VERSION 5.8 ;
BUSBITCHARS "[]" ;
DIVIDERCHAR "/" ;
UNITS
    DATABASE MICRONS 1000 ;
END UNITS

VIA ino_decode_queue_via1_2_1000_440_1_2_410_410
  VIARULE via1Array ;
  CUTSIZE 0.19 0.19 ;
  LAYERS Metal1 Via1 Metal2 ;
  CUTSPACING 0.22 0.22 ;
  ENCLOSURE 0.05 0.125 0.005 0.05 ;
  ROWCOL 1 2 ;
END ino_decode_queue_via1_2_1000_440_1_2_410_410

VIA ino_decode_queue_via2_3_1000_440_1_2_410_410
  VIARULE via2Array ;
  CUTSIZE 0.19 0.19 ;
  LAYERS Metal2 Via2 Metal3 ;
  CUTSPACING 0.22 0.22 ;
  ENCLOSURE 0.005 0.05 0.05 0.005 ;
  ROWCOL 1 2 ;
END ino_decode_queue_via2_3_1000_440_1_2_410_410

VIA ino_decode_queue_via3_4_1000_440_1_2_410_410
  VIARULE via3Array ;
  CUTSIZE 0.19 0.19 ;
  LAYERS Metal3 Via3 Metal4 ;
  CUTSPACING 0.22 0.22 ;
  ENCLOSURE 0.05 0.005 0.2 0.05 ;
  ROWCOL 1 2 ;
END ino_decode_queue_via3_4_1000_440_1_2_410_410

VIA ino_decode_queue_via4_5_1000_2000_1_1_840_840
  VIARULE viaTop1Array ;
  CUTSIZE 0.42 0.42 ;
  LAYERS Metal4 TopVia1 TopMetal1 ;
  CUTSPACING 0.42 0.42 ;
  ENCLOSURE 0.29 0.1 0.42 0.79 ;
END ino_decode_queue_via4_5_1000_2000_1_1_840_840

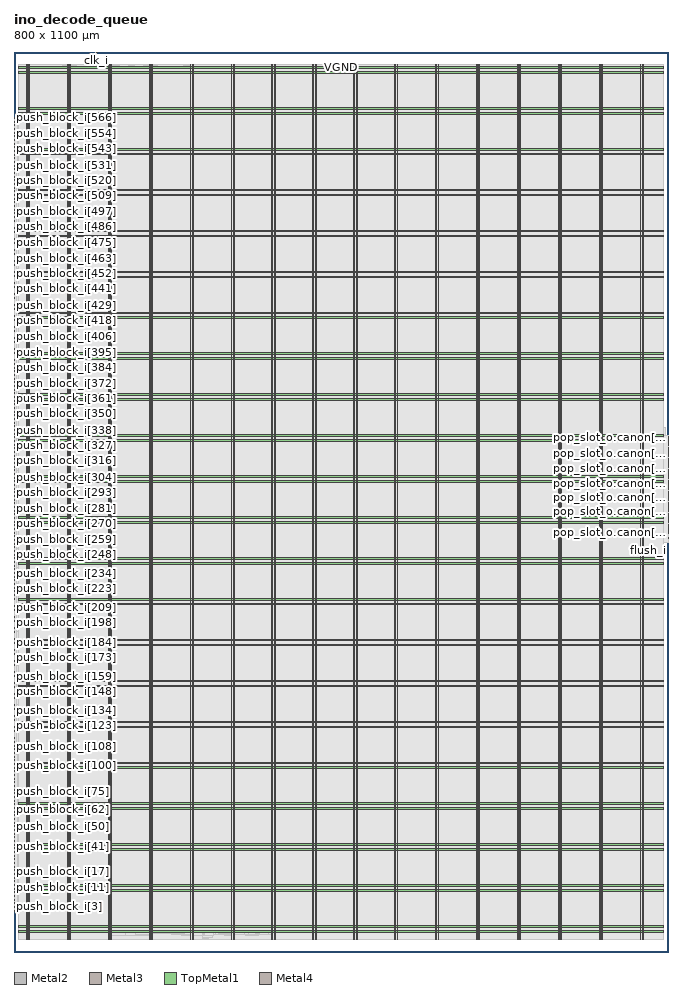
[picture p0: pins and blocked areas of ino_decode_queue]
MACRO ino_decode_queue
  FOREIGN ino_decode_queue 0 0 ;
  CLASS BLOCK ;
  SIZE 800 BY 1100 ;
  PIN clk_i
    DIRECTION INPUT ;
    USE SIGNAL ;
    PORT
      LAYER Metal2 ;
        RECT  101.08 1099.6 101.48 1100 ;
    END
  END clk_i
  PIN flush_i
    DIRECTION INPUT ;
    USE SIGNAL ;
    PORT
      LAYER Metal3 ;
        RECT  799.6 500.02 800 500.42 ;
    END
  END flush_i
  PIN pop_slot_o.canon[0]
    DIRECTION OUTPUT ;
    USE SIGNAL ;
    PORT
      LAYER Metal3 ;
        RECT  799.6 512.62 800 513.02 ;
    END
  END pop_slot_o.canon[0]
  PIN pop_slot_o.canon[10]
    DIRECTION OUTPUT ;
    USE SIGNAL ;
    PORT
      LAYER Metal3 ;
        RECT  799.6 537.82 800 538.22 ;
    END
  END pop_slot_o.canon[10]
  PIN pop_slot_o.canon[11]
    DIRECTION OUTPUT ;
    USE SIGNAL ;
    PORT
      LAYER Metal3 ;
        RECT  799.6 540.34 800 540.74 ;
    END
  END pop_slot_o.canon[11]
  PIN pop_slot_o.canon[12]
    DIRECTION OUTPUT ;
    USE SIGNAL ;
    PORT
      LAYER Metal3 ;
        RECT  799.6 542.86 800 543.26 ;
    END
  END pop_slot_o.canon[12]
  PIN pop_slot_o.canon[13]
    DIRECTION OUTPUT ;
    USE SIGNAL ;
    PORT
      LAYER Metal3 ;
        RECT  799.6 545.38 800 545.78 ;
    END
  END pop_slot_o.canon[13]
  PIN pop_slot_o.canon[14]
    DIRECTION OUTPUT ;
    USE SIGNAL ;
    PORT
      LAYER Metal3 ;
        RECT  799.6 547.9 800 548.3 ;
    END
  END pop_slot_o.canon[14]
  PIN pop_slot_o.canon[15]
    DIRECTION OUTPUT ;
    USE SIGNAL ;
    PORT
      LAYER Metal3 ;
        RECT  799.6 550.42 800 550.82 ;
    END
  END pop_slot_o.canon[15]
  PIN pop_slot_o.canon[16]
    DIRECTION OUTPUT ;
    USE SIGNAL ;
    PORT
      LAYER Metal3 ;
        RECT  799.6 552.94 800 553.34 ;
    END
  END pop_slot_o.canon[16]
  PIN pop_slot_o.canon[17]
    DIRECTION OUTPUT ;
    USE SIGNAL ;
    PORT
      LAYER Metal3 ;
        RECT  799.6 555.46 800 555.86 ;
    END
  END pop_slot_o.canon[17]
  PIN pop_slot_o.canon[18]
    DIRECTION OUTPUT ;
    USE SIGNAL ;
    PORT
      LAYER Metal3 ;
        RECT  799.6 557.98 800 558.38 ;
    END
  END pop_slot_o.canon[18]
  PIN pop_slot_o.canon[19]
    DIRECTION OUTPUT ;
    USE SIGNAL ;
    PORT
      LAYER Metal3 ;
        RECT  799.6 560.5 800 560.9 ;
    END
  END pop_slot_o.canon[19]
  PIN pop_slot_o.canon[1]
    DIRECTION OUTPUT ;
    USE SIGNAL ;
    PORT
      LAYER Metal3 ;
        RECT  799.6 515.14 800 515.54 ;
    END
  END pop_slot_o.canon[1]
  PIN pop_slot_o.canon[20]
    DIRECTION OUTPUT ;
    USE SIGNAL ;
    PORT
      LAYER Metal3 ;
        RECT  799.6 563.02 800 563.42 ;
    END
  END pop_slot_o.canon[20]
  PIN pop_slot_o.canon[21]
    DIRECTION OUTPUT ;
    USE SIGNAL ;
    PORT
      LAYER Metal3 ;
        RECT  799.6 565.54 800 565.94 ;
    END
  END pop_slot_o.canon[21]
  PIN pop_slot_o.canon[22]
    DIRECTION OUTPUT ;
    USE SIGNAL ;
    PORT
      LAYER Metal3 ;
        RECT  799.6 568.06 800 568.46 ;
    END
  END pop_slot_o.canon[22]
  PIN pop_slot_o.canon[23]
    DIRECTION OUTPUT ;
    USE SIGNAL ;
    PORT
      LAYER Metal3 ;
        RECT  799.6 570.58 800 570.98 ;
    END
  END pop_slot_o.canon[23]
  PIN pop_slot_o.canon[24]
    DIRECTION OUTPUT ;
    USE SIGNAL ;
    PORT
      LAYER Metal3 ;
        RECT  799.6 573.1 800 573.5 ;
    END
  END pop_slot_o.canon[24]
  PIN pop_slot_o.canon[25]
    DIRECTION OUTPUT ;
    USE SIGNAL ;
    PORT
      LAYER Metal3 ;
        RECT  799.6 575.62 800 576.02 ;
    END
  END pop_slot_o.canon[25]
  PIN pop_slot_o.canon[26]
    DIRECTION OUTPUT ;
    USE SIGNAL ;
    PORT
      LAYER Metal3 ;
        RECT  799.6 578.14 800 578.54 ;
    END
  END pop_slot_o.canon[26]
  PIN pop_slot_o.canon[27]
    DIRECTION OUTPUT ;
    USE SIGNAL ;
    PORT
      LAYER Metal3 ;
        RECT  799.6 580.66 800 581.06 ;
    END
  END pop_slot_o.canon[27]
  PIN pop_slot_o.canon[28]
    DIRECTION OUTPUT ;
    USE SIGNAL ;
    PORT
      LAYER Metal3 ;
        RECT  799.6 583.18 800 583.58 ;
    END
  END pop_slot_o.canon[28]
  PIN pop_slot_o.canon[29]
    DIRECTION OUTPUT ;
    USE SIGNAL ;
    PORT
      LAYER Metal3 ;
        RECT  799.6 585.7 800 586.1 ;
    END
  END pop_slot_o.canon[29]
  PIN pop_slot_o.canon[2]
    DIRECTION OUTPUT ;
    USE SIGNAL ;
    PORT
      LAYER Metal3 ;
        RECT  799.6 517.66 800 518.06 ;
    END
  END pop_slot_o.canon[2]
  PIN pop_slot_o.canon[30]
    DIRECTION OUTPUT ;
    USE SIGNAL ;
    PORT
      LAYER Metal3 ;
        RECT  799.6 588.22 800 588.62 ;
    END
  END pop_slot_o.canon[30]
  PIN pop_slot_o.canon[31]
    DIRECTION OUTPUT ;
    USE SIGNAL ;
    PORT
      LAYER Metal3 ;
        RECT  799.6 590.74 800 591.14 ;
    END
  END pop_slot_o.canon[31]
  PIN pop_slot_o.canon[32]
    DIRECTION OUTPUT ;
    USE SIGNAL ;
    PORT
      LAYER Metal3 ;
        RECT  799.6 593.26 800 593.66 ;
    END
  END pop_slot_o.canon[32]
  PIN pop_slot_o.canon[33]
    DIRECTION OUTPUT ;
    USE SIGNAL ;
    PORT
      LAYER Metal3 ;
        RECT  799.6 594.94 800 595.34 ;
    END
  END pop_slot_o.canon[33]
  PIN pop_slot_o.canon[34]
    DIRECTION OUTPUT ;
    USE SIGNAL ;
    PORT
      LAYER Metal3 ;
        RECT  799.6 596.62 800 597.02 ;
    END
  END pop_slot_o.canon[34]
  PIN pop_slot_o.canon[35]
    DIRECTION OUTPUT ;
    USE SIGNAL ;
    PORT
      LAYER Metal3 ;
        RECT  799.6 598.3 800 598.7 ;
    END
  END pop_slot_o.canon[35]
  PIN pop_slot_o.canon[36]
    DIRECTION OUTPUT ;
    USE SIGNAL ;
    PORT
      LAYER Metal3 ;
        RECT  799.6 599.98 800 600.38 ;
    END
  END pop_slot_o.canon[36]
  PIN pop_slot_o.canon[37]
    DIRECTION OUTPUT ;
    USE SIGNAL ;
    PORT
      LAYER Metal3 ;
        RECT  799.6 601.66 800 602.06 ;
    END
  END pop_slot_o.canon[37]
  PIN pop_slot_o.canon[38]
    DIRECTION OUTPUT ;
    USE SIGNAL ;
    PORT
      LAYER Metal3 ;
        RECT  799.6 603.34 800 603.74 ;
    END
  END pop_slot_o.canon[38]
  PIN pop_slot_o.canon[39]
    DIRECTION OUTPUT ;
    USE SIGNAL ;
    PORT
      LAYER Metal3 ;
        RECT  799.6 605.02 800 605.42 ;
    END
  END pop_slot_o.canon[39]
  PIN pop_slot_o.canon[3]
    DIRECTION OUTPUT ;
    USE SIGNAL ;
    PORT
      LAYER Metal3 ;
        RECT  799.6 520.18 800 520.58 ;
    END
  END pop_slot_o.canon[3]
  PIN pop_slot_o.canon[40]
    DIRECTION OUTPUT ;
    USE SIGNAL ;
    PORT
      LAYER Metal3 ;
        RECT  799.6 606.7 800 607.1 ;
    END
  END pop_slot_o.canon[40]
  PIN pop_slot_o.canon[41]
    DIRECTION OUTPUT ;
    USE SIGNAL ;
    PORT
      LAYER Metal3 ;
        RECT  799.6 608.38 800 608.78 ;
    END
  END pop_slot_o.canon[41]
  PIN pop_slot_o.canon[42]
    DIRECTION OUTPUT ;
    USE SIGNAL ;
    PORT
      LAYER Metal3 ;
        RECT  799.6 610.06 800 610.46 ;
    END
  END pop_slot_o.canon[42]
  PIN pop_slot_o.canon[43]
    DIRECTION OUTPUT ;
    USE SIGNAL ;
    PORT
      LAYER Metal3 ;
        RECT  799.6 611.74 800 612.14 ;
    END
  END pop_slot_o.canon[43]
  PIN pop_slot_o.canon[44]
    DIRECTION OUTPUT ;
    USE SIGNAL ;
    PORT
      LAYER Metal3 ;
        RECT  799.6 613.42 800 613.82 ;
    END
  END pop_slot_o.canon[44]
  PIN pop_slot_o.canon[45]
    DIRECTION OUTPUT ;
    USE SIGNAL ;
    PORT
      LAYER Metal3 ;
        RECT  799.6 615.1 800 615.5 ;
    END
  END pop_slot_o.canon[45]
  PIN pop_slot_o.canon[46]
    DIRECTION OUTPUT ;
    USE SIGNAL ;
    PORT
      LAYER Metal3 ;
        RECT  799.6 616.78 800 617.18 ;
    END
  END pop_slot_o.canon[46]
  PIN pop_slot_o.canon[47]
    DIRECTION OUTPUT ;
    USE SIGNAL ;
    PORT
      LAYER Metal3 ;
        RECT  799.6 618.46 800 618.86 ;
    END
  END pop_slot_o.canon[47]
  PIN pop_slot_o.canon[48]
    DIRECTION OUTPUT ;
    USE SIGNAL ;
    PORT
      LAYER Metal3 ;
        RECT  799.6 620.14 800 620.54 ;
    END
  END pop_slot_o.canon[48]
  PIN pop_slot_o.canon[49]
    DIRECTION OUTPUT ;
    USE SIGNAL ;
    PORT
      LAYER Metal3 ;
        RECT  799.6 621.82 800 622.22 ;
    END
  END pop_slot_o.canon[49]
  PIN pop_slot_o.canon[4]
    DIRECTION OUTPUT ;
    USE SIGNAL ;
    PORT
      LAYER Metal3 ;
        RECT  799.6 522.7 800 523.1 ;
    END
  END pop_slot_o.canon[4]
  PIN pop_slot_o.canon[50]
    DIRECTION OUTPUT ;
    USE SIGNAL ;
    PORT
      LAYER Metal3 ;
        RECT  799.6 623.5 800 623.9 ;
    END
  END pop_slot_o.canon[50]
  PIN pop_slot_o.canon[51]
    DIRECTION OUTPUT ;
    USE SIGNAL ;
    PORT
      LAYER Metal3 ;
        RECT  799.6 625.18 800 625.58 ;
    END
  END pop_slot_o.canon[51]
  PIN pop_slot_o.canon[52]
    DIRECTION OUTPUT ;
    USE SIGNAL ;
    PORT
      LAYER Metal3 ;
        RECT  799.6 626.86 800 627.26 ;
    END
  END pop_slot_o.canon[52]
  PIN pop_slot_o.canon[53]
    DIRECTION OUTPUT ;
    USE SIGNAL ;
    PORT
      LAYER Metal3 ;
        RECT  799.6 628.54 800 628.94 ;
    END
  END pop_slot_o.canon[53]
  PIN pop_slot_o.canon[54]
    DIRECTION OUTPUT ;
    USE SIGNAL ;
    PORT
      LAYER Metal3 ;
        RECT  799.6 630.22 800 630.62 ;
    END
  END pop_slot_o.canon[54]
  PIN pop_slot_o.canon[55]
    DIRECTION OUTPUT ;
    USE SIGNAL ;
    PORT
      LAYER Metal3 ;
        RECT  799.6 631.06 800 631.46 ;
    END
  END pop_slot_o.canon[55]
  PIN pop_slot_o.canon[5]
    DIRECTION OUTPUT ;
    USE SIGNAL ;
    PORT
      LAYER Metal3 ;
        RECT  799.6 525.22 800 525.62 ;
    END
  END pop_slot_o.canon[5]
  PIN pop_slot_o.canon[6]
    DIRECTION OUTPUT ;
    USE SIGNAL ;
    PORT
      LAYER Metal3 ;
        RECT  799.6 527.74 800 528.14 ;
    END
  END pop_slot_o.canon[6]
  PIN pop_slot_o.canon[7]
    DIRECTION OUTPUT ;
    USE SIGNAL ;
    PORT
      LAYER Metal3 ;
        RECT  799.6 530.26 800 530.66 ;
    END
  END pop_slot_o.canon[7]
  PIN pop_slot_o.canon[8]
    DIRECTION OUTPUT ;
    USE SIGNAL ;
    PORT
      LAYER Metal3 ;
        RECT  799.6 532.78 800 533.18 ;
    END
  END pop_slot_o.canon[8]
  PIN pop_slot_o.canon[9]
    DIRECTION OUTPUT ;
    USE SIGNAL ;
    PORT
      LAYER Metal3 ;
        RECT  799.6 535.3 800 535.7 ;
    END
  END pop_slot_o.canon[9]
  PIN pop_slot_o.pc[0]
    DIRECTION OUTPUT ;
    USE SIGNAL ;
    PORT
      LAYER Metal3 ;
        RECT  799.6 513.46 800 513.86 ;
    END
  END pop_slot_o.pc[0]
  PIN pop_slot_o.pc[10]
    DIRECTION OUTPUT ;
    USE SIGNAL ;
    PORT
      LAYER Metal3 ;
        RECT  799.6 538.66 800 539.06 ;
    END
  END pop_slot_o.pc[10]
  PIN pop_slot_o.pc[11]
    DIRECTION OUTPUT ;
    USE SIGNAL ;
    PORT
      LAYER Metal3 ;
        RECT  799.6 541.18 800 541.58 ;
    END
  END pop_slot_o.pc[11]
  PIN pop_slot_o.pc[12]
    DIRECTION OUTPUT ;
    USE SIGNAL ;
    PORT
      LAYER Metal3 ;
        RECT  799.6 543.7 800 544.1 ;
    END
  END pop_slot_o.pc[12]
  PIN pop_slot_o.pc[13]
    DIRECTION OUTPUT ;
    USE SIGNAL ;
    PORT
      LAYER Metal3 ;
        RECT  799.6 546.22 800 546.62 ;
    END
  END pop_slot_o.pc[13]
  PIN pop_slot_o.pc[14]
    DIRECTION OUTPUT ;
    USE SIGNAL ;
    PORT
      LAYER Metal3 ;
        RECT  799.6 548.74 800 549.14 ;
    END
  END pop_slot_o.pc[14]
  PIN pop_slot_o.pc[15]
    DIRECTION OUTPUT ;
    USE SIGNAL ;
    PORT
      LAYER Metal3 ;
        RECT  799.6 551.26 800 551.66 ;
    END
  END pop_slot_o.pc[15]
  PIN pop_slot_o.pc[16]
    DIRECTION OUTPUT ;
    USE SIGNAL ;
    PORT
      LAYER Metal3 ;
        RECT  799.6 553.78 800 554.18 ;
    END
  END pop_slot_o.pc[16]
  PIN pop_slot_o.pc[17]
    DIRECTION OUTPUT ;
    USE SIGNAL ;
    PORT
      LAYER Metal3 ;
        RECT  799.6 556.3 800 556.7 ;
    END
  END pop_slot_o.pc[17]
  PIN pop_slot_o.pc[18]
    DIRECTION OUTPUT ;
    USE SIGNAL ;
    PORT
      LAYER Metal3 ;
        RECT  799.6 558.82 800 559.22 ;
    END
  END pop_slot_o.pc[18]
  PIN pop_slot_o.pc[19]
    DIRECTION OUTPUT ;
    USE SIGNAL ;
    PORT
      LAYER Metal3 ;
        RECT  799.6 561.34 800 561.74 ;
    END
  END pop_slot_o.pc[19]
  PIN pop_slot_o.pc[1]
    DIRECTION OUTPUT ;
    USE SIGNAL ;
    PORT
      LAYER Metal3 ;
        RECT  799.6 515.98 800 516.38 ;
    END
  END pop_slot_o.pc[1]
  PIN pop_slot_o.pc[20]
    DIRECTION OUTPUT ;
    USE SIGNAL ;
    PORT
      LAYER Metal3 ;
        RECT  799.6 563.86 800 564.26 ;
    END
  END pop_slot_o.pc[20]
  PIN pop_slot_o.pc[21]
    DIRECTION OUTPUT ;
    USE SIGNAL ;
    PORT
      LAYER Metal3 ;
        RECT  799.6 566.38 800 566.78 ;
    END
  END pop_slot_o.pc[21]
  PIN pop_slot_o.pc[22]
    DIRECTION OUTPUT ;
    USE SIGNAL ;
    PORT
      LAYER Metal3 ;
        RECT  799.6 568.9 800 569.3 ;
    END
  END pop_slot_o.pc[22]
  PIN pop_slot_o.pc[23]
    DIRECTION OUTPUT ;
    USE SIGNAL ;
    PORT
      LAYER Metal3 ;
        RECT  799.6 571.42 800 571.82 ;
    END
  END pop_slot_o.pc[23]
  PIN pop_slot_o.pc[24]
    DIRECTION OUTPUT ;
    USE SIGNAL ;
    PORT
      LAYER Metal3 ;
        RECT  799.6 573.94 800 574.34 ;
    END
  END pop_slot_o.pc[24]
  PIN pop_slot_o.pc[25]
    DIRECTION OUTPUT ;
    USE SIGNAL ;
    PORT
      LAYER Metal3 ;
        RECT  799.6 576.46 800 576.86 ;
    END
  END pop_slot_o.pc[25]
  PIN pop_slot_o.pc[26]
    DIRECTION OUTPUT ;
    USE SIGNAL ;
    PORT
      LAYER Metal3 ;
        RECT  799.6 578.98 800 579.38 ;
    END
  END pop_slot_o.pc[26]
  PIN pop_slot_o.pc[27]
    DIRECTION OUTPUT ;
    USE SIGNAL ;
    PORT
      LAYER Metal3 ;
        RECT  799.6 581.5 800 581.9 ;
    END
  END pop_slot_o.pc[27]
  PIN pop_slot_o.pc[28]
    DIRECTION OUTPUT ;
    USE SIGNAL ;
    PORT
      LAYER Metal3 ;
        RECT  799.6 584.02 800 584.42 ;
    END
  END pop_slot_o.pc[28]
  PIN pop_slot_o.pc[29]
    DIRECTION OUTPUT ;
    USE SIGNAL ;
    PORT
      LAYER Metal3 ;
        RECT  799.6 586.54 800 586.94 ;
    END
  END pop_slot_o.pc[29]
  PIN pop_slot_o.pc[2]
    DIRECTION OUTPUT ;
    USE SIGNAL ;
    PORT
      LAYER Metal3 ;
        RECT  799.6 518.5 800 518.9 ;
    END
  END pop_slot_o.pc[2]
  PIN pop_slot_o.pc[30]
    DIRECTION OUTPUT ;
    USE SIGNAL ;
    PORT
      LAYER Metal3 ;
        RECT  799.6 589.06 800 589.46 ;
    END
  END pop_slot_o.pc[30]
  PIN pop_slot_o.pc[31]
    DIRECTION OUTPUT ;
    USE SIGNAL ;
    PORT
      LAYER Metal3 ;
        RECT  799.6 591.58 800 591.98 ;
    END
  END pop_slot_o.pc[31]
  PIN pop_slot_o.pc[3]
    DIRECTION OUTPUT ;
    USE SIGNAL ;
    PORT
      LAYER Metal3 ;
        RECT  799.6 521.02 800 521.42 ;
    END
  END pop_slot_o.pc[3]
  PIN pop_slot_o.pc[4]
    DIRECTION OUTPUT ;
    USE SIGNAL ;
    PORT
      LAYER Metal3 ;
        RECT  799.6 523.54 800 523.94 ;
    END
  END pop_slot_o.pc[4]
  PIN pop_slot_o.pc[5]
    DIRECTION OUTPUT ;
    USE SIGNAL ;
    PORT
      LAYER Metal3 ;
        RECT  799.6 526.06 800 526.46 ;
    END
  END pop_slot_o.pc[5]
  PIN pop_slot_o.pc[6]
    DIRECTION OUTPUT ;
    USE SIGNAL ;
    PORT
      LAYER Metal3 ;
        RECT  799.6 528.58 800 528.98 ;
    END
  END pop_slot_o.pc[6]
  PIN pop_slot_o.pc[7]
    DIRECTION OUTPUT ;
    USE SIGNAL ;
    PORT
      LAYER Metal3 ;
        RECT  799.6 531.1 800 531.5 ;
    END
  END pop_slot_o.pc[7]
  PIN pop_slot_o.pc[8]
    DIRECTION OUTPUT ;
    USE SIGNAL ;
    PORT
      LAYER Metal3 ;
        RECT  799.6 533.62 800 534.02 ;
    END
  END pop_slot_o.pc[8]
  PIN pop_slot_o.pc[9]
    DIRECTION OUTPUT ;
    USE SIGNAL ;
    PORT
      LAYER Metal3 ;
        RECT  799.6 536.14 800 536.54 ;
    END
  END pop_slot_o.pc[9]
  PIN pop_slot_o.pred[0]
    DIRECTION OUTPUT ;
    USE SIGNAL ;
    PORT
      LAYER Metal3 ;
        RECT  799.6 514.3 800 514.7 ;
    END
  END pop_slot_o.pred[0]
  PIN pop_slot_o.pred[10]
    DIRECTION OUTPUT ;
    USE SIGNAL ;
    PORT
      LAYER Metal3 ;
        RECT  799.6 539.5 800 539.9 ;
    END
  END pop_slot_o.pred[10]
  PIN pop_slot_o.pred[11]
    DIRECTION OUTPUT ;
    USE SIGNAL ;
    PORT
      LAYER Metal3 ;
        RECT  799.6 542.02 800 542.42 ;
    END
  END pop_slot_o.pred[11]
  PIN pop_slot_o.pred[12]
    DIRECTION OUTPUT ;
    USE SIGNAL ;
    PORT
      LAYER Metal3 ;
        RECT  799.6 544.54 800 544.94 ;
    END
  END pop_slot_o.pred[12]
  PIN pop_slot_o.pred[13]
    DIRECTION OUTPUT ;
    USE SIGNAL ;
    PORT
      LAYER Metal3 ;
        RECT  799.6 547.06 800 547.46 ;
    END
  END pop_slot_o.pred[13]
  PIN pop_slot_o.pred[14]
    DIRECTION OUTPUT ;
    USE SIGNAL ;
    PORT
      LAYER Metal3 ;
        RECT  799.6 549.58 800 549.98 ;
    END
  END pop_slot_o.pred[14]
  PIN pop_slot_o.pred[15]
    DIRECTION OUTPUT ;
    USE SIGNAL ;
    PORT
      LAYER Metal3 ;
        RECT  799.6 552.1 800 552.5 ;
    END
  END pop_slot_o.pred[15]
  PIN pop_slot_o.pred[16]
    DIRECTION OUTPUT ;
    USE SIGNAL ;
    PORT
      LAYER Metal3 ;
        RECT  799.6 554.62 800 555.02 ;
    END
  END pop_slot_o.pred[16]
  PIN pop_slot_o.pred[17]
    DIRECTION OUTPUT ;
    USE SIGNAL ;
    PORT
      LAYER Metal3 ;
        RECT  799.6 557.14 800 557.54 ;
    END
  END pop_slot_o.pred[17]
  PIN pop_slot_o.pred[18]
    DIRECTION OUTPUT ;
    USE SIGNAL ;
    PORT
      LAYER Metal3 ;
        RECT  799.6 559.66 800 560.06 ;
    END
  END pop_slot_o.pred[18]
  PIN pop_slot_o.pred[19]
    DIRECTION OUTPUT ;
    USE SIGNAL ;
    PORT
      LAYER Metal3 ;
        RECT  799.6 562.18 800 562.58 ;
    END
  END pop_slot_o.pred[19]
  PIN pop_slot_o.pred[1]
    DIRECTION OUTPUT ;
    USE SIGNAL ;
    PORT
      LAYER Metal3 ;
        RECT  799.6 516.82 800 517.22 ;
    END
  END pop_slot_o.pred[1]
  PIN pop_slot_o.pred[20]
    DIRECTION OUTPUT ;
    USE SIGNAL ;
    PORT
      LAYER Metal3 ;
        RECT  799.6 564.7 800 565.1 ;
    END
  END pop_slot_o.pred[20]
  PIN pop_slot_o.pred[21]
    DIRECTION OUTPUT ;
    USE SIGNAL ;
    PORT
      LAYER Metal3 ;
        RECT  799.6 567.22 800 567.62 ;
    END
  END pop_slot_o.pred[21]
  PIN pop_slot_o.pred[22]
    DIRECTION OUTPUT ;
    USE SIGNAL ;
    PORT
      LAYER Metal3 ;
        RECT  799.6 569.74 800 570.14 ;
    END
  END pop_slot_o.pred[22]
  PIN pop_slot_o.pred[23]
    DIRECTION OUTPUT ;
    USE SIGNAL ;
    PORT
      LAYER Metal3 ;
        RECT  799.6 572.26 800 572.66 ;
    END
  END pop_slot_o.pred[23]
  PIN pop_slot_o.pred[24]
    DIRECTION OUTPUT ;
    USE SIGNAL ;
    PORT
      LAYER Metal3 ;
        RECT  799.6 574.78 800 575.18 ;
    END
  END pop_slot_o.pred[24]
  PIN pop_slot_o.pred[25]
    DIRECTION OUTPUT ;
    USE SIGNAL ;
    PORT
      LAYER Metal3 ;
        RECT  799.6 577.3 800 577.7 ;
    END
  END pop_slot_o.pred[25]
  PIN pop_slot_o.pred[26]
    DIRECTION OUTPUT ;
    USE SIGNAL ;
    PORT
      LAYER Metal3 ;
        RECT  799.6 579.82 800 580.22 ;
    END
  END pop_slot_o.pred[26]
  PIN pop_slot_o.pred[27]
    DIRECTION OUTPUT ;
    USE SIGNAL ;
    PORT
      LAYER Metal3 ;
        RECT  799.6 582.34 800 582.74 ;
    END
  END pop_slot_o.pred[27]
  PIN pop_slot_o.pred[28]
    DIRECTION OUTPUT ;
    USE SIGNAL ;
    PORT
      LAYER Metal3 ;
        RECT  799.6 584.86 800 585.26 ;
    END
  END pop_slot_o.pred[28]
  PIN pop_slot_o.pred[29]
    DIRECTION OUTPUT ;
    USE SIGNAL ;
    PORT
      LAYER Metal3 ;
        RECT  799.6 587.38 800 587.78 ;
    END
  END pop_slot_o.pred[29]
  PIN pop_slot_o.pred[2]
    DIRECTION OUTPUT ;
    USE SIGNAL ;
    PORT
      LAYER Metal3 ;
        RECT  799.6 519.34 800 519.74 ;
    END
  END pop_slot_o.pred[2]
  PIN pop_slot_o.pred[30]
    DIRECTION OUTPUT ;
    USE SIGNAL ;
    PORT
      LAYER Metal3 ;
        RECT  799.6 589.9 800 590.3 ;
    END
  END pop_slot_o.pred[30]
  PIN pop_slot_o.pred[31]
    DIRECTION OUTPUT ;
    USE SIGNAL ;
    PORT
      LAYER Metal3 ;
        RECT  799.6 592.42 800 592.82 ;
    END
  END pop_slot_o.pred[31]
  PIN pop_slot_o.pred[32]
    DIRECTION OUTPUT ;
    USE SIGNAL ;
    PORT
      LAYER Metal3 ;
        RECT  799.6 594.1 800 594.5 ;
    END
  END pop_slot_o.pred[32]
  PIN pop_slot_o.pred[33]
    DIRECTION OUTPUT ;
    USE SIGNAL ;
    PORT
      LAYER Metal3 ;
        RECT  799.6 595.78 800 596.18 ;
    END
  END pop_slot_o.pred[33]
  PIN pop_slot_o.pred[34]
    DIRECTION OUTPUT ;
    USE SIGNAL ;
    PORT
      LAYER Metal3 ;
        RECT  799.6 597.46 800 597.86 ;
    END
  END pop_slot_o.pred[34]
  PIN pop_slot_o.pred[35]
    DIRECTION OUTPUT ;
    USE SIGNAL ;
    PORT
      LAYER Metal3 ;
        RECT  799.6 599.14 800 599.54 ;
    END
  END pop_slot_o.pred[35]
  PIN pop_slot_o.pred[36]
    DIRECTION OUTPUT ;
    USE SIGNAL ;
    PORT
      LAYER Metal3 ;
        RECT  799.6 600.82 800 601.22 ;
    END
  END pop_slot_o.pred[36]
  PIN pop_slot_o.pred[37]
    DIRECTION OUTPUT ;
    USE SIGNAL ;
    PORT
      LAYER Metal3 ;
        RECT  799.6 602.5 800 602.9 ;
    END
  END pop_slot_o.pred[37]
  PIN pop_slot_o.pred[38]
    DIRECTION OUTPUT ;
    USE SIGNAL ;
    PORT
      LAYER Metal3 ;
        RECT  799.6 604.18 800 604.58 ;
    END
  END pop_slot_o.pred[38]
  PIN pop_slot_o.pred[39]
    DIRECTION OUTPUT ;
    USE SIGNAL ;
    PORT
      LAYER Metal3 ;
        RECT  799.6 605.86 800 606.26 ;
    END
  END pop_slot_o.pred[39]
  PIN pop_slot_o.pred[3]
    DIRECTION OUTPUT ;
    USE SIGNAL ;
    PORT
      LAYER Metal3 ;
        RECT  799.6 521.86 800 522.26 ;
    END
  END pop_slot_o.pred[3]
  PIN pop_slot_o.pred[40]
    DIRECTION OUTPUT ;
    USE SIGNAL ;
    PORT
      LAYER Metal3 ;
        RECT  799.6 607.54 800 607.94 ;
    END
  END pop_slot_o.pred[40]
  PIN pop_slot_o.pred[41]
    DIRECTION OUTPUT ;
    USE SIGNAL ;
    PORT
      LAYER Metal3 ;
        RECT  799.6 609.22 800 609.62 ;
    END
  END pop_slot_o.pred[41]
  PIN pop_slot_o.pred[42]
    DIRECTION OUTPUT ;
    USE SIGNAL ;
    PORT
      LAYER Metal3 ;
        RECT  799.6 610.9 800 611.3 ;
    END
  END pop_slot_o.pred[42]
  PIN pop_slot_o.pred[43]
    DIRECTION OUTPUT ;
    USE SIGNAL ;
    PORT
      LAYER Metal3 ;
        RECT  799.6 612.58 800 612.98 ;
    END
  END pop_slot_o.pred[43]
  PIN pop_slot_o.pred[44]
    DIRECTION OUTPUT ;
    USE SIGNAL ;
    PORT
      LAYER Metal3 ;
        RECT  799.6 614.26 800 614.66 ;
    END
  END pop_slot_o.pred[44]
  PIN pop_slot_o.pred[45]
    DIRECTION OUTPUT ;
    USE SIGNAL ;
    PORT
      LAYER Metal3 ;
        RECT  799.6 615.94 800 616.34 ;
    END
  END pop_slot_o.pred[45]
  PIN pop_slot_o.pred[46]
    DIRECTION OUTPUT ;
    USE SIGNAL ;
    PORT
      LAYER Metal3 ;
        RECT  799.6 617.62 800 618.02 ;
    END
  END pop_slot_o.pred[46]
  PIN pop_slot_o.pred[47]
    DIRECTION OUTPUT ;
    USE SIGNAL ;
    PORT
      LAYER Metal3 ;
        RECT  799.6 619.3 800 619.7 ;
    END
  END pop_slot_o.pred[47]
  PIN pop_slot_o.pred[48]
    DIRECTION OUTPUT ;
    USE SIGNAL ;
    PORT
      LAYER Metal3 ;
        RECT  799.6 620.98 800 621.38 ;
    END
  END pop_slot_o.pred[48]
  PIN pop_slot_o.pred[49]
    DIRECTION OUTPUT ;
    USE SIGNAL ;
    PORT
      LAYER Metal3 ;
        RECT  799.6 622.66 800 623.06 ;
    END
  END pop_slot_o.pred[49]
  PIN pop_slot_o.pred[4]
    DIRECTION OUTPUT ;
    USE SIGNAL ;
    PORT
      LAYER Metal3 ;
        RECT  799.6 524.38 800 524.78 ;
    END
  END pop_slot_o.pred[4]
  PIN pop_slot_o.pred[50]
    DIRECTION OUTPUT ;
    USE SIGNAL ;
    PORT
      LAYER Metal3 ;
        RECT  799.6 624.34 800 624.74 ;
    END
  END pop_slot_o.pred[50]
  PIN pop_slot_o.pred[51]
    DIRECTION OUTPUT ;
    USE SIGNAL ;
    PORT
      LAYER Metal3 ;
        RECT  799.6 626.02 800 626.42 ;
    END
  END pop_slot_o.pred[51]
  PIN pop_slot_o.pred[52]
    DIRECTION OUTPUT ;
    USE SIGNAL ;
    PORT
      LAYER Metal3 ;
        RECT  799.6 627.7 800 628.1 ;
    END
  END pop_slot_o.pred[52]
  PIN pop_slot_o.pred[53]
    DIRECTION OUTPUT ;
    USE SIGNAL ;
    PORT
      LAYER Metal3 ;
        RECT  799.6 629.38 800 629.78 ;
    END
  END pop_slot_o.pred[53]
  PIN pop_slot_o.pred[5]
    DIRECTION OUTPUT ;
    USE SIGNAL ;
    PORT
      LAYER Metal3 ;
        RECT  799.6 526.9 800 527.3 ;
    END
  END pop_slot_o.pred[5]
  PIN pop_slot_o.pred[6]
    DIRECTION OUTPUT ;
    USE SIGNAL ;
    PORT
      LAYER Metal3 ;
        RECT  799.6 529.42 800 529.82 ;
    END
  END pop_slot_o.pred[6]
  PIN pop_slot_o.pred[7]
    DIRECTION OUTPUT ;
    USE SIGNAL ;
    PORT
      LAYER Metal3 ;
        RECT  799.6 531.94 800 532.34 ;
    END
  END pop_slot_o.pred[7]
  PIN pop_slot_o.pred[8]
    DIRECTION OUTPUT ;
    USE SIGNAL ;
    PORT
      LAYER Metal3 ;
        RECT  799.6 534.46 800 534.86 ;
    END
  END pop_slot_o.pred[8]
  PIN pop_slot_o.pred[9]
    DIRECTION OUTPUT ;
    USE SIGNAL ;
    PORT
      LAYER Metal3 ;
        RECT  799.6 536.98 800 537.38 ;
    END
  END pop_slot_o.pred[9]
  PIN pop_slot_o.valid
    DIRECTION OUTPUT ;
    USE SIGNAL ;
    PORT
      LAYER Metal3 ;
        RECT  799.6 511.78 800 512.18 ;
    END
  END pop_slot_o.valid
  PIN pop_take_i
    DIRECTION INPUT ;
    USE SIGNAL ;
    PORT
      LAYER Metal3 ;
        RECT  799.6 505.9 800 506.3 ;
    END
  END pop_take_i
  PIN push_block_i[0]
    DIRECTION INPUT ;
    USE SIGNAL ;
    PORT
      LAYER Metal3 ;
        RECT  0 59.86 0.4 60.26 ;
    END
  END push_block_i[0]
  PIN push_block_i[100]
    DIRECTION INPUT ;
    USE SIGNAL ;
    PORT
      LAYER Metal3 ;
        RECT  0 227.86 0.4 228.26 ;
    END
  END push_block_i[100]
  PIN push_block_i[101]
    DIRECTION INPUT ;
    USE SIGNAL ;
    PORT
      LAYER Metal3 ;
        RECT  0 229.54 0.4 229.94 ;
    END
  END push_block_i[101]
  PIN push_block_i[102]
    DIRECTION INPUT ;
    USE SIGNAL ;
    PORT
      LAYER Metal3 ;
        RECT  0 231.22 0.4 231.62 ;
    END
  END push_block_i[102]
  PIN push_block_i[103]
    DIRECTION INPUT ;
    USE SIGNAL ;
    PORT
      LAYER Metal3 ;
        RECT  0 232.9 0.4 233.3 ;
    END
  END push_block_i[103]
  PIN push_block_i[104]
    DIRECTION INPUT ;
    USE SIGNAL ;
    PORT
      LAYER Metal3 ;
        RECT  0 234.58 0.4 234.98 ;
    END
  END push_block_i[104]
  PIN push_block_i[105]
    DIRECTION INPUT ;
    USE SIGNAL ;
    PORT
      LAYER Metal3 ;
        RECT  0 236.26 0.4 236.66 ;
    END
  END push_block_i[105]
  PIN push_block_i[106]
    DIRECTION INPUT ;
    USE SIGNAL ;
    PORT
      LAYER Metal3 ;
        RECT  0 237.94 0.4 238.34 ;
    END
  END push_block_i[106]
  PIN push_block_i[107]
    DIRECTION INPUT ;
    USE SIGNAL ;
    PORT
      LAYER Metal3 ;
        RECT  0 239.62 0.4 240.02 ;
    END
  END push_block_i[107]
  PIN push_block_i[108]
    DIRECTION INPUT ;
    USE SIGNAL ;
    PORT
      LAYER Metal3 ;
        RECT  0 241.3 0.4 241.7 ;
    END
  END push_block_i[108]
  PIN push_block_i[109]
    DIRECTION INPUT ;
    USE SIGNAL ;
    PORT
      LAYER Metal3 ;
        RECT  0 242.98 0.4 243.38 ;
    END
  END push_block_i[109]
  PIN push_block_i[10]
    DIRECTION INPUT ;
    USE SIGNAL ;
    PORT
      LAYER Metal3 ;
        RECT  0 76.66 0.4 77.06 ;
    END
  END push_block_i[10]
  PIN push_block_i[110]
    DIRECTION INPUT ;
    USE SIGNAL ;
    PORT
      LAYER Metal3 ;
        RECT  0 244.66 0.4 245.06 ;
    END
  END push_block_i[110]
  PIN push_block_i[111]
    DIRECTION INPUT ;
    USE SIGNAL ;
    PORT
      LAYER Metal3 ;
        RECT  0 246.34 0.4 246.74 ;
    END
  END push_block_i[111]
  PIN push_block_i[112]
    DIRECTION INPUT ;
    USE SIGNAL ;
    PORT
      LAYER Metal3 ;
        RECT  0 248.02 0.4 248.42 ;
    END
  END push_block_i[112]
  PIN push_block_i[113]
    DIRECTION INPUT ;
    USE SIGNAL ;
    PORT
      LAYER Metal3 ;
        RECT  0 249.7 0.4 250.1 ;
    END
  END push_block_i[113]
  PIN push_block_i[114]
    DIRECTION INPUT ;
    USE SIGNAL ;
    PORT
      LAYER Metal3 ;
        RECT  0 251.38 0.4 251.78 ;
    END
  END push_block_i[114]
  PIN push_block_i[115]
    DIRECTION INPUT ;
    USE SIGNAL ;
    PORT
      LAYER Metal3 ;
        RECT  0 253.06 0.4 253.46 ;
    END
  END push_block_i[115]
  PIN push_block_i[116]
    DIRECTION INPUT ;
    USE SIGNAL ;
    PORT
      LAYER Metal3 ;
        RECT  0 254.74 0.4 255.14 ;
    END
  END push_block_i[116]
  PIN push_block_i[117]
    DIRECTION INPUT ;
    USE SIGNAL ;
    PORT
      LAYER Metal3 ;
        RECT  0 256.42 0.4 256.82 ;
    END
  END push_block_i[117]
  PIN push_block_i[118]
    DIRECTION INPUT ;
    USE SIGNAL ;
    PORT
      LAYER Metal3 ;
        RECT  0 258.1 0.4 258.5 ;
    END
  END push_block_i[118]
  PIN push_block_i[119]
    DIRECTION INPUT ;
    USE SIGNAL ;
    PORT
      LAYER Metal3 ;
        RECT  0 259.78 0.4 260.18 ;
    END
  END push_block_i[119]
  PIN push_block_i[11]
    DIRECTION INPUT ;
    USE SIGNAL ;
    PORT
      LAYER Metal3 ;
        RECT  0 78.34 0.4 78.74 ;
    END
  END push_block_i[11]
  PIN push_block_i[120]
    DIRECTION INPUT ;
    USE SIGNAL ;
    PORT
      LAYER Metal3 ;
        RECT  0 261.46 0.4 261.86 ;
    END
  END push_block_i[120]
  PIN push_block_i[121]
    DIRECTION INPUT ;
    USE SIGNAL ;
    PORT
      LAYER Metal3 ;
        RECT  0 263.14 0.4 263.54 ;
    END
  END push_block_i[121]
  PIN push_block_i[122]
    DIRECTION INPUT ;
    USE SIGNAL ;
    PORT
      LAYER Metal3 ;
        RECT  0 264.82 0.4 265.22 ;
    END
  END push_block_i[122]
  PIN push_block_i[123]
    DIRECTION INPUT ;
    USE SIGNAL ;
    PORT
      LAYER Metal3 ;
        RECT  0 266.5 0.4 266.9 ;
    END
  END push_block_i[123]
  PIN push_block_i[124]
    DIRECTION INPUT ;
    USE SIGNAL ;
    PORT
      LAYER Metal3 ;
        RECT  0 268.18 0.4 268.58 ;
    END
  END push_block_i[124]
  PIN push_block_i[125]
    DIRECTION INPUT ;
    USE SIGNAL ;
    PORT
      LAYER Metal3 ;
        RECT  0 269.86 0.4 270.26 ;
    END
  END push_block_i[125]
  PIN push_block_i[126]
    DIRECTION INPUT ;
    USE SIGNAL ;
    PORT
      LAYER Metal3 ;
        RECT  0 271.54 0.4 271.94 ;
    END
  END push_block_i[126]
  PIN push_block_i[127]
    DIRECTION INPUT ;
    USE SIGNAL ;
    PORT
      LAYER Metal3 ;
        RECT  0 273.22 0.4 273.62 ;
    END
  END push_block_i[127]
  PIN push_block_i[128]
    DIRECTION INPUT ;
    USE SIGNAL ;
    PORT
      LAYER Metal3 ;
        RECT  0 274.9 0.4 275.3 ;
    END
  END push_block_i[128]
  PIN push_block_i[129]
    DIRECTION INPUT ;
    USE SIGNAL ;
    PORT
      LAYER Metal3 ;
        RECT  0 276.58 0.4 276.98 ;
    END
  END push_block_i[129]
  PIN push_block_i[12]
    DIRECTION INPUT ;
    USE SIGNAL ;
    PORT
      LAYER Metal3 ;
        RECT  0 80.02 0.4 80.42 ;
    END
  END push_block_i[12]
  PIN push_block_i[130]
    DIRECTION INPUT ;
    USE SIGNAL ;
    PORT
      LAYER Metal3 ;
        RECT  0 278.26 0.4 278.66 ;
    END
  END push_block_i[130]
  PIN push_block_i[131]
    DIRECTION INPUT ;
    USE SIGNAL ;
    PORT
      LAYER Metal3 ;
        RECT  0 279.94 0.4 280.34 ;
    END
  END push_block_i[131]
  PIN push_block_i[132]
    DIRECTION INPUT ;
    USE SIGNAL ;
    PORT
      LAYER Metal3 ;
        RECT  0 281.62 0.4 282.02 ;
    END
  END push_block_i[132]
  PIN push_block_i[133]
    DIRECTION INPUT ;
    USE SIGNAL ;
    PORT
      LAYER Metal3 ;
        RECT  0 283.3 0.4 283.7 ;
    END
  END push_block_i[133]
  PIN push_block_i[134]
    DIRECTION INPUT ;
    USE SIGNAL ;
    PORT
      LAYER Metal3 ;
        RECT  0 284.98 0.4 285.38 ;
    END
  END push_block_i[134]
  PIN push_block_i[135]
    DIRECTION INPUT ;
    USE SIGNAL ;
    PORT
      LAYER Metal3 ;
        RECT  0 286.66 0.4 287.06 ;
    END
  END push_block_i[135]
  PIN push_block_i[136]
    DIRECTION INPUT ;
    USE SIGNAL ;
    PORT
      LAYER Metal3 ;
        RECT  0 288.34 0.4 288.74 ;
    END
  END push_block_i[136]
  PIN push_block_i[137]
    DIRECTION INPUT ;
    USE SIGNAL ;
    PORT
      LAYER Metal3 ;
        RECT  0 290.02 0.4 290.42 ;
    END
  END push_block_i[137]
  PIN push_block_i[138]
    DIRECTION INPUT ;
    USE SIGNAL ;
    PORT
      LAYER Metal3 ;
        RECT  0 291.7 0.4 292.1 ;
    END
  END push_block_i[138]
  PIN push_block_i[139]
    DIRECTION INPUT ;
    USE SIGNAL ;
    PORT
      LAYER Metal3 ;
        RECT  0 293.38 0.4 293.78 ;
    END
  END push_block_i[139]
  PIN push_block_i[13]
    DIRECTION INPUT ;
    USE SIGNAL ;
    PORT
      LAYER Metal3 ;
        RECT  0 81.7 0.4 82.1 ;
    END
  END push_block_i[13]
  PIN push_block_i[140]
    DIRECTION INPUT ;
    USE SIGNAL ;
    PORT
      LAYER Metal3 ;
        RECT  0 295.06 0.4 295.46 ;
    END
  END push_block_i[140]
  PIN push_block_i[141]
    DIRECTION INPUT ;
    USE SIGNAL ;
    PORT
      LAYER Metal3 ;
        RECT  0 296.74 0.4 297.14 ;
    END
  END push_block_i[141]
  PIN push_block_i[142]
    DIRECTION INPUT ;
    USE SIGNAL ;
    PORT
      LAYER Metal3 ;
        RECT  0 298.42 0.4 298.82 ;
    END
  END push_block_i[142]
  PIN push_block_i[143]
    DIRECTION INPUT ;
    USE SIGNAL ;
    PORT
      LAYER Metal3 ;
        RECT  0 300.1 0.4 300.5 ;
    END
  END push_block_i[143]
  PIN push_block_i[144]
    DIRECTION INPUT ;
    USE SIGNAL ;
    PORT
      LAYER Metal3 ;
        RECT  0 301.78 0.4 302.18 ;
    END
  END push_block_i[144]
  PIN push_block_i[145]
    DIRECTION INPUT ;
    USE SIGNAL ;
    PORT
      LAYER Metal3 ;
        RECT  0 303.46 0.4 303.86 ;
    END
  END push_block_i[145]
  PIN push_block_i[146]
    DIRECTION INPUT ;
    USE SIGNAL ;
    PORT
      LAYER Metal3 ;
        RECT  0 305.14 0.4 305.54 ;
    END
  END push_block_i[146]
  PIN push_block_i[147]
    DIRECTION INPUT ;
    USE SIGNAL ;
    PORT
      LAYER Metal3 ;
        RECT  0 306.82 0.4 307.22 ;
    END
  END push_block_i[147]
  PIN push_block_i[148]
    DIRECTION INPUT ;
    USE SIGNAL ;
    PORT
      LAYER Metal3 ;
        RECT  0 308.5 0.4 308.9 ;
    END
  END push_block_i[148]
  PIN push_block_i[149]
    DIRECTION INPUT ;
    USE SIGNAL ;
    PORT
      LAYER Metal3 ;
        RECT  0 310.18 0.4 310.58 ;
    END
  END push_block_i[149]
  PIN push_block_i[14]
    DIRECTION INPUT ;
    USE SIGNAL ;
    PORT
      LAYER Metal3 ;
        RECT  0 83.38 0.4 83.78 ;
    END
  END push_block_i[14]
  PIN push_block_i[150]
    DIRECTION INPUT ;
    USE SIGNAL ;
    PORT
      LAYER Metal3 ;
        RECT  0 311.86 0.4 312.26 ;
    END
  END push_block_i[150]
  PIN push_block_i[151]
    DIRECTION INPUT ;
    USE SIGNAL ;
    PORT
      LAYER Metal3 ;
        RECT  0 313.54 0.4 313.94 ;
    END
  END push_block_i[151]
  PIN push_block_i[152]
    DIRECTION INPUT ;
    USE SIGNAL ;
    PORT
      LAYER Metal3 ;
        RECT  0 315.22 0.4 315.62 ;
    END
  END push_block_i[152]
  PIN push_block_i[153]
    DIRECTION INPUT ;
    USE SIGNAL ;
    PORT
      LAYER Metal3 ;
        RECT  0 316.9 0.4 317.3 ;
    END
  END push_block_i[153]
  PIN push_block_i[154]
    DIRECTION INPUT ;
    USE SIGNAL ;
    PORT
      LAYER Metal3 ;
        RECT  0 318.58 0.4 318.98 ;
    END
  END push_block_i[154]
  PIN push_block_i[155]
    DIRECTION INPUT ;
    USE SIGNAL ;
    PORT
      LAYER Metal3 ;
        RECT  0 320.26 0.4 320.66 ;
    END
  END push_block_i[155]
  PIN push_block_i[156]
    DIRECTION INPUT ;
    USE SIGNAL ;
    PORT
      LAYER Metal3 ;
        RECT  0 321.94 0.4 322.34 ;
    END
  END push_block_i[156]
  PIN push_block_i[157]
    DIRECTION INPUT ;
    USE SIGNAL ;
    PORT
      LAYER Metal3 ;
        RECT  0 323.62 0.4 324.02 ;
    END
  END push_block_i[157]
  PIN push_block_i[158]
    DIRECTION INPUT ;
    USE SIGNAL ;
    PORT
      LAYER Metal3 ;
        RECT  0 325.3 0.4 325.7 ;
    END
  END push_block_i[158]
  PIN push_block_i[159]
    DIRECTION INPUT ;
    USE SIGNAL ;
    PORT
      LAYER Metal3 ;
        RECT  0 326.98 0.4 327.38 ;
    END
  END push_block_i[159]
  PIN push_block_i[15]
    DIRECTION INPUT ;
    USE SIGNAL ;
    PORT
      LAYER Metal3 ;
        RECT  0 85.06 0.4 85.46 ;
    END
  END push_block_i[15]
  PIN push_block_i[160]
    DIRECTION INPUT ;
    USE SIGNAL ;
    PORT
      LAYER Metal3 ;
        RECT  0 328.66 0.4 329.06 ;
    END
  END push_block_i[160]
  PIN push_block_i[161]
    DIRECTION INPUT ;
    USE SIGNAL ;
    PORT
      LAYER Metal3 ;
        RECT  0 330.34 0.4 330.74 ;
    END
  END push_block_i[161]
  PIN push_block_i[162]
    DIRECTION INPUT ;
    USE SIGNAL ;
    PORT
      LAYER Metal3 ;
        RECT  0 332.02 0.4 332.42 ;
    END
  END push_block_i[162]
  PIN push_block_i[163]
    DIRECTION INPUT ;
    USE SIGNAL ;
    PORT
      LAYER Metal3 ;
        RECT  0 333.7 0.4 334.1 ;
    END
  END push_block_i[163]
  PIN push_block_i[164]
    DIRECTION INPUT ;
    USE SIGNAL ;
    PORT
      LAYER Metal3 ;
        RECT  0 335.38 0.4 335.78 ;
    END
  END push_block_i[164]
  PIN push_block_i[165]
    DIRECTION INPUT ;
    USE SIGNAL ;
    PORT
      LAYER Metal3 ;
        RECT  0 337.06 0.4 337.46 ;
    END
  END push_block_i[165]
  PIN push_block_i[166]
    DIRECTION INPUT ;
    USE SIGNAL ;
    PORT
      LAYER Metal3 ;
        RECT  0 338.74 0.4 339.14 ;
    END
  END push_block_i[166]
  PIN push_block_i[167]
    DIRECTION INPUT ;
    USE SIGNAL ;
    PORT
      LAYER Metal3 ;
        RECT  0 340.42 0.4 340.82 ;
    END
  END push_block_i[167]
  PIN push_block_i[168]
    DIRECTION INPUT ;
    USE SIGNAL ;
    PORT
      LAYER Metal3 ;
        RECT  0 342.1 0.4 342.5 ;
    END
  END push_block_i[168]
  PIN push_block_i[169]
    DIRECTION INPUT ;
    USE SIGNAL ;
    PORT
      LAYER Metal3 ;
        RECT  0 343.78 0.4 344.18 ;
    END
  END push_block_i[169]
  PIN push_block_i[16]
    DIRECTION INPUT ;
    USE SIGNAL ;
    PORT
      LAYER Metal3 ;
        RECT  0 86.74 0.4 87.14 ;
    END
  END push_block_i[16]
  PIN push_block_i[170]
    DIRECTION INPUT ;
    USE SIGNAL ;
    PORT
      LAYER Metal3 ;
        RECT  0 345.46 0.4 345.86 ;
    END
  END push_block_i[170]
  PIN push_block_i[171]
    DIRECTION INPUT ;
    USE SIGNAL ;
    PORT
      LAYER Metal3 ;
        RECT  0 347.14 0.4 347.54 ;
    END
  END push_block_i[171]
  PIN push_block_i[172]
    DIRECTION INPUT ;
    USE SIGNAL ;
    PORT
      LAYER Metal3 ;
        RECT  0 348.82 0.4 349.22 ;
    END
  END push_block_i[172]
  PIN push_block_i[173]
    DIRECTION INPUT ;
    USE SIGNAL ;
    PORT
      LAYER Metal3 ;
        RECT  0 350.5 0.4 350.9 ;
    END
  END push_block_i[173]
  PIN push_block_i[174]
    DIRECTION INPUT ;
    USE SIGNAL ;
    PORT
      LAYER Metal3 ;
        RECT  0 352.18 0.4 352.58 ;
    END
  END push_block_i[174]
  PIN push_block_i[175]
    DIRECTION INPUT ;
    USE SIGNAL ;
    PORT
      LAYER Metal3 ;
        RECT  0 353.86 0.4 354.26 ;
    END
  END push_block_i[175]
  PIN push_block_i[176]
    DIRECTION INPUT ;
    USE SIGNAL ;
    PORT
      LAYER Metal3 ;
        RECT  0 355.54 0.4 355.94 ;
    END
  END push_block_i[176]
  PIN push_block_i[177]
    DIRECTION INPUT ;
    USE SIGNAL ;
    PORT
      LAYER Metal3 ;
        RECT  0 357.22 0.4 357.62 ;
    END
  END push_block_i[177]
  PIN push_block_i[178]
    DIRECTION INPUT ;
    USE SIGNAL ;
    PORT
      LAYER Metal3 ;
        RECT  0 358.9 0.4 359.3 ;
    END
  END push_block_i[178]
  PIN push_block_i[179]
    DIRECTION INPUT ;
    USE SIGNAL ;
    PORT
      LAYER Metal3 ;
        RECT  0 360.58 0.4 360.98 ;
    END
  END push_block_i[179]
  PIN push_block_i[17]
    DIRECTION INPUT ;
    USE SIGNAL ;
    PORT
      LAYER Metal3 ;
        RECT  0 88.42 0.4 88.82 ;
    END
  END push_block_i[17]
  PIN push_block_i[180]
    DIRECTION INPUT ;
    USE SIGNAL ;
    PORT
      LAYER Metal3 ;
        RECT  0 362.26 0.4 362.66 ;
    END
  END push_block_i[180]
  PIN push_block_i[181]
    DIRECTION INPUT ;
    USE SIGNAL ;
    PORT
      LAYER Metal3 ;
        RECT  0 363.94 0.4 364.34 ;
    END
  END push_block_i[181]
  PIN push_block_i[182]
    DIRECTION INPUT ;
    USE SIGNAL ;
    PORT
      LAYER Metal3 ;
        RECT  0 365.62 0.4 366.02 ;
    END
  END push_block_i[182]
  PIN push_block_i[183]
    DIRECTION INPUT ;
    USE SIGNAL ;
    PORT
      LAYER Metal3 ;
        RECT  0 367.3 0.4 367.7 ;
    END
  END push_block_i[183]
  PIN push_block_i[184]
    DIRECTION INPUT ;
    USE SIGNAL ;
    PORT
      LAYER Metal3 ;
        RECT  0 368.98 0.4 369.38 ;
    END
  END push_block_i[184]
  PIN push_block_i[185]
    DIRECTION INPUT ;
    USE SIGNAL ;
    PORT
      LAYER Metal3 ;
        RECT  0 370.66 0.4 371.06 ;
    END
  END push_block_i[185]
  PIN push_block_i[186]
    DIRECTION INPUT ;
    USE SIGNAL ;
    PORT
      LAYER Metal3 ;
        RECT  0 372.34 0.4 372.74 ;
    END
  END push_block_i[186]
  PIN push_block_i[187]
    DIRECTION INPUT ;
    USE SIGNAL ;
    PORT
      LAYER Metal3 ;
        RECT  0 374.02 0.4 374.42 ;
    END
  END push_block_i[187]
  PIN push_block_i[188]
    DIRECTION INPUT ;
    USE SIGNAL ;
    PORT
      LAYER Metal3 ;
        RECT  0 375.7 0.4 376.1 ;
    END
  END push_block_i[188]
  PIN push_block_i[189]
    DIRECTION INPUT ;
    USE SIGNAL ;
    PORT
      LAYER Metal3 ;
        RECT  0 377.38 0.4 377.78 ;
    END
  END push_block_i[189]
  PIN push_block_i[18]
    DIRECTION INPUT ;
    USE SIGNAL ;
    PORT
      LAYER Metal3 ;
        RECT  0 90.1 0.4 90.5 ;
    END
  END push_block_i[18]
  PIN push_block_i[190]
    DIRECTION INPUT ;
    USE SIGNAL ;
    PORT
      LAYER Metal3 ;
        RECT  0 379.06 0.4 379.46 ;
    END
  END push_block_i[190]
  PIN push_block_i[191]
    DIRECTION INPUT ;
    USE SIGNAL ;
    PORT
      LAYER Metal3 ;
        RECT  0 380.74 0.4 381.14 ;
    END
  END push_block_i[191]
  PIN push_block_i[192]
    DIRECTION INPUT ;
    USE SIGNAL ;
    PORT
      LAYER Metal3 ;
        RECT  0 382.42 0.4 382.82 ;
    END
  END push_block_i[192]
  PIN push_block_i[193]
    DIRECTION INPUT ;
    USE SIGNAL ;
    PORT
      LAYER Metal3 ;
        RECT  0 384.1 0.4 384.5 ;
    END
  END push_block_i[193]
  PIN push_block_i[194]
    DIRECTION INPUT ;
    USE SIGNAL ;
    PORT
      LAYER Metal3 ;
        RECT  0 385.78 0.4 386.18 ;
    END
  END push_block_i[194]
  PIN push_block_i[195]
    DIRECTION INPUT ;
    USE SIGNAL ;
    PORT
      LAYER Metal3 ;
        RECT  0 387.46 0.4 387.86 ;
    END
  END push_block_i[195]
  PIN push_block_i[196]
    DIRECTION INPUT ;
    USE SIGNAL ;
    PORT
      LAYER Metal3 ;
        RECT  0 389.14 0.4 389.54 ;
    END
  END push_block_i[196]
  PIN push_block_i[197]
    DIRECTION INPUT ;
    USE SIGNAL ;
    PORT
      LAYER Metal3 ;
        RECT  0 390.82 0.4 391.22 ;
    END
  END push_block_i[197]
  PIN push_block_i[198]
    DIRECTION INPUT ;
    USE SIGNAL ;
    PORT
      LAYER Metal3 ;
        RECT  0 392.5 0.4 392.9 ;
    END
  END push_block_i[198]
  PIN push_block_i[199]
    DIRECTION INPUT ;
    USE SIGNAL ;
    PORT
      LAYER Metal3 ;
        RECT  0 394.18 0.4 394.58 ;
    END
  END push_block_i[199]
  PIN push_block_i[19]
    DIRECTION INPUT ;
    USE SIGNAL ;
    PORT
      LAYER Metal3 ;
        RECT  0 91.78 0.4 92.18 ;
    END
  END push_block_i[19]
  PIN push_block_i[1]
    DIRECTION INPUT ;
    USE SIGNAL ;
    PORT
      LAYER Metal3 ;
        RECT  0 61.54 0.4 61.94 ;
    END
  END push_block_i[1]
  PIN push_block_i[200]
    DIRECTION INPUT ;
    USE SIGNAL ;
    PORT
      LAYER Metal3 ;
        RECT  0 395.86 0.4 396.26 ;
    END
  END push_block_i[200]
  PIN push_block_i[201]
    DIRECTION INPUT ;
    USE SIGNAL ;
    PORT
      LAYER Metal3 ;
        RECT  0 397.54 0.4 397.94 ;
    END
  END push_block_i[201]
  PIN push_block_i[202]
    DIRECTION INPUT ;
    USE SIGNAL ;
    PORT
      LAYER Metal3 ;
        RECT  0 399.22 0.4 399.62 ;
    END
  END push_block_i[202]
  PIN push_block_i[203]
    DIRECTION INPUT ;
    USE SIGNAL ;
    PORT
      LAYER Metal3 ;
        RECT  0 400.9 0.4 401.3 ;
    END
  END push_block_i[203]
  PIN push_block_i[204]
    DIRECTION INPUT ;
    USE SIGNAL ;
    PORT
      LAYER Metal3 ;
        RECT  0 402.58 0.4 402.98 ;
    END
  END push_block_i[204]
  PIN push_block_i[205]
    DIRECTION INPUT ;
    USE SIGNAL ;
    PORT
      LAYER Metal3 ;
        RECT  0 404.26 0.4 404.66 ;
    END
  END push_block_i[205]
  PIN push_block_i[206]
    DIRECTION INPUT ;
    USE SIGNAL ;
    PORT
      LAYER Metal3 ;
        RECT  0 405.94 0.4 406.34 ;
    END
  END push_block_i[206]
  PIN push_block_i[207]
    DIRECTION INPUT ;
    USE SIGNAL ;
    PORT
      LAYER Metal3 ;
        RECT  0 407.62 0.4 408.02 ;
    END
  END push_block_i[207]
  PIN push_block_i[208]
    DIRECTION INPUT ;
    USE SIGNAL ;
    PORT
      LAYER Metal3 ;
        RECT  0 409.3 0.4 409.7 ;
    END
  END push_block_i[208]
  PIN push_block_i[209]
    DIRECTION INPUT ;
    USE SIGNAL ;
    PORT
      LAYER Metal3 ;
        RECT  0 410.98 0.4 411.38 ;
    END
  END push_block_i[209]
  PIN push_block_i[20]
    DIRECTION INPUT ;
    USE SIGNAL ;
    PORT
      LAYER Metal3 ;
        RECT  0 93.46 0.4 93.86 ;
    END
  END push_block_i[20]
  PIN push_block_i[210]
    DIRECTION INPUT ;
    USE SIGNAL ;
    PORT
      LAYER Metal3 ;
        RECT  0 412.66 0.4 413.06 ;
    END
  END push_block_i[210]
  PIN push_block_i[211]
    DIRECTION INPUT ;
    USE SIGNAL ;
    PORT
      LAYER Metal3 ;
        RECT  0 414.34 0.4 414.74 ;
    END
  END push_block_i[211]
  PIN push_block_i[212]
    DIRECTION INPUT ;
    USE SIGNAL ;
    PORT
      LAYER Metal3 ;
        RECT  0 416.02 0.4 416.42 ;
    END
  END push_block_i[212]
  PIN push_block_i[213]
    DIRECTION INPUT ;
    USE SIGNAL ;
    PORT
      LAYER Metal3 ;
        RECT  0 417.7 0.4 418.1 ;
    END
  END push_block_i[213]
  PIN push_block_i[214]
    DIRECTION INPUT ;
    USE SIGNAL ;
    PORT
      LAYER Metal3 ;
        RECT  0 419.38 0.4 419.78 ;
    END
  END push_block_i[214]
  PIN push_block_i[215]
    DIRECTION INPUT ;
    USE SIGNAL ;
    PORT
      LAYER Metal3 ;
        RECT  0 421.06 0.4 421.46 ;
    END
  END push_block_i[215]
  PIN push_block_i[216]
    DIRECTION INPUT ;
    USE SIGNAL ;
    PORT
      LAYER Metal3 ;
        RECT  0 422.74 0.4 423.14 ;
    END
  END push_block_i[216]
  PIN push_block_i[217]
    DIRECTION INPUT ;
    USE SIGNAL ;
    PORT
      LAYER Metal3 ;
        RECT  0 424.42 0.4 424.82 ;
    END
  END push_block_i[217]
  PIN push_block_i[218]
    DIRECTION INPUT ;
    USE SIGNAL ;
    PORT
      LAYER Metal3 ;
        RECT  0 426.1 0.4 426.5 ;
    END
  END push_block_i[218]
  PIN push_block_i[219]
    DIRECTION INPUT ;
    USE SIGNAL ;
    PORT
      LAYER Metal3 ;
        RECT  0 427.78 0.4 428.18 ;
    END
  END push_block_i[219]
  PIN push_block_i[21]
    DIRECTION INPUT ;
    USE SIGNAL ;
    PORT
      LAYER Metal3 ;
        RECT  0 95.14 0.4 95.54 ;
    END
  END push_block_i[21]
  PIN push_block_i[220]
    DIRECTION INPUT ;
    USE SIGNAL ;
    PORT
      LAYER Metal3 ;
        RECT  0 429.46 0.4 429.86 ;
    END
  END push_block_i[220]
  PIN push_block_i[221]
    DIRECTION INPUT ;
    USE SIGNAL ;
    PORT
      LAYER Metal3 ;
        RECT  0 431.14 0.4 431.54 ;
    END
  END push_block_i[221]
  PIN push_block_i[222]
    DIRECTION INPUT ;
    USE SIGNAL ;
    PORT
      LAYER Metal3 ;
        RECT  0 432.82 0.4 433.22 ;
    END
  END push_block_i[222]
  PIN push_block_i[223]
    DIRECTION INPUT ;
    USE SIGNAL ;
    PORT
      LAYER Metal3 ;
        RECT  0 434.5 0.4 434.9 ;
    END
  END push_block_i[223]
  PIN push_block_i[224]
    DIRECTION INPUT ;
    USE SIGNAL ;
    PORT
      LAYER Metal3 ;
        RECT  0 436.18 0.4 436.58 ;
    END
  END push_block_i[224]
  PIN push_block_i[225]
    DIRECTION INPUT ;
    USE SIGNAL ;
    PORT
      LAYER Metal3 ;
        RECT  0 437.86 0.4 438.26 ;
    END
  END push_block_i[225]
  PIN push_block_i[226]
    DIRECTION INPUT ;
    USE SIGNAL ;
    PORT
      LAYER Metal3 ;
        RECT  0 439.54 0.4 439.94 ;
    END
  END push_block_i[226]
  PIN push_block_i[227]
    DIRECTION INPUT ;
    USE SIGNAL ;
    PORT
      LAYER Metal3 ;
        RECT  0 441.22 0.4 441.62 ;
    END
  END push_block_i[227]
  PIN push_block_i[228]
    DIRECTION INPUT ;
    USE SIGNAL ;
    PORT
      LAYER Metal3 ;
        RECT  0 442.9 0.4 443.3 ;
    END
  END push_block_i[228]
  PIN push_block_i[229]
    DIRECTION INPUT ;
    USE SIGNAL ;
    PORT
      LAYER Metal3 ;
        RECT  0 444.58 0.4 444.98 ;
    END
  END push_block_i[229]
  PIN push_block_i[22]
    DIRECTION INPUT ;
    USE SIGNAL ;
    PORT
      LAYER Metal3 ;
        RECT  0 96.82 0.4 97.22 ;
    END
  END push_block_i[22]
  PIN push_block_i[230]
    DIRECTION INPUT ;
    USE SIGNAL ;
    PORT
      LAYER Metal3 ;
        RECT  0 446.26 0.4 446.66 ;
    END
  END push_block_i[230]
  PIN push_block_i[231]
    DIRECTION INPUT ;
    USE SIGNAL ;
    PORT
      LAYER Metal3 ;
        RECT  0 447.94 0.4 448.34 ;
    END
  END push_block_i[231]
  PIN push_block_i[232]
    DIRECTION INPUT ;
    USE SIGNAL ;
    PORT
      LAYER Metal3 ;
        RECT  0 449.62 0.4 450.02 ;
    END
  END push_block_i[232]
  PIN push_block_i[233]
    DIRECTION INPUT ;
    USE SIGNAL ;
    PORT
      LAYER Metal3 ;
        RECT  0 451.3 0.4 451.7 ;
    END
  END push_block_i[233]
  PIN push_block_i[234]
    DIRECTION INPUT ;
    USE SIGNAL ;
    PORT
      LAYER Metal3 ;
        RECT  0 452.98 0.4 453.38 ;
    END
  END push_block_i[234]
  PIN push_block_i[235]
    DIRECTION INPUT ;
    USE SIGNAL ;
    PORT
      LAYER Metal3 ;
        RECT  0 454.66 0.4 455.06 ;
    END
  END push_block_i[235]
  PIN push_block_i[236]
    DIRECTION INPUT ;
    USE SIGNAL ;
    PORT
      LAYER Metal3 ;
        RECT  0 456.34 0.4 456.74 ;
    END
  END push_block_i[236]
  PIN push_block_i[237]
    DIRECTION INPUT ;
    USE SIGNAL ;
    PORT
      LAYER Metal3 ;
        RECT  0 458.02 0.4 458.42 ;
    END
  END push_block_i[237]
  PIN push_block_i[238]
    DIRECTION INPUT ;
    USE SIGNAL ;
    PORT
      LAYER Metal3 ;
        RECT  0 459.7 0.4 460.1 ;
    END
  END push_block_i[238]
  PIN push_block_i[239]
    DIRECTION INPUT ;
    USE SIGNAL ;
    PORT
      LAYER Metal3 ;
        RECT  0 461.38 0.4 461.78 ;
    END
  END push_block_i[239]
  PIN push_block_i[23]
    DIRECTION INPUT ;
    USE SIGNAL ;
    PORT
      LAYER Metal3 ;
        RECT  0 98.5 0.4 98.9 ;
    END
  END push_block_i[23]
  PIN push_block_i[240]
    DIRECTION INPUT ;
    USE SIGNAL ;
    PORT
      LAYER Metal3 ;
        RECT  0 463.06 0.4 463.46 ;
    END
  END push_block_i[240]
  PIN push_block_i[241]
    DIRECTION INPUT ;
    USE SIGNAL ;
    PORT
      LAYER Metal3 ;
        RECT  0 464.74 0.4 465.14 ;
    END
  END push_block_i[241]
  PIN push_block_i[242]
    DIRECTION INPUT ;
    USE SIGNAL ;
    PORT
      LAYER Metal3 ;
        RECT  0 466.42 0.4 466.82 ;
    END
  END push_block_i[242]
  PIN push_block_i[243]
    DIRECTION INPUT ;
    USE SIGNAL ;
    PORT
      LAYER Metal3 ;
        RECT  0 468.1 0.4 468.5 ;
    END
  END push_block_i[243]
  PIN push_block_i[244]
    DIRECTION INPUT ;
    USE SIGNAL ;
    PORT
      LAYER Metal3 ;
        RECT  0 469.78 0.4 470.18 ;
    END
  END push_block_i[244]
  PIN push_block_i[245]
    DIRECTION INPUT ;
    USE SIGNAL ;
    PORT
      LAYER Metal3 ;
        RECT  0 471.46 0.4 471.86 ;
    END
  END push_block_i[245]
  PIN push_block_i[246]
    DIRECTION INPUT ;
    USE SIGNAL ;
    PORT
      LAYER Metal3 ;
        RECT  0 473.14 0.4 473.54 ;
    END
  END push_block_i[246]
  PIN push_block_i[247]
    DIRECTION INPUT ;
    USE SIGNAL ;
    PORT
      LAYER Metal3 ;
        RECT  0 474.82 0.4 475.22 ;
    END
  END push_block_i[247]
  PIN push_block_i[248]
    DIRECTION INPUT ;
    USE SIGNAL ;
    PORT
      LAYER Metal3 ;
        RECT  0 476.5 0.4 476.9 ;
    END
  END push_block_i[248]
  PIN push_block_i[249]
    DIRECTION INPUT ;
    USE SIGNAL ;
    PORT
      LAYER Metal3 ;
        RECT  0 478.18 0.4 478.58 ;
    END
  END push_block_i[249]
  PIN push_block_i[24]
    DIRECTION INPUT ;
    USE SIGNAL ;
    PORT
      LAYER Metal3 ;
        RECT  0 100.18 0.4 100.58 ;
    END
  END push_block_i[24]
  PIN push_block_i[250]
    DIRECTION INPUT ;
    USE SIGNAL ;
    PORT
      LAYER Metal3 ;
        RECT  0 479.86 0.4 480.26 ;
    END
  END push_block_i[250]
  PIN push_block_i[251]
    DIRECTION INPUT ;
    USE SIGNAL ;
    PORT
      LAYER Metal3 ;
        RECT  0 481.54 0.4 481.94 ;
    END
  END push_block_i[251]
  PIN push_block_i[252]
    DIRECTION INPUT ;
    USE SIGNAL ;
    PORT
      LAYER Metal3 ;
        RECT  0 483.22 0.4 483.62 ;
    END
  END push_block_i[252]
  PIN push_block_i[253]
    DIRECTION INPUT ;
    USE SIGNAL ;
    PORT
      LAYER Metal3 ;
        RECT  0 484.9 0.4 485.3 ;
    END
  END push_block_i[253]
  PIN push_block_i[254]
    DIRECTION INPUT ;
    USE SIGNAL ;
    PORT
      LAYER Metal3 ;
        RECT  0 486.58 0.4 486.98 ;
    END
  END push_block_i[254]
  PIN push_block_i[255]
    DIRECTION INPUT ;
    USE SIGNAL ;
    PORT
      LAYER Metal3 ;
        RECT  0 488.26 0.4 488.66 ;
    END
  END push_block_i[255]
  PIN push_block_i[256]
    DIRECTION INPUT ;
    USE SIGNAL ;
    PORT
      LAYER Metal3 ;
        RECT  0 489.94 0.4 490.34 ;
    END
  END push_block_i[256]
  PIN push_block_i[257]
    DIRECTION INPUT ;
    USE SIGNAL ;
    PORT
      LAYER Metal3 ;
        RECT  0 491.62 0.4 492.02 ;
    END
  END push_block_i[257]
  PIN push_block_i[258]
    DIRECTION INPUT ;
    USE SIGNAL ;
    PORT
      LAYER Metal3 ;
        RECT  0 493.3 0.4 493.7 ;
    END
  END push_block_i[258]
  PIN push_block_i[259]
    DIRECTION INPUT ;
    USE SIGNAL ;
    PORT
      LAYER Metal3 ;
        RECT  0 494.98 0.4 495.38 ;
    END
  END push_block_i[259]
  PIN push_block_i[25]
    DIRECTION INPUT ;
    USE SIGNAL ;
    PORT
      LAYER Metal3 ;
        RECT  0 101.86 0.4 102.26 ;
    END
  END push_block_i[25]
  PIN push_block_i[260]
    DIRECTION INPUT ;
    USE SIGNAL ;
    PORT
      LAYER Metal3 ;
        RECT  0 496.66 0.4 497.06 ;
    END
  END push_block_i[260]
  PIN push_block_i[261]
    DIRECTION INPUT ;
    USE SIGNAL ;
    PORT
      LAYER Metal3 ;
        RECT  0 498.34 0.4 498.74 ;
    END
  END push_block_i[261]
  PIN push_block_i[262]
    DIRECTION INPUT ;
    USE SIGNAL ;
    PORT
      LAYER Metal3 ;
        RECT  0 500.02 0.4 500.42 ;
    END
  END push_block_i[262]
  PIN push_block_i[263]
    DIRECTION INPUT ;
    USE SIGNAL ;
    PORT
      LAYER Metal3 ;
        RECT  0 501.7 0.4 502.1 ;
    END
  END push_block_i[263]
  PIN push_block_i[264]
    DIRECTION INPUT ;
    USE SIGNAL ;
    PORT
      LAYER Metal3 ;
        RECT  0 503.38 0.4 503.78 ;
    END
  END push_block_i[264]
  PIN push_block_i[265]
    DIRECTION INPUT ;
    USE SIGNAL ;
    PORT
      LAYER Metal3 ;
        RECT  0 505.06 0.4 505.46 ;
    END
  END push_block_i[265]
  PIN push_block_i[266]
    DIRECTION INPUT ;
    USE SIGNAL ;
    PORT
      LAYER Metal3 ;
        RECT  0 506.74 0.4 507.14 ;
    END
  END push_block_i[266]
  PIN push_block_i[267]
    DIRECTION INPUT ;
    USE SIGNAL ;
    PORT
      LAYER Metal3 ;
        RECT  0 508.42 0.4 508.82 ;
    END
  END push_block_i[267]
  PIN push_block_i[268]
    DIRECTION INPUT ;
    USE SIGNAL ;
    PORT
      LAYER Metal3 ;
        RECT  0 510.1 0.4 510.5 ;
    END
  END push_block_i[268]
  PIN push_block_i[269]
    DIRECTION INPUT ;
    USE SIGNAL ;
    PORT
      LAYER Metal3 ;
        RECT  0 511.78 0.4 512.18 ;
    END
  END push_block_i[269]
  PIN push_block_i[26]
    DIRECTION INPUT ;
    USE SIGNAL ;
    PORT
      LAYER Metal3 ;
        RECT  0 103.54 0.4 103.94 ;
    END
  END push_block_i[26]
  PIN push_block_i[270]
    DIRECTION INPUT ;
    USE SIGNAL ;
    PORT
      LAYER Metal3 ;
        RECT  0 513.46 0.4 513.86 ;
    END
  END push_block_i[270]
  PIN push_block_i[271]
    DIRECTION INPUT ;
    USE SIGNAL ;
    PORT
      LAYER Metal3 ;
        RECT  0 515.14 0.4 515.54 ;
    END
  END push_block_i[271]
  PIN push_block_i[272]
    DIRECTION INPUT ;
    USE SIGNAL ;
    PORT
      LAYER Metal3 ;
        RECT  0 516.82 0.4 517.22 ;
    END
  END push_block_i[272]
  PIN push_block_i[273]
    DIRECTION INPUT ;
    USE SIGNAL ;
    PORT
      LAYER Metal3 ;
        RECT  0 518.5 0.4 518.9 ;
    END
  END push_block_i[273]
  PIN push_block_i[274]
    DIRECTION INPUT ;
    USE SIGNAL ;
    PORT
      LAYER Metal3 ;
        RECT  0 520.18 0.4 520.58 ;
    END
  END push_block_i[274]
  PIN push_block_i[275]
    DIRECTION INPUT ;
    USE SIGNAL ;
    PORT
      LAYER Metal3 ;
        RECT  0 521.86 0.4 522.26 ;
    END
  END push_block_i[275]
  PIN push_block_i[276]
    DIRECTION INPUT ;
    USE SIGNAL ;
    PORT
      LAYER Metal3 ;
        RECT  0 523.54 0.4 523.94 ;
    END
  END push_block_i[276]
  PIN push_block_i[277]
    DIRECTION INPUT ;
    USE SIGNAL ;
    PORT
      LAYER Metal3 ;
        RECT  0 525.22 0.4 525.62 ;
    END
  END push_block_i[277]
  PIN push_block_i[278]
    DIRECTION INPUT ;
    USE SIGNAL ;
    PORT
      LAYER Metal3 ;
        RECT  0 526.9 0.4 527.3 ;
    END
  END push_block_i[278]
  PIN push_block_i[279]
    DIRECTION INPUT ;
    USE SIGNAL ;
    PORT
      LAYER Metal3 ;
        RECT  0 528.58 0.4 528.98 ;
    END
  END push_block_i[279]
  PIN push_block_i[27]
    DIRECTION INPUT ;
    USE SIGNAL ;
    PORT
      LAYER Metal3 ;
        RECT  0 105.22 0.4 105.62 ;
    END
  END push_block_i[27]
  PIN push_block_i[280]
    DIRECTION INPUT ;
    USE SIGNAL ;
    PORT
      LAYER Metal3 ;
        RECT  0 530.26 0.4 530.66 ;
    END
  END push_block_i[280]
  PIN push_block_i[281]
    DIRECTION INPUT ;
    USE SIGNAL ;
    PORT
      LAYER Metal3 ;
        RECT  0 531.94 0.4 532.34 ;
    END
  END push_block_i[281]
  PIN push_block_i[282]
    DIRECTION INPUT ;
    USE SIGNAL ;
    PORT
      LAYER Metal3 ;
        RECT  0 533.62 0.4 534.02 ;
    END
  END push_block_i[282]
  PIN push_block_i[283]
    DIRECTION INPUT ;
    USE SIGNAL ;
    PORT
      LAYER Metal3 ;
        RECT  0 535.3 0.4 535.7 ;
    END
  END push_block_i[283]
  PIN push_block_i[284]
    DIRECTION INPUT ;
    USE SIGNAL ;
    PORT
      LAYER Metal3 ;
        RECT  0 536.98 0.4 537.38 ;
    END
  END push_block_i[284]
  PIN push_block_i[285]
    DIRECTION INPUT ;
    USE SIGNAL ;
    PORT
      LAYER Metal3 ;
        RECT  0 538.66 0.4 539.06 ;
    END
  END push_block_i[285]
  PIN push_block_i[286]
    DIRECTION INPUT ;
    USE SIGNAL ;
    PORT
      LAYER Metal3 ;
        RECT  0 540.34 0.4 540.74 ;
    END
  END push_block_i[286]
  PIN push_block_i[287]
    DIRECTION INPUT ;
    USE SIGNAL ;
    PORT
      LAYER Metal3 ;
        RECT  0 542.02 0.4 542.42 ;
    END
  END push_block_i[287]
  PIN push_block_i[288]
    DIRECTION INPUT ;
    USE SIGNAL ;
    PORT
      LAYER Metal3 ;
        RECT  0 543.7 0.4 544.1 ;
    END
  END push_block_i[288]
  PIN push_block_i[289]
    DIRECTION INPUT ;
    USE SIGNAL ;
    PORT
      LAYER Metal3 ;
        RECT  0 545.38 0.4 545.78 ;
    END
  END push_block_i[289]
  PIN push_block_i[28]
    DIRECTION INPUT ;
    USE SIGNAL ;
    PORT
      LAYER Metal3 ;
        RECT  0 106.9 0.4 107.3 ;
    END
  END push_block_i[28]
  PIN push_block_i[290]
    DIRECTION INPUT ;
    USE SIGNAL ;
    PORT
      LAYER Metal3 ;
        RECT  0 547.06 0.4 547.46 ;
    END
  END push_block_i[290]
  PIN push_block_i[291]
    DIRECTION INPUT ;
    USE SIGNAL ;
    PORT
      LAYER Metal3 ;
        RECT  0 548.74 0.4 549.14 ;
    END
  END push_block_i[291]
  PIN push_block_i[292]
    DIRECTION INPUT ;
    USE SIGNAL ;
    PORT
      LAYER Metal3 ;
        RECT  0 550.42 0.4 550.82 ;
    END
  END push_block_i[292]
  PIN push_block_i[293]
    DIRECTION INPUT ;
    USE SIGNAL ;
    PORT
      LAYER Metal3 ;
        RECT  0 552.1 0.4 552.5 ;
    END
  END push_block_i[293]
  PIN push_block_i[294]
    DIRECTION INPUT ;
    USE SIGNAL ;
    PORT
      LAYER Metal3 ;
        RECT  0 553.78 0.4 554.18 ;
    END
  END push_block_i[294]
  PIN push_block_i[295]
    DIRECTION INPUT ;
    USE SIGNAL ;
    PORT
      LAYER Metal3 ;
        RECT  0 555.46 0.4 555.86 ;
    END
  END push_block_i[295]
  PIN push_block_i[296]
    DIRECTION INPUT ;
    USE SIGNAL ;
    PORT
      LAYER Metal3 ;
        RECT  0 557.14 0.4 557.54 ;
    END
  END push_block_i[296]
  PIN push_block_i[297]
    DIRECTION INPUT ;
    USE SIGNAL ;
    PORT
      LAYER Metal3 ;
        RECT  0 558.82 0.4 559.22 ;
    END
  END push_block_i[297]
  PIN push_block_i[298]
    DIRECTION INPUT ;
    USE SIGNAL ;
    PORT
      LAYER Metal3 ;
        RECT  0 560.5 0.4 560.9 ;
    END
  END push_block_i[298]
  PIN push_block_i[299]
    DIRECTION INPUT ;
    USE SIGNAL ;
    PORT
      LAYER Metal3 ;
        RECT  0 562.18 0.4 562.58 ;
    END
  END push_block_i[299]
  PIN push_block_i[29]
    DIRECTION INPUT ;
    USE SIGNAL ;
    PORT
      LAYER Metal3 ;
        RECT  0 108.58 0.4 108.98 ;
    END
  END push_block_i[29]
  PIN push_block_i[2]
    DIRECTION INPUT ;
    USE SIGNAL ;
    PORT
      LAYER Metal3 ;
        RECT  0 63.22 0.4 63.62 ;
    END
  END push_block_i[2]
  PIN push_block_i[300]
    DIRECTION INPUT ;
    USE SIGNAL ;
    PORT
      LAYER Metal3 ;
        RECT  0 563.86 0.4 564.26 ;
    END
  END push_block_i[300]
  PIN push_block_i[301]
    DIRECTION INPUT ;
    USE SIGNAL ;
    PORT
      LAYER Metal3 ;
        RECT  0 565.54 0.4 565.94 ;
    END
  END push_block_i[301]
  PIN push_block_i[302]
    DIRECTION INPUT ;
    USE SIGNAL ;
    PORT
      LAYER Metal3 ;
        RECT  0 567.22 0.4 567.62 ;
    END
  END push_block_i[302]
  PIN push_block_i[303]
    DIRECTION INPUT ;
    USE SIGNAL ;
    PORT
      LAYER Metal3 ;
        RECT  0 568.9 0.4 569.3 ;
    END
  END push_block_i[303]
  PIN push_block_i[304]
    DIRECTION INPUT ;
    USE SIGNAL ;
    PORT
      LAYER Metal3 ;
        RECT  0 570.58 0.4 570.98 ;
    END
  END push_block_i[304]
  PIN push_block_i[305]
    DIRECTION INPUT ;
    USE SIGNAL ;
    PORT
      LAYER Metal3 ;
        RECT  0 572.26 0.4 572.66 ;
    END
  END push_block_i[305]
  PIN push_block_i[306]
    DIRECTION INPUT ;
    USE SIGNAL ;
    PORT
      LAYER Metal3 ;
        RECT  0 573.94 0.4 574.34 ;
    END
  END push_block_i[306]
  PIN push_block_i[307]
    DIRECTION INPUT ;
    USE SIGNAL ;
    PORT
      LAYER Metal3 ;
        RECT  0 575.62 0.4 576.02 ;
    END
  END push_block_i[307]
  PIN push_block_i[308]
    DIRECTION INPUT ;
    USE SIGNAL ;
    PORT
      LAYER Metal3 ;
        RECT  0 577.3 0.4 577.7 ;
    END
  END push_block_i[308]
  PIN push_block_i[309]
    DIRECTION INPUT ;
    USE SIGNAL ;
    PORT
      LAYER Metal3 ;
        RECT  0 578.98 0.4 579.38 ;
    END
  END push_block_i[309]
  PIN push_block_i[30]
    DIRECTION INPUT ;
    USE SIGNAL ;
    PORT
      LAYER Metal3 ;
        RECT  0 110.26 0.4 110.66 ;
    END
  END push_block_i[30]
  PIN push_block_i[310]
    DIRECTION INPUT ;
    USE SIGNAL ;
    PORT
      LAYER Metal3 ;
        RECT  0 580.66 0.4 581.06 ;
    END
  END push_block_i[310]
  PIN push_block_i[311]
    DIRECTION INPUT ;
    USE SIGNAL ;
    PORT
      LAYER Metal3 ;
        RECT  0 582.34 0.4 582.74 ;
    END
  END push_block_i[311]
  PIN push_block_i[312]
    DIRECTION INPUT ;
    USE SIGNAL ;
    PORT
      LAYER Metal3 ;
        RECT  0 584.02 0.4 584.42 ;
    END
  END push_block_i[312]
  PIN push_block_i[313]
    DIRECTION INPUT ;
    USE SIGNAL ;
    PORT
      LAYER Metal3 ;
        RECT  0 585.7 0.4 586.1 ;
    END
  END push_block_i[313]
  PIN push_block_i[314]
    DIRECTION INPUT ;
    USE SIGNAL ;
    PORT
      LAYER Metal3 ;
        RECT  0 587.38 0.4 587.78 ;
    END
  END push_block_i[314]
  PIN push_block_i[315]
    DIRECTION INPUT ;
    USE SIGNAL ;
    PORT
      LAYER Metal3 ;
        RECT  0 589.06 0.4 589.46 ;
    END
  END push_block_i[315]
  PIN push_block_i[316]
    DIRECTION INPUT ;
    USE SIGNAL ;
    PORT
      LAYER Metal3 ;
        RECT  0 590.74 0.4 591.14 ;
    END
  END push_block_i[316]
  PIN push_block_i[317]
    DIRECTION INPUT ;
    USE SIGNAL ;
    PORT
      LAYER Metal3 ;
        RECT  0 592.42 0.4 592.82 ;
    END
  END push_block_i[317]
  PIN push_block_i[318]
    DIRECTION INPUT ;
    USE SIGNAL ;
    PORT
      LAYER Metal3 ;
        RECT  0 594.1 0.4 594.5 ;
    END
  END push_block_i[318]
  PIN push_block_i[319]
    DIRECTION INPUT ;
    USE SIGNAL ;
    PORT
      LAYER Metal3 ;
        RECT  0 595.78 0.4 596.18 ;
    END
  END push_block_i[319]
  PIN push_block_i[31]
    DIRECTION INPUT ;
    USE SIGNAL ;
    PORT
      LAYER Metal3 ;
        RECT  0 111.94 0.4 112.34 ;
    END
  END push_block_i[31]
  PIN push_block_i[320]
    DIRECTION INPUT ;
    USE SIGNAL ;
    PORT
      LAYER Metal3 ;
        RECT  0 597.46 0.4 597.86 ;
    END
  END push_block_i[320]
  PIN push_block_i[321]
    DIRECTION INPUT ;
    USE SIGNAL ;
    PORT
      LAYER Metal3 ;
        RECT  0 599.14 0.4 599.54 ;
    END
  END push_block_i[321]
  PIN push_block_i[322]
    DIRECTION INPUT ;
    USE SIGNAL ;
    PORT
      LAYER Metal3 ;
        RECT  0 600.82 0.4 601.22 ;
    END
  END push_block_i[322]
  PIN push_block_i[323]
    DIRECTION INPUT ;
    USE SIGNAL ;
    PORT
      LAYER Metal3 ;
        RECT  0 602.5 0.4 602.9 ;
    END
  END push_block_i[323]
  PIN push_block_i[324]
    DIRECTION INPUT ;
    USE SIGNAL ;
    PORT
      LAYER Metal3 ;
        RECT  0 604.18 0.4 604.58 ;
    END
  END push_block_i[324]
  PIN push_block_i[325]
    DIRECTION INPUT ;
    USE SIGNAL ;
    PORT
      LAYER Metal3 ;
        RECT  0 605.86 0.4 606.26 ;
    END
  END push_block_i[325]
  PIN push_block_i[326]
    DIRECTION INPUT ;
    USE SIGNAL ;
    PORT
      LAYER Metal3 ;
        RECT  0 607.54 0.4 607.94 ;
    END
  END push_block_i[326]
  PIN push_block_i[327]
    DIRECTION INPUT ;
    USE SIGNAL ;
    PORT
      LAYER Metal3 ;
        RECT  0 609.22 0.4 609.62 ;
    END
  END push_block_i[327]
  PIN push_block_i[328]
    DIRECTION INPUT ;
    USE SIGNAL ;
    PORT
      LAYER Metal3 ;
        RECT  0 610.9 0.4 611.3 ;
    END
  END push_block_i[328]
  PIN push_block_i[329]
    DIRECTION INPUT ;
    USE SIGNAL ;
    PORT
      LAYER Metal3 ;
        RECT  0 612.58 0.4 612.98 ;
    END
  END push_block_i[329]
  PIN push_block_i[32]
    DIRECTION INPUT ;
    USE SIGNAL ;
    PORT
      LAYER Metal3 ;
        RECT  0 113.62 0.4 114.02 ;
    END
  END push_block_i[32]
  PIN push_block_i[330]
    DIRECTION INPUT ;
    USE SIGNAL ;
    PORT
      LAYER Metal3 ;
        RECT  0 614.26 0.4 614.66 ;
    END
  END push_block_i[330]
  PIN push_block_i[331]
    DIRECTION INPUT ;
    USE SIGNAL ;
    PORT
      LAYER Metal3 ;
        RECT  0 615.94 0.4 616.34 ;
    END
  END push_block_i[331]
  PIN push_block_i[332]
    DIRECTION INPUT ;
    USE SIGNAL ;
    PORT
      LAYER Metal3 ;
        RECT  0 617.62 0.4 618.02 ;
    END
  END push_block_i[332]
  PIN push_block_i[333]
    DIRECTION INPUT ;
    USE SIGNAL ;
    PORT
      LAYER Metal3 ;
        RECT  0 619.3 0.4 619.7 ;
    END
  END push_block_i[333]
  PIN push_block_i[334]
    DIRECTION INPUT ;
    USE SIGNAL ;
    PORT
      LAYER Metal3 ;
        RECT  0 620.98 0.4 621.38 ;
    END
  END push_block_i[334]
  PIN push_block_i[335]
    DIRECTION INPUT ;
    USE SIGNAL ;
    PORT
      LAYER Metal3 ;
        RECT  0 622.66 0.4 623.06 ;
    END
  END push_block_i[335]
  PIN push_block_i[336]
    DIRECTION INPUT ;
    USE SIGNAL ;
    PORT
      LAYER Metal3 ;
        RECT  0 624.34 0.4 624.74 ;
    END
  END push_block_i[336]
  PIN push_block_i[337]
    DIRECTION INPUT ;
    USE SIGNAL ;
    PORT
      LAYER Metal3 ;
        RECT  0 626.02 0.4 626.42 ;
    END
  END push_block_i[337]
  PIN push_block_i[338]
    DIRECTION INPUT ;
    USE SIGNAL ;
    PORT
      LAYER Metal3 ;
        RECT  0 627.7 0.4 628.1 ;
    END
  END push_block_i[338]
  PIN push_block_i[339]
    DIRECTION INPUT ;
    USE SIGNAL ;
    PORT
      LAYER Metal3 ;
        RECT  0 629.38 0.4 629.78 ;
    END
  END push_block_i[339]
  PIN push_block_i[33]
    DIRECTION INPUT ;
    USE SIGNAL ;
    PORT
      LAYER Metal3 ;
        RECT  0 115.3 0.4 115.7 ;
    END
  END push_block_i[33]
  PIN push_block_i[340]
    DIRECTION INPUT ;
    USE SIGNAL ;
    PORT
      LAYER Metal3 ;
        RECT  0 631.06 0.4 631.46 ;
    END
  END push_block_i[340]
  PIN push_block_i[341]
    DIRECTION INPUT ;
    USE SIGNAL ;
    PORT
      LAYER Metal3 ;
        RECT  0 632.74 0.4 633.14 ;
    END
  END push_block_i[341]
  PIN push_block_i[342]
    DIRECTION INPUT ;
    USE SIGNAL ;
    PORT
      LAYER Metal3 ;
        RECT  0 634.42 0.4 634.82 ;
    END
  END push_block_i[342]
  PIN push_block_i[343]
    DIRECTION INPUT ;
    USE SIGNAL ;
    PORT
      LAYER Metal3 ;
        RECT  0 636.1 0.4 636.5 ;
    END
  END push_block_i[343]
  PIN push_block_i[344]
    DIRECTION INPUT ;
    USE SIGNAL ;
    PORT
      LAYER Metal3 ;
        RECT  0 637.78 0.4 638.18 ;
    END
  END push_block_i[344]
  PIN push_block_i[345]
    DIRECTION INPUT ;
    USE SIGNAL ;
    PORT
      LAYER Metal3 ;
        RECT  0 639.46 0.4 639.86 ;
    END
  END push_block_i[345]
  PIN push_block_i[346]
    DIRECTION INPUT ;
    USE SIGNAL ;
    PORT
      LAYER Metal3 ;
        RECT  0 641.14 0.4 641.54 ;
    END
  END push_block_i[346]
  PIN push_block_i[347]
    DIRECTION INPUT ;
    USE SIGNAL ;
    PORT
      LAYER Metal3 ;
        RECT  0 642.82 0.4 643.22 ;
    END
  END push_block_i[347]
  PIN push_block_i[348]
    DIRECTION INPUT ;
    USE SIGNAL ;
    PORT
      LAYER Metal3 ;
        RECT  0 644.5 0.4 644.9 ;
    END
  END push_block_i[348]
  PIN push_block_i[349]
    DIRECTION INPUT ;
    USE SIGNAL ;
    PORT
      LAYER Metal3 ;
        RECT  0 646.18 0.4 646.58 ;
    END
  END push_block_i[349]
  PIN push_block_i[34]
    DIRECTION INPUT ;
    USE SIGNAL ;
    PORT
      LAYER Metal3 ;
        RECT  0 116.98 0.4 117.38 ;
    END
  END push_block_i[34]
  PIN push_block_i[350]
    DIRECTION INPUT ;
    USE SIGNAL ;
    PORT
      LAYER Metal3 ;
        RECT  0 647.86 0.4 648.26 ;
    END
  END push_block_i[350]
  PIN push_block_i[351]
    DIRECTION INPUT ;
    USE SIGNAL ;
    PORT
      LAYER Metal3 ;
        RECT  0 649.54 0.4 649.94 ;
    END
  END push_block_i[351]
  PIN push_block_i[352]
    DIRECTION INPUT ;
    USE SIGNAL ;
    PORT
      LAYER Metal3 ;
        RECT  0 651.22 0.4 651.62 ;
    END
  END push_block_i[352]
  PIN push_block_i[353]
    DIRECTION INPUT ;
    USE SIGNAL ;
    PORT
      LAYER Metal3 ;
        RECT  0 652.9 0.4 653.3 ;
    END
  END push_block_i[353]
  PIN push_block_i[354]
    DIRECTION INPUT ;
    USE SIGNAL ;
    PORT
      LAYER Metal3 ;
        RECT  0 654.58 0.4 654.98 ;
    END
  END push_block_i[354]
  PIN push_block_i[355]
    DIRECTION INPUT ;
    USE SIGNAL ;
    PORT
      LAYER Metal3 ;
        RECT  0 656.26 0.4 656.66 ;
    END
  END push_block_i[355]
  PIN push_block_i[356]
    DIRECTION INPUT ;
    USE SIGNAL ;
    PORT
      LAYER Metal3 ;
        RECT  0 657.94 0.4 658.34 ;
    END
  END push_block_i[356]
  PIN push_block_i[357]
    DIRECTION INPUT ;
    USE SIGNAL ;
    PORT
      LAYER Metal3 ;
        RECT  0 659.62 0.4 660.02 ;
    END
  END push_block_i[357]
  PIN push_block_i[358]
    DIRECTION INPUT ;
    USE SIGNAL ;
    PORT
      LAYER Metal3 ;
        RECT  0 661.3 0.4 661.7 ;
    END
  END push_block_i[358]
  PIN push_block_i[359]
    DIRECTION INPUT ;
    USE SIGNAL ;
    PORT
      LAYER Metal3 ;
        RECT  0 662.98 0.4 663.38 ;
    END
  END push_block_i[359]
  PIN push_block_i[35]
    DIRECTION INPUT ;
    USE SIGNAL ;
    PORT
      LAYER Metal3 ;
        RECT  0 118.66 0.4 119.06 ;
    END
  END push_block_i[35]
  PIN push_block_i[360]
    DIRECTION INPUT ;
    USE SIGNAL ;
    PORT
      LAYER Metal3 ;
        RECT  0 664.66 0.4 665.06 ;
    END
  END push_block_i[360]
  PIN push_block_i[361]
    DIRECTION INPUT ;
    USE SIGNAL ;
    PORT
      LAYER Metal3 ;
        RECT  0 666.34 0.4 666.74 ;
    END
  END push_block_i[361]
  PIN push_block_i[362]
    DIRECTION INPUT ;
    USE SIGNAL ;
    PORT
      LAYER Metal3 ;
        RECT  0 668.02 0.4 668.42 ;
    END
  END push_block_i[362]
  PIN push_block_i[363]
    DIRECTION INPUT ;
    USE SIGNAL ;
    PORT
      LAYER Metal3 ;
        RECT  0 669.7 0.4 670.1 ;
    END
  END push_block_i[363]
  PIN push_block_i[364]
    DIRECTION INPUT ;
    USE SIGNAL ;
    PORT
      LAYER Metal3 ;
        RECT  0 671.38 0.4 671.78 ;
    END
  END push_block_i[364]
  PIN push_block_i[365]
    DIRECTION INPUT ;
    USE SIGNAL ;
    PORT
      LAYER Metal3 ;
        RECT  0 673.06 0.4 673.46 ;
    END
  END push_block_i[365]
  PIN push_block_i[366]
    DIRECTION INPUT ;
    USE SIGNAL ;
    PORT
      LAYER Metal3 ;
        RECT  0 674.74 0.4 675.14 ;
    END
  END push_block_i[366]
  PIN push_block_i[367]
    DIRECTION INPUT ;
    USE SIGNAL ;
    PORT
      LAYER Metal3 ;
        RECT  0 676.42 0.4 676.82 ;
    END
  END push_block_i[367]
  PIN push_block_i[368]
    DIRECTION INPUT ;
    USE SIGNAL ;
    PORT
      LAYER Metal3 ;
        RECT  0 678.1 0.4 678.5 ;
    END
  END push_block_i[368]
  PIN push_block_i[369]
    DIRECTION INPUT ;
    USE SIGNAL ;
    PORT
      LAYER Metal3 ;
        RECT  0 679.78 0.4 680.18 ;
    END
  END push_block_i[369]
  PIN push_block_i[36]
    DIRECTION INPUT ;
    USE SIGNAL ;
    PORT
      LAYER Metal3 ;
        RECT  0 120.34 0.4 120.74 ;
    END
  END push_block_i[36]
  PIN push_block_i[370]
    DIRECTION INPUT ;
    USE SIGNAL ;
    PORT
      LAYER Metal3 ;
        RECT  0 681.46 0.4 681.86 ;
    END
  END push_block_i[370]
  PIN push_block_i[371]
    DIRECTION INPUT ;
    USE SIGNAL ;
    PORT
      LAYER Metal3 ;
        RECT  0 683.14 0.4 683.54 ;
    END
  END push_block_i[371]
  PIN push_block_i[372]
    DIRECTION INPUT ;
    USE SIGNAL ;
    PORT
      LAYER Metal3 ;
        RECT  0 684.82 0.4 685.22 ;
    END
  END push_block_i[372]
  PIN push_block_i[373]
    DIRECTION INPUT ;
    USE SIGNAL ;
    PORT
      LAYER Metal3 ;
        RECT  0 686.5 0.4 686.9 ;
    END
  END push_block_i[373]
  PIN push_block_i[374]
    DIRECTION INPUT ;
    USE SIGNAL ;
    PORT
      LAYER Metal3 ;
        RECT  0 688.18 0.4 688.58 ;
    END
  END push_block_i[374]
  PIN push_block_i[375]
    DIRECTION INPUT ;
    USE SIGNAL ;
    PORT
      LAYER Metal3 ;
        RECT  0 689.86 0.4 690.26 ;
    END
  END push_block_i[375]
  PIN push_block_i[376]
    DIRECTION INPUT ;
    USE SIGNAL ;
    PORT
      LAYER Metal3 ;
        RECT  0 691.54 0.4 691.94 ;
    END
  END push_block_i[376]
  PIN push_block_i[377]
    DIRECTION INPUT ;
    USE SIGNAL ;
    PORT
      LAYER Metal3 ;
        RECT  0 693.22 0.4 693.62 ;
    END
  END push_block_i[377]
  PIN push_block_i[378]
    DIRECTION INPUT ;
    USE SIGNAL ;
    PORT
      LAYER Metal3 ;
        RECT  0 694.9 0.4 695.3 ;
    END
  END push_block_i[378]
  PIN push_block_i[379]
    DIRECTION INPUT ;
    USE SIGNAL ;
    PORT
      LAYER Metal3 ;
        RECT  0 696.58 0.4 696.98 ;
    END
  END push_block_i[379]
  PIN push_block_i[37]
    DIRECTION INPUT ;
    USE SIGNAL ;
    PORT
      LAYER Metal3 ;
        RECT  0 122.02 0.4 122.42 ;
    END
  END push_block_i[37]
  PIN push_block_i[380]
    DIRECTION INPUT ;
    USE SIGNAL ;
    PORT
      LAYER Metal3 ;
        RECT  0 698.26 0.4 698.66 ;
    END
  END push_block_i[380]
  PIN push_block_i[381]
    DIRECTION INPUT ;
    USE SIGNAL ;
    PORT
      LAYER Metal3 ;
        RECT  0 699.94 0.4 700.34 ;
    END
  END push_block_i[381]
  PIN push_block_i[382]
    DIRECTION INPUT ;
    USE SIGNAL ;
    PORT
      LAYER Metal3 ;
        RECT  0 701.62 0.4 702.02 ;
    END
  END push_block_i[382]
  PIN push_block_i[383]
    DIRECTION INPUT ;
    USE SIGNAL ;
    PORT
      LAYER Metal3 ;
        RECT  0 703.3 0.4 703.7 ;
    END
  END push_block_i[383]
  PIN push_block_i[384]
    DIRECTION INPUT ;
    USE SIGNAL ;
    PORT
      LAYER Metal3 ;
        RECT  0 704.98 0.4 705.38 ;
    END
  END push_block_i[384]
  PIN push_block_i[385]
    DIRECTION INPUT ;
    USE SIGNAL ;
    PORT
      LAYER Metal3 ;
        RECT  0 706.66 0.4 707.06 ;
    END
  END push_block_i[385]
  PIN push_block_i[386]
    DIRECTION INPUT ;
    USE SIGNAL ;
    PORT
      LAYER Metal3 ;
        RECT  0 708.34 0.4 708.74 ;
    END
  END push_block_i[386]
  PIN push_block_i[387]
    DIRECTION INPUT ;
    USE SIGNAL ;
    PORT
      LAYER Metal3 ;
        RECT  0 710.02 0.4 710.42 ;
    END
  END push_block_i[387]
  PIN push_block_i[388]
    DIRECTION INPUT ;
    USE SIGNAL ;
    PORT
      LAYER Metal3 ;
        RECT  0 711.7 0.4 712.1 ;
    END
  END push_block_i[388]
  PIN push_block_i[389]
    DIRECTION INPUT ;
    USE SIGNAL ;
    PORT
      LAYER Metal3 ;
        RECT  0 713.38 0.4 713.78 ;
    END
  END push_block_i[389]
  PIN push_block_i[38]
    DIRECTION INPUT ;
    USE SIGNAL ;
    PORT
      LAYER Metal3 ;
        RECT  0 123.7 0.4 124.1 ;
    END
  END push_block_i[38]
  PIN push_block_i[390]
    DIRECTION INPUT ;
    USE SIGNAL ;
    PORT
      LAYER Metal3 ;
        RECT  0 715.06 0.4 715.46 ;
    END
  END push_block_i[390]
  PIN push_block_i[391]
    DIRECTION INPUT ;
    USE SIGNAL ;
    PORT
      LAYER Metal3 ;
        RECT  0 716.74 0.4 717.14 ;
    END
  END push_block_i[391]
  PIN push_block_i[392]
    DIRECTION INPUT ;
    USE SIGNAL ;
    PORT
      LAYER Metal3 ;
        RECT  0 718.42 0.4 718.82 ;
    END
  END push_block_i[392]
  PIN push_block_i[393]
    DIRECTION INPUT ;
    USE SIGNAL ;
    PORT
      LAYER Metal3 ;
        RECT  0 720.1 0.4 720.5 ;
    END
  END push_block_i[393]
  PIN push_block_i[394]
    DIRECTION INPUT ;
    USE SIGNAL ;
    PORT
      LAYER Metal3 ;
        RECT  0 721.78 0.4 722.18 ;
    END
  END push_block_i[394]
  PIN push_block_i[395]
    DIRECTION INPUT ;
    USE SIGNAL ;
    PORT
      LAYER Metal3 ;
        RECT  0 723.46 0.4 723.86 ;
    END
  END push_block_i[395]
  PIN push_block_i[396]
    DIRECTION INPUT ;
    USE SIGNAL ;
    PORT
      LAYER Metal3 ;
        RECT  0 725.14 0.4 725.54 ;
    END
  END push_block_i[396]
  PIN push_block_i[397]
    DIRECTION INPUT ;
    USE SIGNAL ;
    PORT
      LAYER Metal3 ;
        RECT  0 726.82 0.4 727.22 ;
    END
  END push_block_i[397]
  PIN push_block_i[398]
    DIRECTION INPUT ;
    USE SIGNAL ;
    PORT
      LAYER Metal3 ;
        RECT  0 728.5 0.4 728.9 ;
    END
  END push_block_i[398]
  PIN push_block_i[399]
    DIRECTION INPUT ;
    USE SIGNAL ;
    PORT
      LAYER Metal3 ;
        RECT  0 730.18 0.4 730.58 ;
    END
  END push_block_i[399]
  PIN push_block_i[39]
    DIRECTION INPUT ;
    USE SIGNAL ;
    PORT
      LAYER Metal3 ;
        RECT  0 125.38 0.4 125.78 ;
    END
  END push_block_i[39]
  PIN push_block_i[3]
    DIRECTION INPUT ;
    USE SIGNAL ;
    PORT
      LAYER Metal3 ;
        RECT  0 64.9 0.4 65.3 ;
    END
  END push_block_i[3]
  PIN push_block_i[400]
    DIRECTION INPUT ;
    USE SIGNAL ;
    PORT
      LAYER Metal3 ;
        RECT  0 731.86 0.4 732.26 ;
    END
  END push_block_i[400]
  PIN push_block_i[401]
    DIRECTION INPUT ;
    USE SIGNAL ;
    PORT
      LAYER Metal3 ;
        RECT  0 733.54 0.4 733.94 ;
    END
  END push_block_i[401]
  PIN push_block_i[402]
    DIRECTION INPUT ;
    USE SIGNAL ;
    PORT
      LAYER Metal3 ;
        RECT  0 735.22 0.4 735.62 ;
    END
  END push_block_i[402]
  PIN push_block_i[403]
    DIRECTION INPUT ;
    USE SIGNAL ;
    PORT
      LAYER Metal3 ;
        RECT  0 736.9 0.4 737.3 ;
    END
  END push_block_i[403]
  PIN push_block_i[404]
    DIRECTION INPUT ;
    USE SIGNAL ;
    PORT
      LAYER Metal3 ;
        RECT  0 738.58 0.4 738.98 ;
    END
  END push_block_i[404]
  PIN push_block_i[405]
    DIRECTION INPUT ;
    USE SIGNAL ;
    PORT
      LAYER Metal3 ;
        RECT  0 740.26 0.4 740.66 ;
    END
  END push_block_i[405]
  PIN push_block_i[406]
    DIRECTION INPUT ;
    USE SIGNAL ;
    PORT
      LAYER Metal3 ;
        RECT  0 741.94 0.4 742.34 ;
    END
  END push_block_i[406]
  PIN push_block_i[407]
    DIRECTION INPUT ;
    USE SIGNAL ;
    PORT
      LAYER Metal3 ;
        RECT  0 743.62 0.4 744.02 ;
    END
  END push_block_i[407]
  PIN push_block_i[408]
    DIRECTION INPUT ;
    USE SIGNAL ;
    PORT
      LAYER Metal3 ;
        RECT  0 745.3 0.4 745.7 ;
    END
  END push_block_i[408]
  PIN push_block_i[409]
    DIRECTION INPUT ;
    USE SIGNAL ;
    PORT
      LAYER Metal3 ;
        RECT  0 746.98 0.4 747.38 ;
    END
  END push_block_i[409]
  PIN push_block_i[40]
    DIRECTION INPUT ;
    USE SIGNAL ;
    PORT
      LAYER Metal3 ;
        RECT  0 127.06 0.4 127.46 ;
    END
  END push_block_i[40]
  PIN push_block_i[410]
    DIRECTION INPUT ;
    USE SIGNAL ;
    PORT
      LAYER Metal3 ;
        RECT  0 748.66 0.4 749.06 ;
    END
  END push_block_i[410]
  PIN push_block_i[411]
    DIRECTION INPUT ;
    USE SIGNAL ;
    PORT
      LAYER Metal3 ;
        RECT  0 750.34 0.4 750.74 ;
    END
  END push_block_i[411]
  PIN push_block_i[412]
    DIRECTION INPUT ;
    USE SIGNAL ;
    PORT
      LAYER Metal3 ;
        RECT  0 752.02 0.4 752.42 ;
    END
  END push_block_i[412]
  PIN push_block_i[413]
    DIRECTION INPUT ;
    USE SIGNAL ;
    PORT
      LAYER Metal3 ;
        RECT  0 753.7 0.4 754.1 ;
    END
  END push_block_i[413]
  PIN push_block_i[414]
    DIRECTION INPUT ;
    USE SIGNAL ;
    PORT
      LAYER Metal3 ;
        RECT  0 755.38 0.4 755.78 ;
    END
  END push_block_i[414]
  PIN push_block_i[415]
    DIRECTION INPUT ;
    USE SIGNAL ;
    PORT
      LAYER Metal3 ;
        RECT  0 757.06 0.4 757.46 ;
    END
  END push_block_i[415]
  PIN push_block_i[416]
    DIRECTION INPUT ;
    USE SIGNAL ;
    PORT
      LAYER Metal3 ;
        RECT  0 758.74 0.4 759.14 ;
    END
  END push_block_i[416]
  PIN push_block_i[417]
    DIRECTION INPUT ;
    USE SIGNAL ;
    PORT
      LAYER Metal3 ;
        RECT  0 760.42 0.4 760.82 ;
    END
  END push_block_i[417]
  PIN push_block_i[418]
    DIRECTION INPUT ;
    USE SIGNAL ;
    PORT
      LAYER Metal3 ;
        RECT  0 762.1 0.4 762.5 ;
    END
  END push_block_i[418]
  PIN push_block_i[419]
    DIRECTION INPUT ;
    USE SIGNAL ;
    PORT
      LAYER Metal3 ;
        RECT  0 763.78 0.4 764.18 ;
    END
  END push_block_i[419]
  PIN push_block_i[41]
    DIRECTION INPUT ;
    USE SIGNAL ;
    PORT
      LAYER Metal3 ;
        RECT  0 128.74 0.4 129.14 ;
    END
  END push_block_i[41]
  PIN push_block_i[420]
    DIRECTION INPUT ;
    USE SIGNAL ;
    PORT
      LAYER Metal3 ;
        RECT  0 765.46 0.4 765.86 ;
    END
  END push_block_i[420]
  PIN push_block_i[421]
    DIRECTION INPUT ;
    USE SIGNAL ;
    PORT
      LAYER Metal3 ;
        RECT  0 767.14 0.4 767.54 ;
    END
  END push_block_i[421]
  PIN push_block_i[422]
    DIRECTION INPUT ;
    USE SIGNAL ;
    PORT
      LAYER Metal3 ;
        RECT  0 768.82 0.4 769.22 ;
    END
  END push_block_i[422]
  PIN push_block_i[423]
    DIRECTION INPUT ;
    USE SIGNAL ;
    PORT
      LAYER Metal3 ;
        RECT  0 770.5 0.4 770.9 ;
    END
  END push_block_i[423]
  PIN push_block_i[424]
    DIRECTION INPUT ;
    USE SIGNAL ;
    PORT
      LAYER Metal3 ;
        RECT  0 772.18 0.4 772.58 ;
    END
  END push_block_i[424]
  PIN push_block_i[425]
    DIRECTION INPUT ;
    USE SIGNAL ;
    PORT
      LAYER Metal3 ;
        RECT  0 773.86 0.4 774.26 ;
    END
  END push_block_i[425]
  PIN push_block_i[426]
    DIRECTION INPUT ;
    USE SIGNAL ;
    PORT
      LAYER Metal3 ;
        RECT  0 775.54 0.4 775.94 ;
    END
  END push_block_i[426]
  PIN push_block_i[427]
    DIRECTION INPUT ;
    USE SIGNAL ;
    PORT
      LAYER Metal3 ;
        RECT  0 777.22 0.4 777.62 ;
    END
  END push_block_i[427]
  PIN push_block_i[428]
    DIRECTION INPUT ;
    USE SIGNAL ;
    PORT
      LAYER Metal3 ;
        RECT  0 778.9 0.4 779.3 ;
    END
  END push_block_i[428]
  PIN push_block_i[429]
    DIRECTION INPUT ;
    USE SIGNAL ;
    PORT
      LAYER Metal3 ;
        RECT  0 780.58 0.4 780.98 ;
    END
  END push_block_i[429]
  PIN push_block_i[42]
    DIRECTION INPUT ;
    USE SIGNAL ;
    PORT
      LAYER Metal3 ;
        RECT  0 130.42 0.4 130.82 ;
    END
  END push_block_i[42]
  PIN push_block_i[430]
    DIRECTION INPUT ;
    USE SIGNAL ;
    PORT
      LAYER Metal3 ;
        RECT  0 782.26 0.4 782.66 ;
    END
  END push_block_i[430]
  PIN push_block_i[431]
    DIRECTION INPUT ;
    USE SIGNAL ;
    PORT
      LAYER Metal3 ;
        RECT  0 783.94 0.4 784.34 ;
    END
  END push_block_i[431]
  PIN push_block_i[432]
    DIRECTION INPUT ;
    USE SIGNAL ;
    PORT
      LAYER Metal3 ;
        RECT  0 785.62 0.4 786.02 ;
    END
  END push_block_i[432]
  PIN push_block_i[433]
    DIRECTION INPUT ;
    USE SIGNAL ;
    PORT
      LAYER Metal3 ;
        RECT  0 787.3 0.4 787.7 ;
    END
  END push_block_i[433]
  PIN push_block_i[434]
    DIRECTION INPUT ;
    USE SIGNAL ;
    PORT
      LAYER Metal3 ;
        RECT  0 788.98 0.4 789.38 ;
    END
  END push_block_i[434]
  PIN push_block_i[435]
    DIRECTION INPUT ;
    USE SIGNAL ;
    PORT
      LAYER Metal3 ;
        RECT  0 790.66 0.4 791.06 ;
    END
  END push_block_i[435]
  PIN push_block_i[436]
    DIRECTION INPUT ;
    USE SIGNAL ;
    PORT
      LAYER Metal3 ;
        RECT  0 792.34 0.4 792.74 ;
    END
  END push_block_i[436]
  PIN push_block_i[437]
    DIRECTION INPUT ;
    USE SIGNAL ;
    PORT
      LAYER Metal3 ;
        RECT  0 794.02 0.4 794.42 ;
    END
  END push_block_i[437]
  PIN push_block_i[438]
    DIRECTION INPUT ;
    USE SIGNAL ;
    PORT
      LAYER Metal3 ;
        RECT  0 795.7 0.4 796.1 ;
    END
  END push_block_i[438]
  PIN push_block_i[439]
    DIRECTION INPUT ;
    USE SIGNAL ;
    PORT
      LAYER Metal3 ;
        RECT  0 797.38 0.4 797.78 ;
    END
  END push_block_i[439]
  PIN push_block_i[43]
    DIRECTION INPUT ;
    USE SIGNAL ;
    PORT
      LAYER Metal3 ;
        RECT  0 132.1 0.4 132.5 ;
    END
  END push_block_i[43]
  PIN push_block_i[440]
    DIRECTION INPUT ;
    USE SIGNAL ;
    PORT
      LAYER Metal3 ;
        RECT  0 799.06 0.4 799.46 ;
    END
  END push_block_i[440]
  PIN push_block_i[441]
    DIRECTION INPUT ;
    USE SIGNAL ;
    PORT
      LAYER Metal3 ;
        RECT  0 800.74 0.4 801.14 ;
    END
  END push_block_i[441]
  PIN push_block_i[442]
    DIRECTION INPUT ;
    USE SIGNAL ;
    PORT
      LAYER Metal3 ;
        RECT  0 802.42 0.4 802.82 ;
    END
  END push_block_i[442]
  PIN push_block_i[443]
    DIRECTION INPUT ;
    USE SIGNAL ;
    PORT
      LAYER Metal3 ;
        RECT  0 804.1 0.4 804.5 ;
    END
  END push_block_i[443]
  PIN push_block_i[444]
    DIRECTION INPUT ;
    USE SIGNAL ;
    PORT
      LAYER Metal3 ;
        RECT  0 805.78 0.4 806.18 ;
    END
  END push_block_i[444]
  PIN push_block_i[445]
    DIRECTION INPUT ;
    USE SIGNAL ;
    PORT
      LAYER Metal3 ;
        RECT  0 807.46 0.4 807.86 ;
    END
  END push_block_i[445]
  PIN push_block_i[446]
    DIRECTION INPUT ;
    USE SIGNAL ;
    PORT
      LAYER Metal3 ;
        RECT  0 809.14 0.4 809.54 ;
    END
  END push_block_i[446]
  PIN push_block_i[447]
    DIRECTION INPUT ;
    USE SIGNAL ;
    PORT
      LAYER Metal3 ;
        RECT  0 810.82 0.4 811.22 ;
    END
  END push_block_i[447]
  PIN push_block_i[448]
    DIRECTION INPUT ;
    USE SIGNAL ;
    PORT
      LAYER Metal3 ;
        RECT  0 812.5 0.4 812.9 ;
    END
  END push_block_i[448]
  PIN push_block_i[449]
    DIRECTION INPUT ;
    USE SIGNAL ;
    PORT
      LAYER Metal3 ;
        RECT  0 814.18 0.4 814.58 ;
    END
  END push_block_i[449]
  PIN push_block_i[44]
    DIRECTION INPUT ;
    USE SIGNAL ;
    PORT
      LAYER Metal3 ;
        RECT  0 133.78 0.4 134.18 ;
    END
  END push_block_i[44]
  PIN push_block_i[450]
    DIRECTION INPUT ;
    USE SIGNAL ;
    PORT
      LAYER Metal3 ;
        RECT  0 815.86 0.4 816.26 ;
    END
  END push_block_i[450]
  PIN push_block_i[451]
    DIRECTION INPUT ;
    USE SIGNAL ;
    PORT
      LAYER Metal3 ;
        RECT  0 817.54 0.4 817.94 ;
    END
  END push_block_i[451]
  PIN push_block_i[452]
    DIRECTION INPUT ;
    USE SIGNAL ;
    PORT
      LAYER Metal3 ;
        RECT  0 819.22 0.4 819.62 ;
    END
  END push_block_i[452]
  PIN push_block_i[453]
    DIRECTION INPUT ;
    USE SIGNAL ;
    PORT
      LAYER Metal3 ;
        RECT  0 820.9 0.4 821.3 ;
    END
  END push_block_i[453]
  PIN push_block_i[454]
    DIRECTION INPUT ;
    USE SIGNAL ;
    PORT
      LAYER Metal3 ;
        RECT  0 822.58 0.4 822.98 ;
    END
  END push_block_i[454]
  PIN push_block_i[455]
    DIRECTION INPUT ;
    USE SIGNAL ;
    PORT
      LAYER Metal3 ;
        RECT  0 824.26 0.4 824.66 ;
    END
  END push_block_i[455]
  PIN push_block_i[456]
    DIRECTION INPUT ;
    USE SIGNAL ;
    PORT
      LAYER Metal3 ;
        RECT  0 825.94 0.4 826.34 ;
    END
  END push_block_i[456]
  PIN push_block_i[457]
    DIRECTION INPUT ;
    USE SIGNAL ;
    PORT
      LAYER Metal3 ;
        RECT  0 827.62 0.4 828.02 ;
    END
  END push_block_i[457]
  PIN push_block_i[458]
    DIRECTION INPUT ;
    USE SIGNAL ;
    PORT
      LAYER Metal3 ;
        RECT  0 829.3 0.4 829.7 ;
    END
  END push_block_i[458]
  PIN push_block_i[459]
    DIRECTION INPUT ;
    USE SIGNAL ;
    PORT
      LAYER Metal3 ;
        RECT  0 830.98 0.4 831.38 ;
    END
  END push_block_i[459]
  PIN push_block_i[45]
    DIRECTION INPUT ;
    USE SIGNAL ;
    PORT
      LAYER Metal3 ;
        RECT  0 135.46 0.4 135.86 ;
    END
  END push_block_i[45]
  PIN push_block_i[460]
    DIRECTION INPUT ;
    USE SIGNAL ;
    PORT
      LAYER Metal3 ;
        RECT  0 832.66 0.4 833.06 ;
    END
  END push_block_i[460]
  PIN push_block_i[461]
    DIRECTION INPUT ;
    USE SIGNAL ;
    PORT
      LAYER Metal3 ;
        RECT  0 834.34 0.4 834.74 ;
    END
  END push_block_i[461]
  PIN push_block_i[462]
    DIRECTION INPUT ;
    USE SIGNAL ;
    PORT
      LAYER Metal3 ;
        RECT  0 836.02 0.4 836.42 ;
    END
  END push_block_i[462]
  PIN push_block_i[463]
    DIRECTION INPUT ;
    USE SIGNAL ;
    PORT
      LAYER Metal3 ;
        RECT  0 837.7 0.4 838.1 ;
    END
  END push_block_i[463]
  PIN push_block_i[464]
    DIRECTION INPUT ;
    USE SIGNAL ;
    PORT
      LAYER Metal3 ;
        RECT  0 839.38 0.4 839.78 ;
    END
  END push_block_i[464]
  PIN push_block_i[465]
    DIRECTION INPUT ;
    USE SIGNAL ;
    PORT
      LAYER Metal3 ;
        RECT  0 841.06 0.4 841.46 ;
    END
  END push_block_i[465]
  PIN push_block_i[466]
    DIRECTION INPUT ;
    USE SIGNAL ;
    PORT
      LAYER Metal3 ;
        RECT  0 842.74 0.4 843.14 ;
    END
  END push_block_i[466]
  PIN push_block_i[467]
    DIRECTION INPUT ;
    USE SIGNAL ;
    PORT
      LAYER Metal3 ;
        RECT  0 844.42 0.4 844.82 ;
    END
  END push_block_i[467]
  PIN push_block_i[468]
    DIRECTION INPUT ;
    USE SIGNAL ;
    PORT
      LAYER Metal3 ;
        RECT  0 846.1 0.4 846.5 ;
    END
  END push_block_i[468]
  PIN push_block_i[469]
    DIRECTION INPUT ;
    USE SIGNAL ;
    PORT
      LAYER Metal3 ;
        RECT  0 847.78 0.4 848.18 ;
    END
  END push_block_i[469]
  PIN push_block_i[46]
    DIRECTION INPUT ;
    USE SIGNAL ;
    PORT
      LAYER Metal3 ;
        RECT  0 137.14 0.4 137.54 ;
    END
  END push_block_i[46]
  PIN push_block_i[470]
    DIRECTION INPUT ;
    USE SIGNAL ;
    PORT
      LAYER Metal3 ;
        RECT  0 849.46 0.4 849.86 ;
    END
  END push_block_i[470]
  PIN push_block_i[471]
    DIRECTION INPUT ;
    USE SIGNAL ;
    PORT
      LAYER Metal3 ;
        RECT  0 851.14 0.4 851.54 ;
    END
  END push_block_i[471]
  PIN push_block_i[472]
    DIRECTION INPUT ;
    USE SIGNAL ;
    PORT
      LAYER Metal3 ;
        RECT  0 852.82 0.4 853.22 ;
    END
  END push_block_i[472]
  PIN push_block_i[473]
    DIRECTION INPUT ;
    USE SIGNAL ;
    PORT
      LAYER Metal3 ;
        RECT  0 854.5 0.4 854.9 ;
    END
  END push_block_i[473]
  PIN push_block_i[474]
    DIRECTION INPUT ;
    USE SIGNAL ;
    PORT
      LAYER Metal3 ;
        RECT  0 856.18 0.4 856.58 ;
    END
  END push_block_i[474]
  PIN push_block_i[475]
    DIRECTION INPUT ;
    USE SIGNAL ;
    PORT
      LAYER Metal3 ;
        RECT  0 857.86 0.4 858.26 ;
    END
  END push_block_i[475]
  PIN push_block_i[476]
    DIRECTION INPUT ;
    USE SIGNAL ;
    PORT
      LAYER Metal3 ;
        RECT  0 859.54 0.4 859.94 ;
    END
  END push_block_i[476]
  PIN push_block_i[477]
    DIRECTION INPUT ;
    USE SIGNAL ;
    PORT
      LAYER Metal3 ;
        RECT  0 861.22 0.4 861.62 ;
    END
  END push_block_i[477]
  PIN push_block_i[478]
    DIRECTION INPUT ;
    USE SIGNAL ;
    PORT
      LAYER Metal3 ;
        RECT  0 862.9 0.4 863.3 ;
    END
  END push_block_i[478]
  PIN push_block_i[479]
    DIRECTION INPUT ;
    USE SIGNAL ;
    PORT
      LAYER Metal3 ;
        RECT  0 864.58 0.4 864.98 ;
    END
  END push_block_i[479]
  PIN push_block_i[47]
    DIRECTION INPUT ;
    USE SIGNAL ;
    PORT
      LAYER Metal3 ;
        RECT  0 138.82 0.4 139.22 ;
    END
  END push_block_i[47]
  PIN push_block_i[480]
    DIRECTION INPUT ;
    USE SIGNAL ;
    PORT
      LAYER Metal3 ;
        RECT  0 866.26 0.4 866.66 ;
    END
  END push_block_i[480]
  PIN push_block_i[481]
    DIRECTION INPUT ;
    USE SIGNAL ;
    PORT
      LAYER Metal3 ;
        RECT  0 867.94 0.4 868.34 ;
    END
  END push_block_i[481]
  PIN push_block_i[482]
    DIRECTION INPUT ;
    USE SIGNAL ;
    PORT
      LAYER Metal3 ;
        RECT  0 869.62 0.4 870.02 ;
    END
  END push_block_i[482]
  PIN push_block_i[483]
    DIRECTION INPUT ;
    USE SIGNAL ;
    PORT
      LAYER Metal3 ;
        RECT  0 871.3 0.4 871.7 ;
    END
  END push_block_i[483]
  PIN push_block_i[484]
    DIRECTION INPUT ;
    USE SIGNAL ;
    PORT
      LAYER Metal3 ;
        RECT  0 872.98 0.4 873.38 ;
    END
  END push_block_i[484]
  PIN push_block_i[485]
    DIRECTION INPUT ;
    USE SIGNAL ;
    PORT
      LAYER Metal3 ;
        RECT  0 874.66 0.4 875.06 ;
    END
  END push_block_i[485]
  PIN push_block_i[486]
    DIRECTION INPUT ;
    USE SIGNAL ;
    PORT
      LAYER Metal3 ;
        RECT  0 876.34 0.4 876.74 ;
    END
  END push_block_i[486]
  PIN push_block_i[487]
    DIRECTION INPUT ;
    USE SIGNAL ;
    PORT
      LAYER Metal3 ;
        RECT  0 878.02 0.4 878.42 ;
    END
  END push_block_i[487]
  PIN push_block_i[488]
    DIRECTION INPUT ;
    USE SIGNAL ;
    PORT
      LAYER Metal3 ;
        RECT  0 879.7 0.4 880.1 ;
    END
  END push_block_i[488]
  PIN push_block_i[489]
    DIRECTION INPUT ;
    USE SIGNAL ;
    PORT
      LAYER Metal3 ;
        RECT  0 881.38 0.4 881.78 ;
    END
  END push_block_i[489]
  PIN push_block_i[48]
    DIRECTION INPUT ;
    USE SIGNAL ;
    PORT
      LAYER Metal3 ;
        RECT  0 140.5 0.4 140.9 ;
    END
  END push_block_i[48]
  PIN push_block_i[490]
    DIRECTION INPUT ;
    USE SIGNAL ;
    PORT
      LAYER Metal3 ;
        RECT  0 883.06 0.4 883.46 ;
    END
  END push_block_i[490]
  PIN push_block_i[491]
    DIRECTION INPUT ;
    USE SIGNAL ;
    PORT
      LAYER Metal3 ;
        RECT  0 884.74 0.4 885.14 ;
    END
  END push_block_i[491]
  PIN push_block_i[492]
    DIRECTION INPUT ;
    USE SIGNAL ;
    PORT
      LAYER Metal3 ;
        RECT  0 886.42 0.4 886.82 ;
    END
  END push_block_i[492]
  PIN push_block_i[493]
    DIRECTION INPUT ;
    USE SIGNAL ;
    PORT
      LAYER Metal3 ;
        RECT  0 888.1 0.4 888.5 ;
    END
  END push_block_i[493]
  PIN push_block_i[494]
    DIRECTION INPUT ;
    USE SIGNAL ;
    PORT
      LAYER Metal3 ;
        RECT  0 889.78 0.4 890.18 ;
    END
  END push_block_i[494]
  PIN push_block_i[495]
    DIRECTION INPUT ;
    USE SIGNAL ;
    PORT
      LAYER Metal3 ;
        RECT  0 891.46 0.4 891.86 ;
    END
  END push_block_i[495]
  PIN push_block_i[496]
    DIRECTION INPUT ;
    USE SIGNAL ;
    PORT
      LAYER Metal3 ;
        RECT  0 893.14 0.4 893.54 ;
    END
  END push_block_i[496]
  PIN push_block_i[497]
    DIRECTION INPUT ;
    USE SIGNAL ;
    PORT
      LAYER Metal3 ;
        RECT  0 894.82 0.4 895.22 ;
    END
  END push_block_i[497]
  PIN push_block_i[498]
    DIRECTION INPUT ;
    USE SIGNAL ;
    PORT
      LAYER Metal3 ;
        RECT  0 896.5 0.4 896.9 ;
    END
  END push_block_i[498]
  PIN push_block_i[499]
    DIRECTION INPUT ;
    USE SIGNAL ;
    PORT
      LAYER Metal3 ;
        RECT  0 898.18 0.4 898.58 ;
    END
  END push_block_i[499]
  PIN push_block_i[49]
    DIRECTION INPUT ;
    USE SIGNAL ;
    PORT
      LAYER Metal3 ;
        RECT  0 142.18 0.4 142.58 ;
    END
  END push_block_i[49]
  PIN push_block_i[4]
    DIRECTION INPUT ;
    USE SIGNAL ;
    PORT
      LAYER Metal3 ;
        RECT  0 66.58 0.4 66.98 ;
    END
  END push_block_i[4]
  PIN push_block_i[500]
    DIRECTION INPUT ;
    USE SIGNAL ;
    PORT
      LAYER Metal3 ;
        RECT  0 899.86 0.4 900.26 ;
    END
  END push_block_i[500]
  PIN push_block_i[501]
    DIRECTION INPUT ;
    USE SIGNAL ;
    PORT
      LAYER Metal3 ;
        RECT  0 901.54 0.4 901.94 ;
    END
  END push_block_i[501]
  PIN push_block_i[502]
    DIRECTION INPUT ;
    USE SIGNAL ;
    PORT
      LAYER Metal3 ;
        RECT  0 903.22 0.4 903.62 ;
    END
  END push_block_i[502]
  PIN push_block_i[503]
    DIRECTION INPUT ;
    USE SIGNAL ;
    PORT
      LAYER Metal3 ;
        RECT  0 904.9 0.4 905.3 ;
    END
  END push_block_i[503]
  PIN push_block_i[504]
    DIRECTION INPUT ;
    USE SIGNAL ;
    PORT
      LAYER Metal3 ;
        RECT  0 906.58 0.4 906.98 ;
    END
  END push_block_i[504]
  PIN push_block_i[505]
    DIRECTION INPUT ;
    USE SIGNAL ;
    PORT
      LAYER Metal3 ;
        RECT  0 908.26 0.4 908.66 ;
    END
  END push_block_i[505]
  PIN push_block_i[506]
    DIRECTION INPUT ;
    USE SIGNAL ;
    PORT
      LAYER Metal3 ;
        RECT  0 909.94 0.4 910.34 ;
    END
  END push_block_i[506]
  PIN push_block_i[507]
    DIRECTION INPUT ;
    USE SIGNAL ;
    PORT
      LAYER Metal3 ;
        RECT  0 911.62 0.4 912.02 ;
    END
  END push_block_i[507]
  PIN push_block_i[508]
    DIRECTION INPUT ;
    USE SIGNAL ;
    PORT
      LAYER Metal3 ;
        RECT  0 913.3 0.4 913.7 ;
    END
  END push_block_i[508]
  PIN push_block_i[509]
    DIRECTION INPUT ;
    USE SIGNAL ;
    PORT
      LAYER Metal3 ;
        RECT  0 914.98 0.4 915.38 ;
    END
  END push_block_i[509]
  PIN push_block_i[50]
    DIRECTION INPUT ;
    USE SIGNAL ;
    PORT
      LAYER Metal3 ;
        RECT  0 143.86 0.4 144.26 ;
    END
  END push_block_i[50]
  PIN push_block_i[510]
    DIRECTION INPUT ;
    USE SIGNAL ;
    PORT
      LAYER Metal3 ;
        RECT  0 916.66 0.4 917.06 ;
    END
  END push_block_i[510]
  PIN push_block_i[511]
    DIRECTION INPUT ;
    USE SIGNAL ;
    PORT
      LAYER Metal3 ;
        RECT  0 918.34 0.4 918.74 ;
    END
  END push_block_i[511]
  PIN push_block_i[512]
    DIRECTION INPUT ;
    USE SIGNAL ;
    PORT
      LAYER Metal3 ;
        RECT  0 920.02 0.4 920.42 ;
    END
  END push_block_i[512]
  PIN push_block_i[513]
    DIRECTION INPUT ;
    USE SIGNAL ;
    PORT
      LAYER Metal3 ;
        RECT  0 921.7 0.4 922.1 ;
    END
  END push_block_i[513]
  PIN push_block_i[514]
    DIRECTION INPUT ;
    USE SIGNAL ;
    PORT
      LAYER Metal3 ;
        RECT  0 923.38 0.4 923.78 ;
    END
  END push_block_i[514]
  PIN push_block_i[515]
    DIRECTION INPUT ;
    USE SIGNAL ;
    PORT
      LAYER Metal3 ;
        RECT  0 925.06 0.4 925.46 ;
    END
  END push_block_i[515]
  PIN push_block_i[516]
    DIRECTION INPUT ;
    USE SIGNAL ;
    PORT
      LAYER Metal3 ;
        RECT  0 926.74 0.4 927.14 ;
    END
  END push_block_i[516]
  PIN push_block_i[517]
    DIRECTION INPUT ;
    USE SIGNAL ;
    PORT
      LAYER Metal3 ;
        RECT  0 928.42 0.4 928.82 ;
    END
  END push_block_i[517]
  PIN push_block_i[518]
    DIRECTION INPUT ;
    USE SIGNAL ;
    PORT
      LAYER Metal3 ;
        RECT  0 930.1 0.4 930.5 ;
    END
  END push_block_i[518]
  PIN push_block_i[519]
    DIRECTION INPUT ;
    USE SIGNAL ;
    PORT
      LAYER Metal3 ;
        RECT  0 931.78 0.4 932.18 ;
    END
  END push_block_i[519]
  PIN push_block_i[51]
    DIRECTION INPUT ;
    USE SIGNAL ;
    PORT
      LAYER Metal3 ;
        RECT  0 145.54 0.4 145.94 ;
    END
  END push_block_i[51]
  PIN push_block_i[520]
    DIRECTION INPUT ;
    USE SIGNAL ;
    PORT
      LAYER Metal3 ;
        RECT  0 933.46 0.4 933.86 ;
    END
  END push_block_i[520]
  PIN push_block_i[521]
    DIRECTION INPUT ;
    USE SIGNAL ;
    PORT
      LAYER Metal3 ;
        RECT  0 935.14 0.4 935.54 ;
    END
  END push_block_i[521]
  PIN push_block_i[522]
    DIRECTION INPUT ;
    USE SIGNAL ;
    PORT
      LAYER Metal3 ;
        RECT  0 936.82 0.4 937.22 ;
    END
  END push_block_i[522]
  PIN push_block_i[523]
    DIRECTION INPUT ;
    USE SIGNAL ;
    PORT
      LAYER Metal3 ;
        RECT  0 938.5 0.4 938.9 ;
    END
  END push_block_i[523]
  PIN push_block_i[524]
    DIRECTION INPUT ;
    USE SIGNAL ;
    PORT
      LAYER Metal3 ;
        RECT  0 940.18 0.4 940.58 ;
    END
  END push_block_i[524]
  PIN push_block_i[525]
    DIRECTION INPUT ;
    USE SIGNAL ;
    PORT
      LAYER Metal3 ;
        RECT  0 941.86 0.4 942.26 ;
    END
  END push_block_i[525]
  PIN push_block_i[526]
    DIRECTION INPUT ;
    USE SIGNAL ;
    PORT
      LAYER Metal3 ;
        RECT  0 943.54 0.4 943.94 ;
    END
  END push_block_i[526]
  PIN push_block_i[527]
    DIRECTION INPUT ;
    USE SIGNAL ;
    PORT
      LAYER Metal3 ;
        RECT  0 945.22 0.4 945.62 ;
    END
  END push_block_i[527]
  PIN push_block_i[528]
    DIRECTION INPUT ;
    USE SIGNAL ;
    PORT
      LAYER Metal3 ;
        RECT  0 946.9 0.4 947.3 ;
    END
  END push_block_i[528]
  PIN push_block_i[529]
    DIRECTION INPUT ;
    USE SIGNAL ;
    PORT
      LAYER Metal3 ;
        RECT  0 948.58 0.4 948.98 ;
    END
  END push_block_i[529]
  PIN push_block_i[52]
    DIRECTION INPUT ;
    USE SIGNAL ;
    PORT
      LAYER Metal3 ;
        RECT  0 147.22 0.4 147.62 ;
    END
  END push_block_i[52]
  PIN push_block_i[530]
    DIRECTION INPUT ;
    USE SIGNAL ;
    PORT
      LAYER Metal3 ;
        RECT  0 950.26 0.4 950.66 ;
    END
  END push_block_i[530]
  PIN push_block_i[531]
    DIRECTION INPUT ;
    USE SIGNAL ;
    PORT
      LAYER Metal3 ;
        RECT  0 951.94 0.4 952.34 ;
    END
  END push_block_i[531]
  PIN push_block_i[532]
    DIRECTION INPUT ;
    USE SIGNAL ;
    PORT
      LAYER Metal3 ;
        RECT  0 953.62 0.4 954.02 ;
    END
  END push_block_i[532]
  PIN push_block_i[533]
    DIRECTION INPUT ;
    USE SIGNAL ;
    PORT
      LAYER Metal3 ;
        RECT  0 955.3 0.4 955.7 ;
    END
  END push_block_i[533]
  PIN push_block_i[534]
    DIRECTION INPUT ;
    USE SIGNAL ;
    PORT
      LAYER Metal3 ;
        RECT  0 956.98 0.4 957.38 ;
    END
  END push_block_i[534]
  PIN push_block_i[535]
    DIRECTION INPUT ;
    USE SIGNAL ;
    PORT
      LAYER Metal3 ;
        RECT  0 958.66 0.4 959.06 ;
    END
  END push_block_i[535]
  PIN push_block_i[536]
    DIRECTION INPUT ;
    USE SIGNAL ;
    PORT
      LAYER Metal3 ;
        RECT  0 960.34 0.4 960.74 ;
    END
  END push_block_i[536]
  PIN push_block_i[537]
    DIRECTION INPUT ;
    USE SIGNAL ;
    PORT
      LAYER Metal3 ;
        RECT  0 962.02 0.4 962.42 ;
    END
  END push_block_i[537]
  PIN push_block_i[538]
    DIRECTION INPUT ;
    USE SIGNAL ;
    PORT
      LAYER Metal3 ;
        RECT  0 963.7 0.4 964.1 ;
    END
  END push_block_i[538]
  PIN push_block_i[539]
    DIRECTION INPUT ;
    USE SIGNAL ;
    PORT
      LAYER Metal3 ;
        RECT  0 965.38 0.4 965.78 ;
    END
  END push_block_i[539]
  PIN push_block_i[53]
    DIRECTION INPUT ;
    USE SIGNAL ;
    PORT
      LAYER Metal3 ;
        RECT  0 148.9 0.4 149.3 ;
    END
  END push_block_i[53]
  PIN push_block_i[540]
    DIRECTION INPUT ;
    USE SIGNAL ;
    PORT
      LAYER Metal3 ;
        RECT  0 967.06 0.4 967.46 ;
    END
  END push_block_i[540]
  PIN push_block_i[541]
    DIRECTION INPUT ;
    USE SIGNAL ;
    PORT
      LAYER Metal3 ;
        RECT  0 968.74 0.4 969.14 ;
    END
  END push_block_i[541]
  PIN push_block_i[542]
    DIRECTION INPUT ;
    USE SIGNAL ;
    PORT
      LAYER Metal3 ;
        RECT  0 970.42 0.4 970.82 ;
    END
  END push_block_i[542]
  PIN push_block_i[543]
    DIRECTION INPUT ;
    USE SIGNAL ;
    PORT
      LAYER Metal3 ;
        RECT  0 972.1 0.4 972.5 ;
    END
  END push_block_i[543]
  PIN push_block_i[544]
    DIRECTION INPUT ;
    USE SIGNAL ;
    PORT
      LAYER Metal3 ;
        RECT  0 973.78 0.4 974.18 ;
    END
  END push_block_i[544]
  PIN push_block_i[545]
    DIRECTION INPUT ;
    USE SIGNAL ;
    PORT
      LAYER Metal3 ;
        RECT  0 975.46 0.4 975.86 ;
    END
  END push_block_i[545]
  PIN push_block_i[546]
    DIRECTION INPUT ;
    USE SIGNAL ;
    PORT
      LAYER Metal3 ;
        RECT  0 977.14 0.4 977.54 ;
    END
  END push_block_i[546]
  PIN push_block_i[547]
    DIRECTION INPUT ;
    USE SIGNAL ;
    PORT
      LAYER Metal3 ;
        RECT  0 978.82 0.4 979.22 ;
    END
  END push_block_i[547]
  PIN push_block_i[548]
    DIRECTION INPUT ;
    USE SIGNAL ;
    PORT
      LAYER Metal3 ;
        RECT  0 980.5 0.4 980.9 ;
    END
  END push_block_i[548]
  PIN push_block_i[549]
    DIRECTION INPUT ;
    USE SIGNAL ;
    PORT
      LAYER Metal3 ;
        RECT  0 982.18 0.4 982.58 ;
    END
  END push_block_i[549]
  PIN push_block_i[54]
    DIRECTION INPUT ;
    USE SIGNAL ;
    PORT
      LAYER Metal3 ;
        RECT  0 150.58 0.4 150.98 ;
    END
  END push_block_i[54]
  PIN push_block_i[550]
    DIRECTION INPUT ;
    USE SIGNAL ;
    PORT
      LAYER Metal3 ;
        RECT  0 983.86 0.4 984.26 ;
    END
  END push_block_i[550]
  PIN push_block_i[551]
    DIRECTION INPUT ;
    USE SIGNAL ;
    PORT
      LAYER Metal3 ;
        RECT  0 985.54 0.4 985.94 ;
    END
  END push_block_i[551]
  PIN push_block_i[552]
    DIRECTION INPUT ;
    USE SIGNAL ;
    PORT
      LAYER Metal3 ;
        RECT  0 987.22 0.4 987.62 ;
    END
  END push_block_i[552]
  PIN push_block_i[553]
    DIRECTION INPUT ;
    USE SIGNAL ;
    PORT
      LAYER Metal3 ;
        RECT  0 988.9 0.4 989.3 ;
    END
  END push_block_i[553]
  PIN push_block_i[554]
    DIRECTION INPUT ;
    USE SIGNAL ;
    PORT
      LAYER Metal3 ;
        RECT  0 990.58 0.4 990.98 ;
    END
  END push_block_i[554]
  PIN push_block_i[555]
    DIRECTION INPUT ;
    USE SIGNAL ;
    PORT
      LAYER Metal3 ;
        RECT  0 992.26 0.4 992.66 ;
    END
  END push_block_i[555]
  PIN push_block_i[556]
    DIRECTION INPUT ;
    USE SIGNAL ;
    PORT
      LAYER Metal3 ;
        RECT  0 993.94 0.4 994.34 ;
    END
  END push_block_i[556]
  PIN push_block_i[557]
    DIRECTION INPUT ;
    USE SIGNAL ;
    PORT
      LAYER Metal3 ;
        RECT  0 995.62 0.4 996.02 ;
    END
  END push_block_i[557]
  PIN push_block_i[558]
    DIRECTION INPUT ;
    USE SIGNAL ;
    PORT
      LAYER Metal3 ;
        RECT  0 997.3 0.4 997.7 ;
    END
  END push_block_i[558]
  PIN push_block_i[559]
    DIRECTION INPUT ;
    USE SIGNAL ;
    PORT
      LAYER Metal3 ;
        RECT  0 998.98 0.4 999.38 ;
    END
  END push_block_i[559]
  PIN push_block_i[55]
    DIRECTION INPUT ;
    USE SIGNAL ;
    PORT
      LAYER Metal3 ;
        RECT  0 152.26 0.4 152.66 ;
    END
  END push_block_i[55]
  PIN push_block_i[560]
    DIRECTION INPUT ;
    USE SIGNAL ;
    PORT
      LAYER Metal3 ;
        RECT  0 1000.66 0.4 1001.06 ;
    END
  END push_block_i[560]
  PIN push_block_i[561]
    DIRECTION INPUT ;
    USE SIGNAL ;
    PORT
      LAYER Metal3 ;
        RECT  0 1002.34 0.4 1002.74 ;
    END
  END push_block_i[561]
  PIN push_block_i[562]
    DIRECTION INPUT ;
    USE SIGNAL ;
    PORT
      LAYER Metal3 ;
        RECT  0 1004.02 0.4 1004.42 ;
    END
  END push_block_i[562]
  PIN push_block_i[563]
    DIRECTION INPUT ;
    USE SIGNAL ;
    PORT
      LAYER Metal3 ;
        RECT  0 1005.7 0.4 1006.1 ;
    END
  END push_block_i[563]
  PIN push_block_i[564]
    DIRECTION INPUT ;
    USE SIGNAL ;
    PORT
      LAYER Metal3 ;
        RECT  0 1007.38 0.4 1007.78 ;
    END
  END push_block_i[564]
  PIN push_block_i[565]
    DIRECTION INPUT ;
    USE SIGNAL ;
    PORT
      LAYER Metal3 ;
        RECT  0 1009.06 0.4 1009.46 ;
    END
  END push_block_i[565]
  PIN push_block_i[566]
    DIRECTION INPUT ;
    USE SIGNAL ;
    PORT
      LAYER Metal3 ;
        RECT  0 1010.74 0.4 1011.14 ;
    END
  END push_block_i[566]
  PIN push_block_i[567]
    DIRECTION INPUT ;
    USE SIGNAL ;
    PORT
      LAYER Metal3 ;
        RECT  0 1012.42 0.4 1012.82 ;
    END
  END push_block_i[567]
  PIN push_block_i[568]
    DIRECTION INPUT ;
    USE SIGNAL ;
    PORT
      LAYER Metal3 ;
        RECT  0 1014.1 0.4 1014.5 ;
    END
  END push_block_i[568]
  PIN push_block_i[569]
    DIRECTION INPUT ;
    USE SIGNAL ;
    PORT
      LAYER Metal3 ;
        RECT  0 1015.78 0.4 1016.18 ;
    END
  END push_block_i[569]
  PIN push_block_i[56]
    DIRECTION INPUT ;
    USE SIGNAL ;
    PORT
      LAYER Metal3 ;
        RECT  0 153.94 0.4 154.34 ;
    END
  END push_block_i[56]
  PIN push_block_i[570]
    DIRECTION INPUT ;
    USE SIGNAL ;
    PORT
      LAYER Metal3 ;
        RECT  0 1017.46 0.4 1017.86 ;
    END
  END push_block_i[570]
  PIN push_block_i[571]
    DIRECTION INPUT ;
    USE SIGNAL ;
    PORT
      LAYER Metal3 ;
        RECT  0 1019.14 0.4 1019.54 ;
    END
  END push_block_i[571]
  PIN push_block_i[57]
    DIRECTION INPUT ;
    USE SIGNAL ;
    PORT
      LAYER Metal3 ;
        RECT  0 155.62 0.4 156.02 ;
    END
  END push_block_i[57]
  PIN push_block_i[58]
    DIRECTION INPUT ;
    USE SIGNAL ;
    PORT
      LAYER Metal3 ;
        RECT  0 157.3 0.4 157.7 ;
    END
  END push_block_i[58]
  PIN push_block_i[59]
    DIRECTION INPUT ;
    USE SIGNAL ;
    PORT
      LAYER Metal3 ;
        RECT  0 158.98 0.4 159.38 ;
    END
  END push_block_i[59]
  PIN push_block_i[5]
    DIRECTION INPUT ;
    USE SIGNAL ;
    PORT
      LAYER Metal3 ;
        RECT  0 68.26 0.4 68.66 ;
    END
  END push_block_i[5]
  PIN push_block_i[60]
    DIRECTION INPUT ;
    USE SIGNAL ;
    PORT
      LAYER Metal3 ;
        RECT  0 160.66 0.4 161.06 ;
    END
  END push_block_i[60]
  PIN push_block_i[61]
    DIRECTION INPUT ;
    USE SIGNAL ;
    PORT
      LAYER Metal3 ;
        RECT  0 162.34 0.4 162.74 ;
    END
  END push_block_i[61]
  PIN push_block_i[62]
    DIRECTION INPUT ;
    USE SIGNAL ;
    PORT
      LAYER Metal3 ;
        RECT  0 164.02 0.4 164.42 ;
    END
  END push_block_i[62]
  PIN push_block_i[63]
    DIRECTION INPUT ;
    USE SIGNAL ;
    PORT
      LAYER Metal3 ;
        RECT  0 165.7 0.4 166.1 ;
    END
  END push_block_i[63]
  PIN push_block_i[64]
    DIRECTION INPUT ;
    USE SIGNAL ;
    PORT
      LAYER Metal3 ;
        RECT  0 167.38 0.4 167.78 ;
    END
  END push_block_i[64]
  PIN push_block_i[65]
    DIRECTION INPUT ;
    USE SIGNAL ;
    PORT
      LAYER Metal3 ;
        RECT  0 169.06 0.4 169.46 ;
    END
  END push_block_i[65]
  PIN push_block_i[66]
    DIRECTION INPUT ;
    USE SIGNAL ;
    PORT
      LAYER Metal3 ;
        RECT  0 170.74 0.4 171.14 ;
    END
  END push_block_i[66]
  PIN push_block_i[67]
    DIRECTION INPUT ;
    USE SIGNAL ;
    PORT
      LAYER Metal3 ;
        RECT  0 172.42 0.4 172.82 ;
    END
  END push_block_i[67]
  PIN push_block_i[68]
    DIRECTION INPUT ;
    USE SIGNAL ;
    PORT
      LAYER Metal3 ;
        RECT  0 174.1 0.4 174.5 ;
    END
  END push_block_i[68]
  PIN push_block_i[69]
    DIRECTION INPUT ;
    USE SIGNAL ;
    PORT
      LAYER Metal3 ;
        RECT  0 175.78 0.4 176.18 ;
    END
  END push_block_i[69]
  PIN push_block_i[6]
    DIRECTION INPUT ;
    USE SIGNAL ;
    PORT
      LAYER Metal3 ;
        RECT  0 69.94 0.4 70.34 ;
    END
  END push_block_i[6]
  PIN push_block_i[70]
    DIRECTION INPUT ;
    USE SIGNAL ;
    PORT
      LAYER Metal3 ;
        RECT  0 177.46 0.4 177.86 ;
    END
  END push_block_i[70]
  PIN push_block_i[71]
    DIRECTION INPUT ;
    USE SIGNAL ;
    PORT
      LAYER Metal3 ;
        RECT  0 179.14 0.4 179.54 ;
    END
  END push_block_i[71]
  PIN push_block_i[72]
    DIRECTION INPUT ;
    USE SIGNAL ;
    PORT
      LAYER Metal3 ;
        RECT  0 180.82 0.4 181.22 ;
    END
  END push_block_i[72]
  PIN push_block_i[73]
    DIRECTION INPUT ;
    USE SIGNAL ;
    PORT
      LAYER Metal3 ;
        RECT  0 182.5 0.4 182.9 ;
    END
  END push_block_i[73]
  PIN push_block_i[74]
    DIRECTION INPUT ;
    USE SIGNAL ;
    PORT
      LAYER Metal3 ;
        RECT  0 184.18 0.4 184.58 ;
    END
  END push_block_i[74]
  PIN push_block_i[75]
    DIRECTION INPUT ;
    USE SIGNAL ;
    PORT
      LAYER Metal3 ;
        RECT  0 185.86 0.4 186.26 ;
    END
  END push_block_i[75]
  PIN push_block_i[76]
    DIRECTION INPUT ;
    USE SIGNAL ;
    PORT
      LAYER Metal3 ;
        RECT  0 187.54 0.4 187.94 ;
    END
  END push_block_i[76]
  PIN push_block_i[77]
    DIRECTION INPUT ;
    USE SIGNAL ;
    PORT
      LAYER Metal3 ;
        RECT  0 189.22 0.4 189.62 ;
    END
  END push_block_i[77]
  PIN push_block_i[78]
    DIRECTION INPUT ;
    USE SIGNAL ;
    PORT
      LAYER Metal3 ;
        RECT  0 190.9 0.4 191.3 ;
    END
  END push_block_i[78]
  PIN push_block_i[79]
    DIRECTION INPUT ;
    USE SIGNAL ;
    PORT
      LAYER Metal3 ;
        RECT  0 192.58 0.4 192.98 ;
    END
  END push_block_i[79]
  PIN push_block_i[7]
    DIRECTION INPUT ;
    USE SIGNAL ;
    PORT
      LAYER Metal3 ;
        RECT  0 71.62 0.4 72.02 ;
    END
  END push_block_i[7]
  PIN push_block_i[80]
    DIRECTION INPUT ;
    USE SIGNAL ;
    PORT
      LAYER Metal3 ;
        RECT  0 194.26 0.4 194.66 ;
    END
  END push_block_i[80]
  PIN push_block_i[81]
    DIRECTION INPUT ;
    USE SIGNAL ;
    PORT
      LAYER Metal3 ;
        RECT  0 195.94 0.4 196.34 ;
    END
  END push_block_i[81]
  PIN push_block_i[82]
    DIRECTION INPUT ;
    USE SIGNAL ;
    PORT
      LAYER Metal3 ;
        RECT  0 197.62 0.4 198.02 ;
    END
  END push_block_i[82]
  PIN push_block_i[83]
    DIRECTION INPUT ;
    USE SIGNAL ;
    PORT
      LAYER Metal3 ;
        RECT  0 199.3 0.4 199.7 ;
    END
  END push_block_i[83]
  PIN push_block_i[84]
    DIRECTION INPUT ;
    USE SIGNAL ;
    PORT
      LAYER Metal3 ;
        RECT  0 200.98 0.4 201.38 ;
    END
  END push_block_i[84]
  PIN push_block_i[85]
    DIRECTION INPUT ;
    USE SIGNAL ;
    PORT
      LAYER Metal3 ;
        RECT  0 202.66 0.4 203.06 ;
    END
  END push_block_i[85]
  PIN push_block_i[86]
    DIRECTION INPUT ;
    USE SIGNAL ;
    PORT
      LAYER Metal3 ;
        RECT  0 204.34 0.4 204.74 ;
    END
  END push_block_i[86]
  PIN push_block_i[87]
    DIRECTION INPUT ;
    USE SIGNAL ;
    PORT
      LAYER Metal3 ;
        RECT  0 206.02 0.4 206.42 ;
    END
  END push_block_i[87]
  PIN push_block_i[88]
    DIRECTION INPUT ;
    USE SIGNAL ;
    PORT
      LAYER Metal3 ;
        RECT  0 207.7 0.4 208.1 ;
    END
  END push_block_i[88]
  PIN push_block_i[89]
    DIRECTION INPUT ;
    USE SIGNAL ;
    PORT
      LAYER Metal3 ;
        RECT  0 209.38 0.4 209.78 ;
    END
  END push_block_i[89]
  PIN push_block_i[8]
    DIRECTION INPUT ;
    USE SIGNAL ;
    PORT
      LAYER Metal3 ;
        RECT  0 73.3 0.4 73.7 ;
    END
  END push_block_i[8]
  PIN push_block_i[90]
    DIRECTION INPUT ;
    USE SIGNAL ;
    PORT
      LAYER Metal3 ;
        RECT  0 211.06 0.4 211.46 ;
    END
  END push_block_i[90]
  PIN push_block_i[91]
    DIRECTION INPUT ;
    USE SIGNAL ;
    PORT
      LAYER Metal3 ;
        RECT  0 212.74 0.4 213.14 ;
    END
  END push_block_i[91]
  PIN push_block_i[92]
    DIRECTION INPUT ;
    USE SIGNAL ;
    PORT
      LAYER Metal3 ;
        RECT  0 214.42 0.4 214.82 ;
    END
  END push_block_i[92]
  PIN push_block_i[93]
    DIRECTION INPUT ;
    USE SIGNAL ;
    PORT
      LAYER Metal3 ;
        RECT  0 216.1 0.4 216.5 ;
    END
  END push_block_i[93]
  PIN push_block_i[94]
    DIRECTION INPUT ;
    USE SIGNAL ;
    PORT
      LAYER Metal3 ;
        RECT  0 217.78 0.4 218.18 ;
    END
  END push_block_i[94]
  PIN push_block_i[95]
    DIRECTION INPUT ;
    USE SIGNAL ;
    PORT
      LAYER Metal3 ;
        RECT  0 219.46 0.4 219.86 ;
    END
  END push_block_i[95]
  PIN push_block_i[96]
    DIRECTION INPUT ;
    USE SIGNAL ;
    PORT
      LAYER Metal3 ;
        RECT  0 221.14 0.4 221.54 ;
    END
  END push_block_i[96]
  PIN push_block_i[97]
    DIRECTION INPUT ;
    USE SIGNAL ;
    PORT
      LAYER Metal3 ;
        RECT  0 222.82 0.4 223.22 ;
    END
  END push_block_i[97]
  PIN push_block_i[98]
    DIRECTION INPUT ;
    USE SIGNAL ;
    PORT
      LAYER Metal3 ;
        RECT  0 224.5 0.4 224.9 ;
    END
  END push_block_i[98]
  PIN push_block_i[99]
    DIRECTION INPUT ;
    USE SIGNAL ;
    PORT
      LAYER Metal3 ;
        RECT  0 226.18 0.4 226.58 ;
    END
  END push_block_i[99]
  PIN push_block_i[9]
    DIRECTION INPUT ;
    USE SIGNAL ;
    PORT
      LAYER Metal3 ;
        RECT  0 74.98 0.4 75.38 ;
    END
  END push_block_i[9]
  PIN push_count_i[0]
    DIRECTION INPUT ;
    USE SIGNAL ;
    PORT
      LAYER Metal3 ;
        RECT  0 53.14 0.4 53.54 ;
    END
  END push_count_i[0]
  PIN push_count_i[1]
    DIRECTION INPUT ;
    USE SIGNAL ;
    PORT
      LAYER Metal3 ;
        RECT  0 54.82 0.4 55.22 ;
    END
  END push_count_i[1]
  PIN push_count_i[2]
    DIRECTION INPUT ;
    USE SIGNAL ;
    PORT
      LAYER Metal3 ;
        RECT  0 56.5 0.4 56.9 ;
    END
  END push_count_i[2]
  PIN push_count_i[3]
    DIRECTION INPUT ;
    USE SIGNAL ;
    PORT
      LAYER Metal3 ;
        RECT  0 58.18 0.4 58.58 ;
    END
  END push_count_i[3]
  PIN push_ready_o
    DIRECTION OUTPUT ;
    USE SIGNAL ;
    PORT
      LAYER Metal3 ;
        RECT  0 49.78 0.4 50.18 ;
    END
  END push_ready_o
  PIN push_valid_i
    DIRECTION INPUT ;
    USE SIGNAL ;
    PORT
      LAYER Metal3 ;
        RECT  0 51.46 0.4 51.86 ;
    END
  END push_valid_i
  PIN reset_i
    DIRECTION INPUT ;
    USE SIGNAL ;
    PORT
      LAYER Metal2 ;
        RECT  99.16 1099.6 99.56 1100 ;
    END
  END reset_i
  PIN VPWR
    DIRECTION INOUT ;
    USE POWER ;
    PORT
      LAYER TopMetal1 ;
        RECT  5.76 1074.12 793.92 1076.12 ;
        RECT  5.76 1024.12 793.92 1026.12 ;
        RECT  5.76 974.12 793.92 976.12 ;
        RECT  5.76 924.12 793.92 926.12 ;
        RECT  5.76 874.12 793.92 876.12 ;
        RECT  5.76 824.12 793.92 826.12 ;
        RECT  5.76 774.12 793.92 776.12 ;
        RECT  5.76 724.12 793.92 726.12 ;
        RECT  5.76 674.12 793.92 676.12 ;
        RECT  5.76 624.12 793.92 626.12 ;
        RECT  5.76 574.12 793.92 576.12 ;
        RECT  5.76 524.12 793.92 526.12 ;
        RECT  5.76 474.12 793.92 476.12 ;
        RECT  5.76 424.12 793.92 426.12 ;
        RECT  5.76 374.12 793.92 376.12 ;
        RECT  5.76 324.12 793.92 326.12 ;
        RECT  5.76 274.12 793.92 276.12 ;
        RECT  5.76 224.12 793.92 226.12 ;
        RECT  5.76 174.12 793.92 176.12 ;
        RECT  5.76 124.12 793.92 126.12 ;
        RECT  5.76 74.12 793.92 76.12 ;
        RECT  5.76 24.12 793.92 26.12 ;
      LAYER Metal4 ;
        RECT  765.26 14.9 766.26 1085.08 ;
        RECT  715.26 14.9 716.26 1085.08 ;
        RECT  665.26 14.9 666.26 1085.08 ;
        RECT  615.26 14.9 616.26 1085.08 ;
        RECT  565.26 14.9 566.26 1085.08 ;
        RECT  515.26 14.9 516.26 1085.08 ;
        RECT  465.26 14.9 466.26 1085.08 ;
        RECT  415.26 14.9 416.26 1085.08 ;
        RECT  365.26 14.9 366.26 1085.08 ;
        RECT  315.26 14.9 316.26 1085.08 ;
        RECT  265.26 14.9 266.26 1085.08 ;
        RECT  215.26 14.9 216.26 1085.08 ;
        RECT  165.26 14.9 166.26 1085.08 ;
        RECT  115.26 14.9 116.26 1085.08 ;
        RECT  65.26 14.9 66.26 1085.08 ;
        RECT  15.26 14.9 16.26 1085.08 ;
    END
  END VPWR
  PIN VGND
    DIRECTION INOUT ;
    USE GROUND ;
    PORT
      LAYER TopMetal1 ;
        RECT  5.76 1080.12 793.92 1082.12 ;
        RECT  5.76 1030.12 793.92 1032.12 ;
        RECT  5.76 980.12 793.92 982.12 ;
        RECT  5.76 930.12 793.92 932.12 ;
        RECT  5.76 880.12 793.92 882.12 ;
        RECT  5.76 830.12 793.92 832.12 ;
        RECT  5.76 780.12 793.92 782.12 ;
        RECT  5.76 730.12 793.92 732.12 ;
        RECT  5.76 680.12 793.92 682.12 ;
        RECT  5.76 630.12 793.92 632.12 ;
        RECT  5.76 580.12 793.92 582.12 ;
        RECT  5.76 530.12 793.92 532.12 ;
        RECT  5.76 480.12 793.92 482.12 ;
        RECT  5.76 430.12 793.92 432.12 ;
        RECT  5.76 380.12 793.92 382.12 ;
        RECT  5.76 330.12 793.92 332.12 ;
        RECT  5.76 280.12 793.92 282.12 ;
        RECT  5.76 230.12 793.92 232.12 ;
        RECT  5.76 180.12 793.92 182.12 ;
        RECT  5.76 130.12 793.92 132.12 ;
        RECT  5.76 80.12 793.92 82.12 ;
        RECT  5.76 30.12 793.92 32.12 ;
      LAYER Metal4 ;
        RECT  768.26 14.9 769.26 1085.08 ;
        RECT  718.26 14.9 719.26 1085.08 ;
        RECT  668.26 14.9 669.26 1085.08 ;
        RECT  618.26 14.9 619.26 1085.08 ;
        RECT  568.26 14.9 569.26 1085.08 ;
        RECT  518.26 14.9 519.26 1085.08 ;
        RECT  468.26 14.9 469.26 1085.08 ;
        RECT  418.26 14.9 419.26 1085.08 ;
        RECT  368.26 14.9 369.26 1085.08 ;
        RECT  318.26 14.9 319.26 1085.08 ;
        RECT  268.26 14.9 269.26 1085.08 ;
        RECT  218.26 14.9 219.26 1085.08 ;
        RECT  168.26 14.9 169.26 1085.08 ;
        RECT  118.26 14.9 119.26 1085.08 ;
        RECT  68.26 14.9 69.26 1085.08 ;
        RECT  18.26 14.9 19.26 1085.08 ;
    END
  END VGND
  OBS
    LAYER Metal1 ;
     RECT  5.76 14.9 793.92 1085.08 ;
    LAYER Metal2 ;
     RECT  230.3 16.7 237.22 17.96 ;
     RECT  18.455 14.975 19.065 18.755 ;
     RECT  68.455 14.975 69.065 18.755 ;
     RECT  118.455 14.975 119.065 18.755 ;
     RECT  168.455 14.975 169.065 18.755 ;
     RECT  218.455 14.975 219.065 18.755 ;
     RECT  268.455 14.975 269.065 18.755 ;
     RECT  318.455 14.975 319.065 18.755 ;
     RECT  368.455 14.975 369.065 18.755 ;
     RECT  418.455 14.975 419.065 18.755 ;
     RECT  468.455 14.975 469.065 18.755 ;
     RECT  518.455 14.975 519.065 18.755 ;
     RECT  568.455 14.975 569.065 18.755 ;
     RECT  618.455 14.975 619.065 18.755 ;
     RECT  668.455 14.975 669.065 18.755 ;
     RECT  718.455 14.975 719.065 18.755 ;
     RECT  768.455 14.975 769.065 18.755 ;
     RECT  215.455 18.755 219.065 20.01 ;
     RECT  230.3 17.96 242.98 20.01 ;
     RECT  115.455 18.755 119.065 20.06 ;
     RECT  138.14 20.06 149.38 20.43 ;
     RECT  165.455 18.755 169.065 20.43 ;
     RECT  215.455 20.01 243.94 20.43 ;
     RECT  291.74 20.06 292.9 20.43 ;
     RECT  208.7 20.43 243.94 20.48 ;
     RECT  265.455 18.755 269.065 20.48 ;
     RECT  115.455 20.06 126.82 20.9 ;
     RECT  138.14 20.43 169.065 20.9 ;
     RECT  204.38 20.48 243.94 20.9 ;
     RECT  256.7 20.48 269.065 20.9 ;
     RECT  283.1 20.43 298.66 20.9 ;
     RECT  194.3 20.9 269.065 21.27 ;
     RECT  278.78 20.9 302.98 21.27 ;
     RECT  194.3 21.27 302.98 21.32 ;
     RECT  192.38 21.32 304.9 21.74 ;
     RECT  315.455 18.755 319.065 21.74 ;
     RECT  115.455 20.9 169.065 23 ;
     RECT  192.38 21.74 319.065 23.79 ;
     RECT  115.455 23 173.38 23.84 ;
     RECT  189.98 23.79 319.065 23.84 ;
     RECT  114.62 23.84 173.38 24.26 ;
     RECT  189.5 23.84 319.065 24.26 ;
     RECT  114.14 24.26 173.38 25.52 ;
     RECT  114.14 25.52 174.34 25.94 ;
     RECT  114.14 25.94 176.26 28.46 ;
     RECT  187.58 24.26 319.065 28.46 ;
     RECT  15.455 18.755 19.065 36.02 ;
     RECT  114.14 28.46 319.065 36.02 ;
     RECT  111.74 36.02 319.065 38.91 ;
     RECT  111.26 38.91 319.065 39.38 ;
     RECT  110.3 39.38 319.065 40.17 ;
     RECT  110.3 40.17 324.1 43.58 ;
     RECT  105.5 43.58 324.1 46.47 ;
     RECT  103.58 46.47 324.1 46.94 ;
     RECT  10.94 36.02 19.065 49.41 ;
     RECT  103.1 46.94 324.1 49.83 ;
     RECT  85.34 38.96 85.54 50.3 ;
     RECT  99.26 49.83 324.1 51.085 ;
     RECT  97.82 51.085 324.1 51.14 ;
     RECT  84.86 50.3 85.54 51.56 ;
     RECT  96.38 51.14 324.1 51.56 ;
     RECT  65.455 18.755 69.065 51.98 ;
     RECT  84.86 51.56 324.1 51.98 ;
     RECT  65.455 51.98 325.06 54.5 ;
     RECT  65.455 54.5 327.94 55.76 ;
     RECT  65.455 55.76 330.82 59.54 ;
     RECT  43.1 55.76 43.3 61.84 ;
     RECT  53.18 40.64 53.38 65.42 ;
     RECT  6.14 49.41 19.065 67.52 ;
     RECT  65.455 59.54 333.7 69.62 ;
     RECT  65.455 69.62 337.54 70.88 ;
     RECT  53.18 65.42 53.86 74.66 ;
     RECT  65.455 70.88 342.34 74.66 ;
     RECT  39.74 62.06 39.94 76.34 ;
     RECT  39.74 76.34 40.42 78.02 ;
     RECT  53.18 74.66 343.3 78.22 ;
     RECT  53.18 78.22 338.02 80.12 ;
     RECT  6.14 67.52 26.98 82.22 ;
     RECT  5.66 82.22 26.98 86 ;
     RECT  52.7 80.12 338.02 88.05 ;
     RECT  52.7 88.05 341.86 88.94 ;
     RECT  39.74 78.02 41.38 89.78 ;
     RECT  52.7 88.94 342.82 89.78 ;
     RECT  39.74 89.78 342.82 91.66 ;
     RECT  5.66 86 27.94 92.72 ;
     RECT  39.74 91.66 340.9 103.64 ;
     RECT  39.74 103.64 344.74 106.78 ;
     RECT  39.74 106.78 341.86 111.2 ;
     RECT  5.18 92.72 27.94 112.46 ;
     RECT  39.26 111.2 341.86 119.55 ;
     RECT  39.26 119.55 347.62 122.49 ;
     RECT  39.26 122.49 349.06 123.06 ;
     RECT  3.26 112.46 27.94 127.58 ;
     RECT  1.34 127.58 27.94 131.36 ;
     RECT  1.34 131.36 28.42 133.04 ;
     RECT  39.26 123.06 342.82 133.04 ;
     RECT  1.34 133.04 342.82 133.83 ;
     RECT  1.34 133.83 347.62 134.3 ;
     RECT  1.34 134.3 351.46 134.5 ;
     RECT  39.26 134.5 351.46 135.14 ;
     RECT  39.26 135.14 353.38 137.61 ;
     RECT  365.455 18.755 369.065 137.61 ;
     RECT  39.26 137.61 369.065 138.18 ;
     RECT  39.26 138.18 347.62 141.22 ;
     RECT  1.34 134.5 29.38 145.22 ;
     RECT  39.26 141.22 344.26 145.22 ;
     RECT  1.34 145.22 344.26 151.52 ;
     RECT  359.42 138.18 369.065 152.31 ;
     RECT  1.34 151.52 347.14 152.78 ;
     RECT  357.02 152.31 369.065 152.78 ;
     RECT  1.34 152.78 369.065 179.24 ;
     RECT  1.34 179.24 374.98 186.75 ;
     RECT  1.34 186.75 379.78 195.62 ;
     RECT  1.34 195.62 381.22 216.2 ;
     RECT  1.34 216.2 385.06 217.46 ;
     RECT  1.34 217.46 391.78 222.92 ;
     RECT  1.34 222.92 395.62 225.86 ;
     RECT  1.34 225.86 397.54 235.89 ;
     RECT  1.34 235.89 401.38 236.46 ;
     RECT  1.34 236.46 392.26 248.54 ;
     RECT  1.34 248.54 393.22 251.43 ;
     RECT  1.34 251.43 398.5 252 ;
     RECT  415.455 18.755 419.065 255.68 ;
     RECT  1.34 252 392.74 261.98 ;
     RECT  1.34 261.98 393.7 262.82 ;
     RECT  1.34 262.82 403.3 264.28 ;
     RECT  2.3 264.28 403.3 265.54 ;
     RECT  2.3 265.54 397.54 276.63 ;
     RECT  2.3 276.63 399.46 281.25 ;
     RECT  2.3 281.25 405.22 281.82 ;
     RECT  715.455 18.755 719.065 286.34 ;
     RECT  2.3 281.82 398.98 292.17 ;
     RECT  415.455 255.68 426.82 292.17 ;
     RECT  465.455 18.755 469.065 299.78 ;
     RECT  2.3 292.17 426.82 300.82 ;
     RECT  449.66 263.24 449.86 303.14 ;
     RECT  2.3 300.82 419.065 307.86 ;
     RECT  465.455 299.78 478.66 315.27 ;
     RECT  492.38 314.48 492.58 315.27 ;
     RECT  465.455 315.27 492.58 315.84 ;
     RECT  492.38 315.84 492.58 315.94 ;
     RECT  2.3 307.86 402.82 319.1 ;
     RECT  415.455 307.86 419.065 319.1 ;
     RECT  648.38 322.83 648.58 323.3 ;
     RECT  648.38 323.3 649.54 323.4 ;
     RECT  429.02 301.04 429.22 323.72 ;
     RECT  465.455 315.84 478.66 327.5 ;
     RECT  492.86 317.84 493.06 327.5 ;
     RECT  442.46 303.14 449.86 327.92 ;
     RECT  465.455 327.5 493.06 327.92 ;
     RECT  515.455 18.755 519.065 329.6 ;
     RECT  528.86 255.26 529.06 329.6 ;
     RECT  701.66 319.52 701.86 329.6 ;
     RECT  429.02 323.72 432.1 331.06 ;
     RECT  515.455 329.6 529.06 331.06 ;
     RECT  649.34 323.4 649.54 333.38 ;
     RECT  665.455 18.755 669.065 333.38 ;
     RECT  515.455 331.06 519.065 333.75 ;
     RECT  513.98 333.75 519.065 334.32 ;
     RECT  2.3 319.1 419.065 334.64 ;
     RECT  429.02 331.06 429.7 334.64 ;
     RECT  737.66 254.84 737.86 335.06 ;
     RECT  752.06 314.48 752.26 335.06 ;
     RECT  565.455 18.755 569.065 337.16 ;
     RECT  528.86 331.06 529.06 345.51 ;
     RECT  528.86 345.51 533.38 346.18 ;
     RECT  545.18 341.78 545.38 346.82 ;
     RECT  2.3 334.64 429.7 348.5 ;
     RECT  442.46 327.92 493.06 348.5 ;
     RECT  535.58 346.82 545.38 356.06 ;
     RECT  557.66 337.16 569.065 356.06 ;
     RECT  2.3 348.5 493.06 356.26 ;
     RECT  515.455 334.32 519.065 363.62 ;
     RECT  507.74 363.62 519.065 364.88 ;
     RECT  535.58 356.06 569.065 364.88 ;
     RECT  715.455 286.34 723.46 371.18 ;
     RECT  737.66 335.06 752.26 371.18 ;
     RECT  2.3 356.26 485.86 372.22 ;
     RECT  507.74 364.88 569.065 376.42 ;
     RECT  649.34 333.38 669.065 380.42 ;
     RECT  680.06 344.72 680.26 380.42 ;
     RECT  715.455 371.18 752.26 383.78 ;
     RECT  765.455 18.755 769.065 383.78 ;
     RECT  649.34 380.42 680.26 385.88 ;
     RECT  694.94 329.6 701.86 385.88 ;
     RECT  535.58 376.42 569.065 388.7 ;
     RECT  636.86 374.96 637.06 388.82 ;
     RECT  534.62 388.7 569.065 388.9 ;
     RECT  456.86 372.22 485.86 391.54 ;
     RECT  507.74 376.42 519.065 392.38 ;
     RECT  715.455 383.78 769.065 399.32 ;
     RECT  780.86 391.76 781.06 399.32 ;
     RECT  715.455 399.32 781.06 403.1 ;
     RECT  498.62 399.74 503.14 403.52 ;
     RECT  465.455 391.54 485.86 407.3 ;
     RECT  649.34 385.88 701.86 408.98 ;
     RECT  715.455 403.1 782.5 408.98 ;
     RECT  649.34 408.98 782.5 414.02 ;
     RECT  792.38 313.22 792.58 414.02 ;
     RECT  2.3 372.22 442.66 415.06 ;
     RECT  2.3 415.06 429.7 432.08 ;
     RECT  442.46 415.06 442.66 432.08 ;
     RECT  2.3 432.08 442.66 440.48 ;
     RECT  0.38 440.48 442.66 441.52 ;
     RECT  457.34 407.3 485.86 445.52 ;
     RECT  2.3 441.52 442.66 462.52 ;
     RECT  3.26 462.52 442.66 462.94 ;
     RECT  498.62 403.52 505.54 470.5 ;
     RECT  456.86 445.52 485.86 479.32 ;
     RECT  593.18 484.95 593.38 485.52 ;
     RECT  505.34 470.5 505.54 486.04 ;
     RECT  3.26 462.94 429.7 490.46 ;
     RECT  442.46 462.94 442.66 493.18 ;
     RECT  630.14 388.82 637.06 493.18 ;
     RECT  649.34 414.02 792.58 498.02 ;
     RECT  2.3 490.46 429.7 499.28 ;
     RECT  649.34 498.02 793.54 500.32 ;
     RECT  658.94 500.32 793.54 500.96 ;
     RECT  456.86 479.32 469.065 504.1 ;
     RECT  583.1 492.98 583.3 504.27 ;
     RECT  1.82 499.28 429.7 504.32 ;
     RECT  583.1 504.27 584.26 504.84 ;
     RECT  583.1 504.84 583.3 504.94 ;
     RECT  534.62 388.9 534.82 507.46 ;
     RECT  457.34 504.1 469.065 512.3 ;
     RECT  485.66 479.32 485.86 512.3 ;
     RECT  658.94 500.96 794.02 512.5 ;
     RECT  658.94 512.5 680.74 512.92 ;
     RECT  680.06 512.92 680.74 513.34 ;
     RECT  694.94 512.5 794.02 514.6 ;
     RECT  545.18 388.9 569.065 515.86 ;
     RECT  546.14 515.86 569.065 516.7 ;
     RECT  1.82 504.32 435.46 519.86 ;
     RECT  1.82 519.86 442.66 520.06 ;
     RECT  595.58 486.68 595.78 526.58 ;
     RECT  630.14 493.18 630.34 527.42 ;
     RECT  694.94 514.6 793.54 528.26 ;
     RECT  515.455 392.38 519.065 530.78 ;
     RECT  457.34 512.3 485.86 530.98 ;
     RECT  550.46 516.7 569.065 530.98 ;
     RECT  1.82 520.06 423.46 531.57 ;
     RECT  435.26 520.06 442.66 531.57 ;
     RECT  680.54 513.34 680.74 532.04 ;
     RECT  694.94 528.26 794.02 532.04 ;
     RECT  1.82 531.57 442.66 533.82 ;
     RECT  515.455 530.78 525.7 534.76 ;
     RECT  595.58 526.58 601.06 537.08 ;
     RECT  615.455 18.755 619.065 537.08 ;
     RECT  515.455 534.76 524.74 538.44 ;
     RECT  515.455 538.44 519.94 538.54 ;
     RECT  489.5 540.72 489.7 540.86 ;
     RECT  489.5 540.86 490.18 541.06 ;
     RECT  658.94 512.92 669.7 541.7 ;
     RECT  651.26 541.7 669.7 542.12 ;
     RECT  680.54 532.04 794.02 542.12 ;
     RECT  489.98 541.06 490.18 542.32 ;
     RECT  457.34 530.98 478.66 542.74 ;
     RECT  1.82 533.82 423.46 545.43 ;
     RECT  435.26 533.82 442.66 545.43 ;
     RECT  629.66 527.42 630.34 546.52 ;
     RECT  465.455 542.74 478.66 552.2 ;
     RECT  651.26 542.12 794.02 556.6 ;
     RECT  536.06 538.34 536.26 556.82 ;
     RECT  550.46 530.98 550.66 556.82 ;
     RECT  651.26 556.6 719.065 558.08 ;
     RECT  536.06 556.82 550.66 559.76 ;
     RECT  595.58 537.08 619.065 560.6 ;
     RECT  586.46 560.6 619.065 561.02 ;
     RECT  1.82 545.43 442.66 563.96 ;
     RECT  0.38 563.96 442.66 565 ;
     RECT  1.82 565 442.66 565.22 ;
     RECT  465.455 552.2 485.86 566.26 ;
     RECT  579.26 561.02 619.065 567.1 ;
     RECT  644.54 558.08 719.065 567.32 ;
     RECT  485.66 566.26 485.86 568.11 ;
     RECT  500.06 552.2 500.26 568.11 ;
     RECT  485.66 568.11 500.26 568.68 ;
     RECT  730.94 556.6 794.02 569.84 ;
     RECT  644.54 567.32 720.1 571.72 ;
     RECT  1.82 565.22 449.86 574.24 ;
     RECT  730.94 569.84 794.5 576.56 ;
     RECT  1.82 574.24 437.38 576.66 ;
     RECT  579.26 567.1 586.66 579.92 ;
     RECT  600.86 567.1 619.065 579.92 ;
     RECT  715.455 571.72 720.1 580.76 ;
     RECT  730.94 576.56 794.98 580.76 ;
     RECT  1.82 576.66 436.42 587.48 ;
     RECT  449.66 574.24 449.86 587.48 ;
     RECT  465.455 566.26 469.065 587.48 ;
     RECT  485.66 568.68 485.86 587.48 ;
     RECT  715.455 580.76 795.46 587.48 ;
     RECT  644.54 571.72 702.82 588.32 ;
     RECT  715.455 587.48 795.94 588.32 ;
     RECT  644.54 588.32 795.94 590.62 ;
     RECT  655.58 590.62 795.94 592.72 ;
     RECT  496.7 568.68 500.26 593.98 ;
     RECT  644.54 590.62 644.74 595.88 ;
     RECT  687.26 592.72 795.94 598.18 ;
     RECT  655.58 592.72 673.54 599.02 ;
     RECT  528.86 559.76 550.66 599.66 ;
     RECT  565.455 530.98 569.065 599.66 ;
     RECT  500.06 593.98 500.26 601.76 ;
     RECT  515.455 538.54 519.065 601.76 ;
     RECT  644.06 595.88 644.74 605.32 ;
     RECT  1.82 587.48 449.86 607 ;
     RECT  528.86 599.66 569.065 608.26 ;
     RECT  658.46 599.02 673.54 610.16 ;
     RECT  687.26 598.18 795.46 610.16 ;
     RECT  528.86 608.26 536.26 613.72 ;
     RECT  658.46 610.16 795.94 614.36 ;
     RECT  644.06 605.32 644.26 615.2 ;
     RECT  465.455 587.48 485.86 615.82 ;
     RECT  500.06 601.76 519.065 616.66 ;
     RECT  640.22 615.2 644.26 618.14 ;
     RECT  658.46 614.36 796.9 618.14 ;
     RECT  629.66 546.52 629.86 618.56 ;
     RECT  640.22 618.14 796.9 618.56 ;
     RECT  629.66 618.56 796.9 619.18 ;
     RECT  449.66 607 449.86 622.12 ;
     RECT  528.86 613.72 532.9 629.26 ;
     RECT  465.455 615.82 478.66 635.78 ;
     RECT  492.86 625.28 493.06 635.78 ;
     RECT  465.455 635.78 493.06 636.82 ;
     RECT  550.46 608.26 569.065 637.46 ;
     RECT  629.66 619.18 795.94 640.9 ;
     RECT  629.66 640.9 793.54 643.54 ;
     RECT  1.82 607 436.42 644.38 ;
     RECT  454.46 644.18 454.66 644.6 ;
     RECT  1.82 644.38 405.22 645.22 ;
     RECT  629.66 643.54 793.06 647.74 ;
     RECT  415.455 644.38 436.42 651.32 ;
     RECT  449.66 644.6 454.66 651.32 ;
     RECT  465.455 636.82 480.1 651.94 ;
     RECT  2.78 645.22 405.22 655.05 ;
     RECT  415.455 651.32 454.66 655.05 ;
     RECT  492.86 636.82 493.06 666.02 ;
     RECT  629.66 647.74 791.14 666.22 ;
     RECT  2.78 655.05 454.66 693.94 ;
     RECT  629.66 666.22 680.26 702.76 ;
     RECT  2.78 693.94 405.7 704.61 ;
     RECT  415.455 693.94 454.66 704.61 ;
     RECT  2.78 704.61 454.66 708.54 ;
     RECT  2.78 708.54 405.7 720.3 ;
     RECT  415.455 708.54 454.66 720.3 ;
     RECT  2.78 720.3 454.66 724.92 ;
     RECT  2.78 724.92 401.86 737.37 ;
     RECT  415.455 724.92 454.66 737.37 ;
     RECT  2.78 737.37 454.66 741.72 ;
     RECT  2.78 741.72 404.26 742.66 ;
     RECT  694.46 666.22 791.14 745.18 ;
     RECT  2.78 742.66 400.42 746.02 ;
     RECT  2.78 746.02 397.54 757.53 ;
     RECT  2.78 757.53 404.26 757.78 ;
     RECT  404.06 757.78 404.26 758.1 ;
     RECT  579.26 579.92 619.065 768.28 ;
     RECT  2.78 757.78 393.22 769.76 ;
     RECT  2.78 769.76 397.54 772.06 ;
     RECT  415.455 741.72 454.66 781.3 ;
     RECT  2.78 772.06 391.78 783.57 ;
     RECT  636.86 702.76 680.26 785.92 ;
     RECT  2.78 783.57 397.54 786.51 ;
     RECT  2.78 786.51 398.5 787.08 ;
     RECT  694.46 745.18 790.18 788.44 ;
     RECT  694.46 788.44 788.26 794.74 ;
     RECT  436.22 781.3 454.66 796.42 ;
     RECT  694.46 794.74 745.54 799.78 ;
     RECT  2.78 787.08 392.74 800.42 ;
     RECT  2.78 800.42 398.02 801.63 ;
     RECT  2.78 801.63 398.98 802.2 ;
     RECT  2.78 802.2 398.02 806.5 ;
     RECT  528.86 629.26 529.06 814.48 ;
     RECT  2.78 806.5 397.06 816.75 ;
     RECT  2.78 816.75 397.54 817.32 ;
     RECT  658.46 785.92 680.26 826.66 ;
     RECT  2.78 817.32 391.78 833.38 ;
     RECT  579.26 768.28 601.54 838.84 ;
     RECT  2.78 833.38 387.46 840 ;
     RECT  579.26 838.84 593.86 840.1 ;
     RECT  2.78 840 386.98 843.88 ;
     RECT  2.78 843.88 372.1 845.14 ;
     RECT  2.78 845.14 370.18 847.66 ;
     RECT  694.46 799.78 723.46 849.34 ;
     RECT  2.78 847.66 369.7 853.54 ;
     RECT  2.78 853.54 369.065 860.26 ;
     RECT  2.78 860.26 350.02 867.82 ;
     RECT  759.26 794.74 788.26 868.24 ;
     RECT  397.82 867.2 398.02 870.14 ;
     RECT  465.455 651.94 478.66 870.34 ;
     RECT  397.82 870.14 402.82 871.18 ;
     RECT  2.78 867.82 348.58 871.5 ;
     RECT  360.38 860.26 369.065 878.74 ;
     RECT  694.46 849.34 701.86 879.58 ;
     RECT  386.78 843.88 386.98 881.68 ;
     RECT  385.34 882.27 385.54 882.84 ;
     RECT  2.78 871.5 342.82 890.67 ;
     RECT  2.78 890.67 346.66 893.61 ;
     RECT  2.78 893.61 347.14 894.18 ;
     RECT  415.455 781.3 419.065 896.6 ;
     RECT  636.86 785.92 644.26 896.8 ;
     RECT  414.62 896.6 419.065 897.39 ;
     RECT  409.82 897.39 419.065 897.96 ;
     RECT  414.62 897.96 419.065 898.06 ;
     RECT  694.46 879.58 694.66 903.94 ;
     RECT  2.78 894.18 341.38 904.53 ;
     RECT  2.78 904.53 344.26 905.1 ;
     RECT  2.78 905.1 341.38 905.62 ;
     RECT  2.78 905.62 335.14 909.82 ;
     RECT  399.26 907.94 399.46 911.25 ;
     RECT  2.78 909.82 334.18 911.82 ;
     RECT  399.26 911.25 402.82 911.82 ;
     RECT  2.78 911.82 328.9 911.92 ;
     RECT  492.86 666.02 496.9 911.92 ;
     RECT  2.78 911.92 328.42 913.18 ;
     RECT  399.26 911.82 399.46 913.18 ;
     RECT  2.78 913.18 324.58 916.34 ;
     RECT  2.3 916.34 324.58 917.38 ;
     RECT  2.3 917.38 319.065 918.44 ;
     RECT  1.82 918.44 319.065 921.16 ;
     RECT  543.26 637.46 569.065 932.08 ;
     RECT  759.26 868.24 780.1 932.5 ;
     RECT  557.66 932.08 569.065 939.64 ;
     RECT  507.26 616.66 519.065 940.06 ;
     RECT  496.7 911.92 496.9 943.1 ;
     RECT  496.7 943.1 497.38 943.3 ;
     RECT  658.46 826.66 669.065 953.08 ;
     RECT  441.5 796.42 454.66 953.5 ;
     RECT  439.1 953.67 439.3 954.24 ;
     RECT  579.26 840.1 579.46 959.38 ;
     RECT  449.66 953.5 454.66 961.7 ;
     RECT  465.455 870.34 469.065 961.7 ;
     RECT  636.86 896.8 637.06 961.9 ;
     RECT  2.3 921.16 319.065 965.26 ;
     RECT  497.18 943.3 497.38 973.04 ;
     RECT  680.06 826.66 680.26 976.18 ;
     RECT  765.455 932.5 780.1 976.6 ;
     RECT  449.66 961.7 469.065 977.02 ;
     RECT  493.82 973.04 497.38 977.02 ;
     RECT  497.18 977.02 497.38 977.86 ;
     RECT  593.66 840.1 593.86 980.38 ;
     RECT  737.66 799.78 745.54 982.48 ;
     RECT  765.455 976.6 774.34 987.1 ;
     RECT  3.26 965.26 319.065 990.46 ;
     RECT  4.7 990.46 319.065 991.2 ;
     RECT  4.7 991.2 302.98 992.14 ;
     RECT  543.26 932.08 543.46 992.98 ;
     RECT  745.34 982.48 745.54 993.82 ;
     RECT  4.7 992.14 299.14 995.5 ;
     RECT  715.455 849.34 723.46 1000.54 ;
     RECT  4.7 995.5 297.22 1006.22 ;
     RECT  4.7 1006.22 298.18 1008.1 ;
     RECT  449.66 977.02 449.86 1015.24 ;
     RECT  4.7 1008.1 296.26 1018.82 ;
     RECT  4.7 1018.82 297.7 1022.38 ;
     RECT  5.66 1022.38 295.3 1022.8 ;
     RECT  6.14 1022.8 295.3 1025.74 ;
     RECT  15.455 1025.74 295.3 1029 ;
     RECT  15.455 1029 292.42 1029.1 ;
     RECT  15.455 1029.1 289.54 1033.3 ;
     RECT  15.455 1033.3 45.22 1034.14 ;
     RECT  56.54 1033.3 289.54 1037.975 ;
     RECT  33.02 1034.14 45.22 1041.7 ;
     RECT  264.38 1037.975 289.54 1041.7 ;
     RECT  265.455 1041.7 287.62 1042.595 ;
     RECT  39.26 1041.7 45.22 1044.39 ;
     RECT  56.54 1037.975 245.86 1044.39 ;
     RECT  39.26 1044.39 245.86 1045.06 ;
     RECT  265.455 1042.595 278.02 1045.9 ;
     RECT  42.14 1045.06 245.86 1048.17 ;
     RECT  42.14 1048.17 246.82 1049.26 ;
     RECT  44.06 1049.26 246.82 1052.37 ;
     RECT  44.06 1052.37 248.26 1052.94 ;
     RECT  44.06 1052.94 238.66 1053.46 ;
     RECT  45.5 1053.46 238.66 1055.98 ;
     RECT  45.5 1055.98 234.34 1057.66 ;
     RECT  45.5 1057.66 232.42 1063.54 ;
     RECT  46.46 1063.54 232.42 1064.28 ;
     RECT  48.38 1064.28 232.42 1064.38 ;
     RECT  48.86 1064.38 232.42 1066.8 ;
     RECT  48.86 1066.8 228.1 1074.21 ;
     RECT  46.46 1074.21 228.1 1074.46 ;
     RECT  46.46 1074.46 227.62 1074.78 ;
     RECT  48.38 1074.78 227.62 1075.3 ;
     RECT  48.86 1075.3 227.62 1078.66 ;
     RECT  56.54 1078.66 227.62 1079.4 ;
     RECT  58.46 1079.4 227.62 1079.5 ;
     RECT  188.06 1079.5 188.26 1079.555 ;
     RECT  15.455 1034.14 19.065 1081.225 ;
     RECT  206.78 1079.5 227.62 1081.225 ;
     RECT  265.455 1045.9 269.065 1081.225 ;
     RECT  315.455 991.2 319.065 1081.225 ;
     RECT  365.455 878.74 369.065 1081.225 ;
     RECT  415.455 898.06 419.065 1081.225 ;
     RECT  465.455 977.02 469.065 1081.225 ;
     RECT  515.455 940.06 519.065 1081.225 ;
     RECT  565.455 939.64 569.065 1081.225 ;
     RECT  615.455 768.28 619.065 1081.225 ;
     RECT  665.455 953.08 669.065 1081.225 ;
     RECT  715.455 1000.54 719.065 1081.225 ;
     RECT  765.455 987.1 769.065 1081.225 ;
     RECT  227.42 1081.225 227.62 1082.02 ;
     RECT  92.06 1079.5 104.26 1082.86 ;
     RECT  58.94 1079.5 75.94 1083.7 ;
     RECT  92.06 1082.86 103.78 1083.7 ;
     RECT  115.455 1079.5 129.22 1083.7 ;
     RECT  140.54 1079.5 146.98 1083.7 ;
     RECT  157.82 1079.5 174.82 1083.7 ;
     RECT  206.78 1081.225 216.065 1083.7 ;
     RECT  99.26 1083.7 103.78 1084.17 ;
     RECT  15.455 1081.225 16.065 1085.005 ;
     RECT  65.455 1083.7 66.065 1085.005 ;
     RECT  115.455 1083.7 116.065 1085.005 ;
     RECT  165.455 1083.7 166.065 1085.005 ;
     RECT  215.455 1083.7 216.065 1085.005 ;
     RECT  265.455 1081.225 266.065 1085.005 ;
     RECT  315.455 1081.225 316.065 1085.005 ;
     RECT  365.455 1081.225 366.065 1085.005 ;
     RECT  415.455 1081.225 416.065 1085.005 ;
     RECT  465.455 1081.225 466.065 1085.005 ;
     RECT  515.455 1081.225 516.065 1085.005 ;
     RECT  565.455 1081.225 566.065 1085.005 ;
     RECT  615.455 1081.225 616.065 1085.005 ;
     RECT  665.455 1081.225 666.065 1085.005 ;
     RECT  715.455 1081.225 716.065 1085.005 ;
     RECT  765.455 1081.225 766.065 1085.005 ;
     RECT  99.26 1084.17 102.82 1089.58 ;
     RECT  99.26 1089.58 101.38 1099.8 ;
    LAYER Metal3 ;
     RECT  0.2 49.88 4.7 1019.44 ;
     RECT  10.94 36.02 15.4 36.22 ;
     RECT  4.7 49.88 15.4 1022.38 ;
     RECT  15.4 18.8 16.12 1084.96 ;
     RECT  16.12 18.8 18.4 1081.18 ;
     RECT  18.4 15.02 19.12 1081.18 ;
     RECT  19.12 50.72 33.02 1034.14 ;
     RECT  19.12 36.02 35.9 36.22 ;
     RECT  35.9 36.02 36.1 36.64 ;
     RECT  33.02 50.72 39.26 1037.5 ;
     RECT  39.26 50.72 42.14 1045.06 ;
     RECT  42.14 50.72 45.22 1048.42 ;
     RECT  45.5 1059.98 46.46 1060.18 ;
     RECT  45.22 50.72 48.38 1033.3 ;
     RECT  45.22 1044.86 48.38 1048.42 ;
     RECT  36.1 36.44 53.18 36.64 ;
     RECT  48.38 46.52 53.18 1033.3 ;
     RECT  46.46 1074.68 56.54 1074.88 ;
     RECT  53.18 36.44 57.02 1033.3 ;
     RECT  48.38 1044.86 57.02 1049.26 ;
     RECT  46.46 1059.98 57.5 1064.38 ;
     RECT  56.54 1074.68 57.5 1079.5 ;
     RECT  57.02 36.44 58.94 1049.26 ;
     RECT  57.5 1059.98 58.94 1079.5 ;
     RECT  32.54 25.1 65.4 25.3 ;
     RECT  58.94 36.44 65.4 1079.5 ;
     RECT  65.4 18.8 66.12 1084.96 ;
     RECT  66.12 18.8 68.4 1081.18 ;
     RECT  68.4 15.02 69.12 1081.18 ;
     RECT  69.12 36.44 94.46 1075.3 ;
     RECT  94.46 36.44 100.7 1079.5 ;
     RECT  100.7 36.44 103.58 1082.02 ;
     RECT  103.58 36.44 103.78 1083.7 ;
     RECT  103.78 36.44 111.74 1081.6 ;
     RECT  69.12 25.1 114.62 25.3 ;
     RECT  111.74 36.02 114.62 1081.6 ;
     RECT  114.62 24.68 115.4 1081.6 ;
     RECT  115.4 18.8 116.12 1084.96 ;
     RECT  116.12 18.8 118.4 1081.6 ;
     RECT  118.4 15.02 119.12 1081.6 ;
     RECT  119.12 20.06 136.7 1081.6 ;
     RECT  136.7 20.06 147.94 1082.02 ;
     RECT  147.94 20.9 165.4 1082.02 ;
     RECT  165.4 18.8 166.12 1084.96 ;
     RECT  166.12 18.8 168.4 1082.02 ;
     RECT  168.4 15.02 169.12 1082.02 ;
     RECT  169.12 22.16 208.7 1082.02 ;
     RECT  208.7 20.9 215.4 1082.02 ;
     RECT  215.4 18.8 216.12 1084.96 ;
     RECT  216.12 18.8 218.4 1082.02 ;
     RECT  218.4 15.02 219.12 1082.02 ;
     RECT  219.12 1066.7 227.62 1082.02 ;
     RECT  227.62 1066.7 228.1 1072.36 ;
     RECT  219.12 20.48 230.3 1026.16 ;
     RECT  219.12 1036.46 230.3 1055.56 ;
     RECT  230.3 20.48 231.26 1055.56 ;
     RECT  228.1 1066.7 232.42 1066.9 ;
     RECT  231.26 20.48 233.38 1056.82 ;
     RECT  233.38 20.48 243.94 1053.04 ;
     RECT  243.94 21.74 246.82 1053.04 ;
     RECT  246.82 1052.84 248.26 1053.04 ;
     RECT  246.82 21.74 249.7 1041.7 ;
     RECT  249.7 23 265.4 1041.7 ;
     RECT  265.4 18.8 266.12 1084.96 ;
     RECT  266.12 18.8 268.4 1081.18 ;
     RECT  268.4 15.02 269.12 1081.18 ;
     RECT  269.12 21.74 281.66 1042.12 ;
     RECT  281.66 20.9 286.18 1042.12 ;
     RECT  286.18 20.9 286.66 1030.78 ;
     RECT  286.18 1041.5 287.62 1042.12 ;
     RECT  287.62 1041.5 289.54 1041.7 ;
     RECT  286.66 20.9 295.3 1029.1 ;
     RECT  295.3 20.9 296.74 1022.38 ;
     RECT  296.74 20.9 297.22 1021.96 ;
     RECT  297.22 20.9 297.7 1019.02 ;
     RECT  297.7 20.9 298.18 1015.24 ;
     RECT  298.18 20.9 298.66 1000.54 ;
     RECT  298.66 21.32 299.62 1000.54 ;
     RECT  299.62 62.06 302.98 1000.54 ;
     RECT  299.62 21.32 310.94 50.92 ;
     RECT  302.98 62.06 310.94 908.98 ;
     RECT  310.94 21.32 315.4 908.98 ;
     RECT  302.98 920.54 315.4 1000.54 ;
     RECT  298.18 1015.04 315.4 1015.24 ;
     RECT  315.4 18.8 316.12 1084.96 ;
     RECT  316.12 18.8 318.4 1081.18 ;
     RECT  318.4 15.02 319.12 1081.18 ;
     RECT  319.12 40.64 323.62 911.92 ;
     RECT  323.62 40.64 324.1 852.7 ;
     RECT  324.1 51.98 325.06 852.7 ;
     RECT  323.62 863 327.46 911.92 ;
     RECT  325.06 54.5 327.94 852.7 ;
     RECT  327.94 62.48 328.9 852.7 ;
     RECT  328.9 62.48 330.82 123.16 ;
     RECT  330.82 66.68 333.22 123.16 ;
     RECT  328.9 133.04 333.5 852.7 ;
     RECT  333.22 66.68 333.7 66.88 ;
     RECT  327.46 866.78 333.7 911.92 ;
     RECT  333.7 867.2 334.18 911.92 ;
     RECT  333.22 77.18 334.66 123.16 ;
     RECT  334.66 77.18 336.1 108.46 ;
     RECT  333.5 133.04 337.06 853.96 ;
     RECT  336.1 77.18 337.54 89.14 ;
     RECT  336.1 99.44 337.54 108.46 ;
     RECT  319.12 931.88 338.5 940.48 ;
     RECT  337.54 99.86 339.46 108.46 ;
     RECT  339.46 103.64 340.9 108.46 ;
     RECT  337.06 134.3 341.18 853.96 ;
     RECT  337.54 88.52 341.86 89.14 ;
     RECT  337.54 77.18 342.34 78.22 ;
     RECT  341.86 88.94 342.82 89.14 ;
     RECT  342.34 78.02 343.3 78.22 ;
     RECT  341.18 134.3 343.3 856.9 ;
     RECT  340.9 103.64 344.74 103.84 ;
     RECT  343.3 151.52 347.14 856.9 ;
     RECT  334.18 867.2 347.14 908.14 ;
     RECT  334.66 120.02 347.62 123.16 ;
     RECT  347.14 867.2 348.58 887.98 ;
     RECT  347.62 122.96 349.06 123.16 ;
     RECT  343.3 134.3 351.46 141.22 ;
     RECT  351.46 137.24 353.38 141.22 ;
     RECT  347.14 152.78 353.38 856.9 ;
     RECT  353.38 152.78 355.78 856.48 ;
     RECT  353.38 138.08 365.4 141.22 ;
     RECT  355.78 152.78 365.4 172.3 ;
     RECT  355.78 182.6 365.4 856.48 ;
     RECT  348.58 867.2 365.4 868.24 ;
     RECT  348.58 878.54 365.4 887.98 ;
     RECT  347.14 897.86 365.4 908.14 ;
     RECT  338.5 931.88 365.4 940.06 ;
     RECT  319.12 952.88 365.4 1000.54 ;
     RECT  319.12 1015.04 365.4 1015.24 ;
     RECT  365.4 18.8 366.12 1084.96 ;
     RECT  366.12 18.8 368.4 1081.18 ;
     RECT  368.4 15.02 369.12 1081.18 ;
     RECT  369.12 182.6 374.02 849.34 ;
     RECT  374.02 182.6 374.98 202.96 ;
     RECT  374.98 187.22 379.3 202.96 ;
     RECT  379.3 187.22 379.78 195.82 ;
     RECT  379.78 195.62 381.22 195.82 ;
     RECT  374.02 216.2 384.1 849.34 ;
     RECT  384.1 216.2 385.06 263.44 ;
     RECT  385.06 217.46 387.94 263.44 ;
     RECT  387.94 247.7 390.82 263.44 ;
     RECT  387.94 217.46 391.78 236.56 ;
     RECT  384.1 273.74 391.78 849.34 ;
     RECT  391.78 273.74 392.74 826.66 ;
     RECT  391.78 222.92 395.62 236.56 ;
     RECT  392.74 277.1 396.58 758.2 ;
     RECT  395.62 227.96 397.54 236.56 ;
     RECT  392.74 768.08 397.54 826.66 ;
     RECT  397.54 768.08 398.02 815.32 ;
     RECT  369.12 867.2 398.02 868.24 ;
     RECT  390.82 251.9 398.5 263.44 ;
     RECT  398.02 768.08 398.98 802.3 ;
     RECT  396.58 277.1 399.46 709.48 ;
     RECT  397.54 236.36 401.38 236.56 ;
     RECT  398.02 868.04 402.62 868.24 ;
     RECT  369.12 879.38 402.62 887.98 ;
     RECT  369.12 897.86 402.62 908.14 ;
     RECT  399.46 281.72 404.26 709.48 ;
     RECT  396.58 720.2 404.26 758.2 ;
     RECT  404.26 281.72 405.22 656.14 ;
     RECT  402.62 868.04 414.62 887.98 ;
     RECT  402.62 897.86 414.62 911.92 ;
     RECT  398.5 254.84 415.4 263.44 ;
     RECT  405.22 286.34 415.4 656.14 ;
     RECT  404.26 666.02 415.4 709.48 ;
     RECT  404.26 720.2 415.4 753.58 ;
     RECT  398.98 768.08 415.4 799.78 ;
     RECT  398.02 815.12 415.4 815.32 ;
     RECT  397.54 826.46 415.4 826.66 ;
     RECT  391.78 838.64 415.4 849.34 ;
     RECT  414.62 868.04 415.4 911.92 ;
     RECT  369.12 931.88 415.4 940.06 ;
     RECT  369.12 952.88 415.4 1000.54 ;
     RECT  369.12 1015.04 415.4 1015.24 ;
     RECT  415.4 18.8 416.12 1084.96 ;
     RECT  416.12 18.8 418.4 1081.18 ;
     RECT  418.4 15.02 419.12 1081.18 ;
     RECT  419.12 380.42 425.38 466.72 ;
     RECT  425.38 380.42 427.78 457.9 ;
     RECT  427.78 432.08 428.26 433.12 ;
     RECT  419.12 768.08 428.26 799.78 ;
     RECT  427.78 445.52 435.26 457.9 ;
     RECT  419.12 313.22 435.46 348.7 ;
     RECT  428.26 432.08 435.46 432.28 ;
     RECT  419.12 300.62 442.66 303.34 ;
     RECT  419.12 363.62 449.66 365.08 ;
     RECT  427.78 380.42 449.66 415.06 ;
     RECT  419.12 645.02 449.66 655.72 ;
     RECT  419.12 254.84 449.86 263.44 ;
     RECT  419.12 1015.04 449.86 1015.24 ;
     RECT  449.66 644.6 454.46 655.72 ;
     RECT  449.86 254.84 465.4 255.46 ;
     RECT  419.12 286.34 465.4 286.54 ;
     RECT  442.66 300.62 465.4 300.82 ;
     RECT  435.46 313.22 465.4 344.92 ;
     RECT  449.66 363.62 465.4 415.06 ;
     RECT  435.26 445.52 465.4 462.94 ;
     RECT  419.12 479.54 465.4 632.62 ;
     RECT  454.46 644.18 465.4 655.72 ;
     RECT  419.12 680.72 465.4 709.48 ;
     RECT  419.12 728.18 465.4 728.38 ;
     RECT  419.12 743.3 465.4 753.58 ;
     RECT  428.26 768.08 465.4 774.16 ;
     RECT  428.26 785.72 465.4 799.78 ;
     RECT  419.12 814.28 465.4 814.48 ;
     RECT  419.12 826.46 465.4 826.66 ;
     RECT  419.12 838.64 465.4 849.34 ;
     RECT  419.12 868.04 465.4 911.92 ;
     RECT  419.12 931.88 465.4 940.06 ;
     RECT  419.12 952.88 465.4 1000.54 ;
     RECT  465.4 18.8 466.12 1084.96 ;
     RECT  466.12 18.8 468.4 1081.18 ;
     RECT  468.4 15.02 469.12 1081.18 ;
     RECT  469.12 300.62 477.22 300.82 ;
     RECT  469.12 868.04 478.66 911.92 ;
     RECT  469.12 479.12 484.7 632.62 ;
     RECT  469.12 644.18 484.7 655.72 ;
     RECT  484.7 479.12 485.66 655.72 ;
     RECT  469.12 363.62 492.86 415.06 ;
     RECT  478.66 879.38 493.06 911.92 ;
     RECT  469.12 952.88 494.02 1000.54 ;
     RECT  485.66 479.12 496.7 658.66 ;
     RECT  469.12 446.78 503.42 462.94 ;
     RECT  496.7 479.12 503.42 666.22 ;
     RECT  469.12 254.84 515.4 255.46 ;
     RECT  469.12 286.34 515.4 286.54 ;
     RECT  469.12 313.22 515.4 344.92 ;
     RECT  492.86 356.06 515.4 415.06 ;
     RECT  503.42 446.78 515.4 666.22 ;
     RECT  469.12 680.72 515.4 709.48 ;
     RECT  469.12 728.18 515.4 728.38 ;
     RECT  469.12 743.3 515.4 753.58 ;
     RECT  469.12 768.08 515.4 774.16 ;
     RECT  469.12 785.72 515.4 799.78 ;
     RECT  469.12 814.28 515.4 814.48 ;
     RECT  469.12 826.46 515.4 826.66 ;
     RECT  469.12 838.64 515.4 849.34 ;
     RECT  478.66 868.04 515.4 868.24 ;
     RECT  493.06 879.38 515.4 903.94 ;
     RECT  469.12 931.88 515.4 940.06 ;
     RECT  494.02 952.88 515.4 965.68 ;
     RECT  494.02 975.98 515.4 1000.54 ;
     RECT  515.4 18.8 516.12 1084.96 ;
     RECT  516.12 18.8 518.4 1081.18 ;
     RECT  518.4 15.02 519.12 1081.18 ;
     RECT  519.12 356.06 526.18 415.06 ;
     RECT  519.12 313.22 528.86 344.92 ;
     RECT  519.12 254.84 529.06 255.46 ;
     RECT  519.12 814.28 529.06 814.48 ;
     RECT  528.86 313.22 533.38 346.18 ;
     RECT  526.18 356.06 549.7 356.26 ;
     RECT  519.12 931.88 550.66 939.64 ;
     RECT  529.06 254.84 565.4 255.04 ;
     RECT  519.12 286.34 565.4 286.54 ;
     RECT  533.38 313.22 565.4 344.92 ;
     RECT  526.18 371.18 565.4 415.06 ;
     RECT  519.12 446.78 565.4 666.22 ;
     RECT  519.12 680.72 565.4 709.48 ;
     RECT  519.12 728.18 565.4 728.38 ;
     RECT  519.12 743.3 565.4 753.58 ;
     RECT  519.12 768.08 565.4 774.16 ;
     RECT  519.12 785.72 565.4 799.78 ;
     RECT  519.12 826.46 565.4 826.66 ;
     RECT  519.12 838.64 565.4 849.34 ;
     RECT  519.12 868.04 565.4 868.24 ;
     RECT  519.12 879.38 565.4 903.94 ;
     RECT  550.66 932.3 565.4 939.64 ;
     RECT  519.12 952.88 565.4 965.68 ;
     RECT  519.12 975.98 565.4 1000.54 ;
     RECT  565.4 18.8 566.12 1084.96 ;
     RECT  566.12 18.8 568.4 1081.18 ;
     RECT  568.4 15.02 569.12 1081.18 ;
     RECT  569.12 838.64 586.66 849.34 ;
     RECT  586.66 838.64 601.54 838.84 ;
     RECT  569.12 254.84 615.4 255.04 ;
     RECT  569.12 286.34 615.4 286.54 ;
     RECT  569.12 313.22 615.4 344.92 ;
     RECT  569.12 371.18 615.4 415.06 ;
     RECT  569.12 446.78 615.4 666.22 ;
     RECT  569.12 680.72 615.4 709.48 ;
     RECT  569.12 728.18 615.4 728.38 ;
     RECT  569.12 743.3 615.4 753.58 ;
     RECT  569.12 768.08 615.4 774.16 ;
     RECT  569.12 785.72 615.4 799.78 ;
     RECT  569.12 826.46 615.4 826.66 ;
     RECT  586.66 849.14 615.4 849.34 ;
     RECT  569.12 868.04 615.4 868.24 ;
     RECT  569.12 879.38 615.4 903.94 ;
     RECT  569.12 932.3 615.4 932.5 ;
     RECT  569.12 952.88 615.4 965.68 ;
     RECT  569.12 975.98 615.4 1000.54 ;
     RECT  615.4 18.8 616.12 1084.96 ;
     RECT  616.12 18.8 618.4 1081.18 ;
     RECT  618.4 15.02 619.12 1081.18 ;
     RECT  619.12 680.72 629.86 709.48 ;
     RECT  619.12 952.88 637.06 965.68 ;
     RECT  619.12 879.38 644.26 903.94 ;
     RECT  619.12 313.22 648.58 344.92 ;
     RECT  619.12 785.72 651.46 799.78 ;
     RECT  619.12 254.84 665.4 255.04 ;
     RECT  619.12 286.34 665.4 286.54 ;
     RECT  648.58 313.22 665.4 319.72 ;
     RECT  648.58 329.6 665.4 344.92 ;
     RECT  619.12 371.18 665.4 415.06 ;
     RECT  619.12 446.78 665.4 666.22 ;
     RECT  629.86 680.72 665.4 693.52 ;
     RECT  629.86 707.6 665.4 709.48 ;
     RECT  619.12 728.18 665.4 728.38 ;
     RECT  619.12 743.3 665.4 753.58 ;
     RECT  619.12 773.96 665.4 774.16 ;
     RECT  651.46 788.24 665.4 799.78 ;
     RECT  619.12 826.46 665.4 826.66 ;
     RECT  619.12 849.14 665.4 849.34 ;
     RECT  619.12 868.04 665.4 868.24 ;
     RECT  644.26 879.38 665.4 887.98 ;
     RECT  644.26 903.74 665.4 903.94 ;
     RECT  619.12 932.3 665.4 932.5 ;
     RECT  637.06 952.88 665.4 953.08 ;
     RECT  637.06 965.48 665.4 965.68 ;
     RECT  619.12 975.98 665.4 1000.54 ;
     RECT  665.4 18.8 666.12 1084.96 ;
     RECT  666.12 18.8 668.4 1081.18 ;
     RECT  668.4 15.02 669.12 1081.18 ;
     RECT  669.12 371.18 673.06 415.06 ;
     RECT  669.12 826.46 673.06 826.66 ;
     RECT  669.12 707.6 673.54 709.48 ;
     RECT  669.12 329.6 680.26 344.92 ;
     RECT  669.12 975.98 680.26 1000.54 ;
     RECT  669.12 456.86 687.46 666.22 ;
     RECT  669.12 903.74 694.66 903.94 ;
     RECT  680.26 329.6 695.14 335.26 ;
     RECT  669.12 313.22 701.86 319.72 ;
     RECT  669.12 879.38 701.86 879.58 ;
     RECT  669.12 743.3 702.34 753.58 ;
     RECT  669.12 254.84 715.4 255.04 ;
     RECT  669.12 286.34 715.4 286.54 ;
     RECT  701.86 313.22 715.4 314.68 ;
     RECT  695.14 335.06 715.4 335.26 ;
     RECT  673.06 371.18 715.4 371.38 ;
     RECT  673.06 383.78 715.4 415.06 ;
     RECT  669.12 446.78 715.4 446.98 ;
     RECT  687.46 456.86 715.4 658.66 ;
     RECT  669.12 680.72 715.4 693.52 ;
     RECT  673.54 709.28 715.4 709.48 ;
     RECT  669.12 728.18 715.4 728.38 ;
     RECT  702.34 744.98 715.4 753.58 ;
     RECT  669.12 773.96 715.4 774.16 ;
     RECT  669.12 788.24 715.4 799.78 ;
     RECT  669.12 849.14 715.4 849.34 ;
     RECT  669.12 868.04 715.4 868.24 ;
     RECT  669.12 932.3 715.4 932.5 ;
     RECT  669.12 965.48 715.4 965.68 ;
     RECT  680.26 976.4 715.4 1000.54 ;
     RECT  715.4 18.8 716.12 1084.96 ;
     RECT  716.12 18.8 718.4 1081.18 ;
     RECT  718.4 15.02 719.12 1081.18 ;
     RECT  719.12 286.34 723.46 286.54 ;
     RECT  719.12 976.4 723.46 1000.54 ;
     RECT  719.12 456.86 723.94 658.66 ;
     RECT  719.12 744.98 723.94 753.58 ;
     RECT  719.12 371.18 730.66 371.38 ;
     RECT  719.12 788.24 730.66 799.78 ;
     RECT  723.94 744.98 731.62 751.9 ;
     RECT  719.12 254.84 737.86 255.04 ;
     RECT  731.62 744.98 738.34 751.06 ;
     RECT  719.12 383.78 741.22 415.06 ;
     RECT  719.12 335.06 745.06 335.26 ;
     RECT  719.12 965.48 745.06 965.68 ;
     RECT  723.46 976.4 745.54 993.82 ;
     RECT  719.12 680.72 746.02 693.52 ;
     RECT  719.12 313.22 752.26 314.68 ;
     RECT  730.66 788.24 752.26 794.74 ;
     RECT  723.94 479.12 753.22 658.66 ;
     RECT  752.26 313.22 765.4 313.42 ;
     RECT  741.22 383.78 765.4 414.64 ;
     RECT  746.3 436.7 765.4 436.9 ;
     RECT  719.12 446.78 765.4 446.98 ;
     RECT  723.94 456.86 765.4 462.94 ;
     RECT  753.22 479.12 765.4 645.64 ;
     RECT  753.22 658.46 765.4 658.66 ;
     RECT  746.02 680.72 765.4 680.92 ;
     RECT  746.02 693.32 765.4 693.52 ;
     RECT  719.12 709.28 765.4 709.48 ;
     RECT  719.12 728.18 765.4 728.38 ;
     RECT  738.34 744.98 765.4 745.18 ;
     RECT  719.12 773.96 765.4 774.16 ;
     RECT  752.26 788.24 765.4 788.44 ;
     RECT  719.12 868.04 765.4 868.24 ;
     RECT  719.12 932.3 765.4 932.5 ;
     RECT  745.54 976.4 765.4 987.1 ;
     RECT  765.4 18.8 766.12 1084.96 ;
     RECT  766.12 18.8 768.4 1081.18 ;
     RECT  768.4 15.02 769.12 1081.18 ;
     RECT  769.12 391.76 773.86 414.64 ;
     RECT  769.12 976.4 773.86 987.1 ;
     RECT  773.86 406.04 774.34 414.64 ;
     RECT  773.86 986.9 774.34 987.1 ;
     RECT  769.12 693.32 774.82 693.52 ;
     RECT  769.12 446.78 775.3 446.98 ;
     RECT  769.12 479.12 778.18 645.64 ;
     RECT  774.34 406.88 778.66 414.64 ;
     RECT  778.18 486.26 779.62 645.64 ;
     RECT  773.86 976.4 780.1 976.6 ;
     RECT  778.66 414.02 780.58 414.64 ;
     RECT  773.86 391.76 781.06 391.96 ;
     RECT  769.12 658.46 782.02 658.66 ;
     RECT  769.12 680.72 782.5 680.92 ;
     RECT  779.62 486.26 784.9 486.46 ;
     RECT  769.12 456.86 786.34 462.94 ;
     RECT  769.12 773.96 786.34 774.16 ;
     RECT  786.34 456.86 786.82 457.06 ;
     RECT  779.62 499.7 787.3 645.64 ;
     RECT  769.12 868.04 788.26 868.24 ;
     RECT  780.58 414.02 790.18 414.22 ;
     RECT  769.12 788.24 790.18 788.44 ;
     RECT  787.3 499.7 790.66 644.8 ;
     RECT  769.12 744.98 791.14 745.18 ;
     RECT  769.12 313.22 792.58 313.42 ;
     RECT  790.66 500.12 792.58 644.8 ;
     RECT  792.58 500.12 799.8 631.36 ;
    LAYER Metal4 ;
     RECT  165.26 14.9 169.26 28.46 ;
     RECT  153.02 25.94 153.22 43.58 ;
     RECT  165.26 28.46 171.94 46.1 ;
     RECT  144.86 43.58 153.22 48.4 ;
     RECT  151.58 48.4 153.22 48.82 ;
     RECT  285.98 50.3 286.18 52.4 ;
     RECT  115.26 14.9 119.26 54.5 ;
     RECT  109.34 54.5 119.26 54.92 ;
     RECT  131.42 43.58 131.62 54.92 ;
     RECT  109.34 54.92 131.62 57.44 ;
     RECT  165.26 46.1 172.42 57.44 ;
     RECT  164.06 57.44 172.42 57.86 ;
     RECT  162.62 57.86 172.42 58.54 ;
     RECT  151.58 48.82 151.78 58.7 ;
     RECT  162.14 58.54 172.42 58.9 ;
     RECT  151.58 58.7 152.26 59.96 ;
     RECT  151.58 59.96 152.74 60.16 ;
     RECT  164.06 58.9 172.42 60.16 ;
     RECT  98.78 59.12 98.98 60.38 ;
     RECT  109.34 57.44 138.82 60.38 ;
     RECT  315.26 14.9 319.26 62.06 ;
     RECT  98.78 60.38 138.82 62.9 ;
     RECT  285.98 52.4 287.62 67.52 ;
     RECT  98.3 62.9 141.7 67.94 ;
     RECT  15.26 14.9 19.26 69.2 ;
     RECT  215.26 14.9 219.26 69.62 ;
     RECT  234.62 66.26 234.82 69.62 ;
     RECT  92.06 67.94 141.7 70.24 ;
     RECT  92.06 70.24 119.26 71.92 ;
     RECT  152.06 60.16 152.74 73.82 ;
     RECT  165.26 60.16 172.42 73.82 ;
     RECT  200.54 59.54 200.74 73.82 ;
     RECT  285.98 67.52 289.06 74.02 ;
     RECT  129.5 70.24 141.7 75.5 ;
     RECT  152.06 73.82 172.42 75.5 ;
     RECT  197.66 73.82 200.74 75.7 ;
     RECT  215.26 69.62 234.82 76.96 ;
     RECT  92.06 71.92 99.46 80.96 ;
     RECT  315.26 62.06 319.78 83.48 ;
     RECT  315.26 83.48 326.98 85.16 ;
     RECT  9.5 69.2 19.26 86.2 ;
     RECT  200.06 75.7 200.74 86.62 ;
     RECT  315.26 85.16 327.46 88.1 ;
     RECT  129.5 75.5 172.42 89.14 ;
     RECT  200.06 86.62 200.26 89.14 ;
     RECT  215.26 76.96 232.9 89.14 ;
     RECT  89.66 80.96 99.46 89.36 ;
     RECT  315.26 88.1 327.94 93.34 ;
     RECT  285.98 74.02 287.62 94.18 ;
     RECT  232.22 89.14 232.9 96.92 ;
     RECT  287.42 94.18 287.62 97.12 ;
     RECT  232.22 96.92 233.38 97.34 ;
     RECT  48.38 46.52 48.58 99.02 ;
     RECT  15.26 86.2 19.26 99.44 ;
     RECT  141.5 89.14 172.42 99.64 ;
     RECT  86.78 89.36 99.46 100.7 ;
     RECT  109.34 71.92 119.26 100.7 ;
     RECT  152.06 99.64 172.42 100.7 ;
     RECT  232.22 97.34 234.82 101.12 ;
     RECT  86.78 100.7 119.26 101.96 ;
     RECT  129.5 89.14 131.62 101.96 ;
     RECT  86.78 101.96 131.62 104.06 ;
     RECT  315.26 93.34 319.78 104.06 ;
     RECT  252.38 97.3 252.58 104.48 ;
     RECT  201.5 104.14 201.7 104.68 ;
     RECT  32.54 25.1 32.74 106.58 ;
     RECT  252.38 104.48 253.54 106.78 ;
     RECT  80.06 104.06 131.62 107.2 ;
     RECT  152.06 100.7 182.5 108.26 ;
     RECT  141.5 99.64 141.7 109.94 ;
     RECT  152.06 108.26 190.66 109.94 ;
     RECT  215.26 89.14 219.26 109.94 ;
     RECT  232.22 101.12 239.62 109.94 ;
     RECT  215.26 109.94 239.62 110.56 ;
     RECT  215.26 110.56 233.38 111.82 ;
     RECT  141.5 109.94 190.66 112.46 ;
     RECT  113.66 107.2 131.62 112.66 ;
     RECT  215.26 111.82 232.42 112.66 ;
     RECT  129.5 112.66 131.62 114.56 ;
     RECT  141.5 112.46 195.94 114.56 ;
     RECT  215.26 112.66 224.26 114.76 ;
     RECT  129.5 114.56 195.94 120.1 ;
     RECT  80.06 107.2 100.42 121.48 ;
     RECT  129.5 120.1 197.86 122.32 ;
     RECT  48.38 99.02 54.82 122.54 ;
     RECT  65.26 14.9 69.26 122.54 ;
     RECT  115.26 112.66 119.26 122.54 ;
     RECT  315.26 104.06 321.7 122.74 ;
     RECT  80.06 121.48 99.94 122.96 ;
     RECT  113.66 122.54 119.26 123.38 ;
     RECT  252.38 106.78 252.58 123.38 ;
     RECT  265.26 14.9 269.26 123.38 ;
     RECT  48.38 122.54 69.26 124.64 ;
     RECT  79.1 122.96 99.94 124.64 ;
     RECT  146.78 122.32 197.86 126.32 ;
     RECT  215.26 114.76 219.26 126.32 ;
     RECT  111.74 123.38 119.26 129.26 ;
     RECT  129.5 122.32 136.42 129.26 ;
     RECT  9.02 99.44 19.26 133.24 ;
     RECT  111.74 129.26 136.42 134.72 ;
     RECT  146.78 126.32 219.26 134.72 ;
     RECT  14.78 133.24 19.26 134.92 ;
     RECT  239.42 126.74 239.62 136.4 ;
     RECT  48.38 124.64 99.94 141.86 ;
     RECT  111.74 134.72 219.26 141.86 ;
     RECT  237.98 136.4 239.62 142.06 ;
     RECT  48.38 141.86 219.26 142.48 ;
     RECT  237.98 142.06 238.18 143.54 ;
     RECT  237.5 143.54 238.18 150.88 ;
     RECT  15.26 134.92 19.26 151.1 ;
     RECT  237.5 150.88 237.7 151.3 ;
     RECT  252.38 123.38 269.26 151.3 ;
     RECT  214.46 142.48 219.26 154.04 ;
     RECT  285.98 151.1 286.18 154.88 ;
     RECT  10.46 151.1 19.26 158.86 ;
     RECT  48.38 142.48 201.7 158.86 ;
     RECT  315.26 122.74 319.26 159.5 ;
     RECT  285.5 154.88 287.14 159.7 ;
     RECT  285.98 159.7 287.14 160.54 ;
     RECT  252.38 151.3 252.58 163.42 ;
     RECT  265.26 151.3 269.26 163.42 ;
     RECT  48.38 158.86 202.66 164.32 ;
     RECT  315.26 159.5 320.26 165.58 ;
     RECT  214.46 154.04 222.34 175.66 ;
     RECT  48.38 164.32 135.94 175.88 ;
     RECT  145.82 164.32 202.66 175.88 ;
     RECT  32.54 106.58 37.54 176.3 ;
     RECT  7.1 158.86 19.26 184.06 ;
     RECT  48.38 175.88 202.66 186.22 ;
     RECT  215.26 175.66 222.34 186.22 ;
     RECT  252.38 163.42 269.26 190.78 ;
     RECT  9.02 184.06 19.26 195.34 ;
     RECT  234.62 194.36 234.82 197.5 ;
     RECT  48.38 186.22 222.34 199.9 ;
     RECT  298.46 151.52 298.66 201.5 ;
     RECT  295.58 201.5 298.66 201.7 ;
     RECT  7.1 195.34 19.26 202.34 ;
     RECT  32.54 176.3 38.5 202.34 ;
     RECT  344.06 202.76 344.26 204.02 ;
     RECT  7.1 202.34 38.5 206.54 ;
     RECT  48.38 199.9 230.98 207.8 ;
     RECT  48.38 207.8 235.78 209.06 ;
     RECT  248.06 190.78 269.26 209.06 ;
     RECT  6.62 206.54 38.5 209.48 ;
     RECT  48.38 209.06 269.26 209.48 ;
     RECT  6.62 209.48 269.26 209.9 ;
     RECT  343.1 204.02 344.26 210.52 ;
     RECT  6.62 209.9 276.1 213.46 ;
     RECT  315.26 165.58 319.26 215.78 ;
     RECT  248.06 213.46 276.1 218.72 ;
     RECT  295.58 201.7 295.78 223.76 ;
     RECT  307.58 215.78 319.26 223.76 ;
     RECT  6.62 213.46 237.22 226.06 ;
     RECT  337.82 215.36 338.02 226.06 ;
     RECT  6.62 226.06 235.78 230.06 ;
     RECT  365.26 14.9 369.26 235.94 ;
     RECT  295.58 223.76 319.26 236.14 ;
     RECT  248.06 218.72 277.54 236.56 ;
     RECT  4.22 230.06 235.78 240.98 ;
     RECT  2.78 240.98 235.78 242.66 ;
     RECT  338.78 227.12 338.98 243.22 ;
     RECT  365.26 235.94 371.14 243.7 ;
     RECT  2.78 242.66 236.26 244.54 ;
     RECT  302.78 236.14 319.26 251.9 ;
     RECT  248.06 236.56 269.26 252.1 ;
     RECT  365.26 243.7 369.26 254 ;
     RECT  2.78 244.54 235.78 254.42 ;
     RECT  2.78 254.42 237.7 256.52 ;
     RECT  248.06 252.1 253.06 256.52 ;
     RECT  365.26 254 377.38 256.9 ;
     RECT  263.9 252.1 269.26 257.98 ;
     RECT  365.26 256.9 378.82 258.82 ;
     RECT  265.26 257.98 269.26 261.98 ;
     RECT  365.26 258.82 378.34 263.94 ;
     RECT  338.78 243.22 339.94 264.92 ;
     RECT  337.82 264.92 339.94 266.8 ;
     RECT  286.94 262.82 287.14 268.48 ;
     RECT  265.26 261.98 272.74 270.58 ;
     RECT  338.78 266.8 339.94 277.1 ;
     RECT  298.94 251.9 319.26 278.78 ;
     RECT  334.46 277.1 339.94 278.78 ;
     RECT  298.94 278.78 339.94 285.5 ;
     RECT  2.78 256.52 253.06 294.74 ;
     RECT  265.26 270.58 281.38 294.74 ;
     RECT  365.26 263.94 376.9 294.94 ;
     RECT  2.78 294.74 281.38 300.22 ;
     RECT  2.78 300.22 288.58 302.3 ;
     RECT  298.94 285.5 341.86 302.3 ;
     RECT  365.26 294.94 376.42 307.34 ;
     RECT  356.06 307.34 376.42 307.76 ;
     RECT  356.06 307.76 380.26 308.6 ;
     RECT  356.06 308.6 385.06 314.9 ;
     RECT  2.78 302.3 341.86 316.78 ;
     RECT  315.26 316.78 341.86 319.3 ;
     RECT  353.66 314.9 385.06 319.3 ;
     RECT  332.54 319.3 341.86 324.76 ;
     RECT  2.78 316.78 302.98 326.02 ;
     RECT  298.94 326.02 302.98 334.84 ;
     RECT  315.26 319.3 321.22 340.52 ;
     RECT  338.78 324.76 341.86 340.52 ;
     RECT  315.26 340.52 341.86 341.46 ;
     RECT  337.34 341.46 341.86 341.98 ;
     RECT  315.26 341.46 321.22 343.24 ;
     RECT  337.34 341.98 339.94 343.24 ;
     RECT  2.78 326.02 288.58 349.76 ;
     RECT  302.78 334.84 302.98 349.76 ;
     RECT  353.66 319.3 380.26 351.64 ;
     RECT  315.26 343.24 320.74 352.06 ;
     RECT  2.78 349.76 302.98 352.7 ;
     RECT  315.26 352.06 319.26 352.7 ;
     RECT  353.66 351.64 377.38 352.9 ;
     RECT  338.78 343.24 339.94 353.12 ;
     RECT  334.46 353.12 339.94 359.42 ;
     RECT  334.46 359.42 349.54 360.26 ;
     RECT  359.42 352.9 377.38 368.66 ;
     RECT  330.62 360.26 349.54 370.34 ;
     RECT  359.42 368.66 380.26 370.34 ;
     RECT  330.62 370.34 380.26 378.32 ;
     RECT  2.78 352.7 319.26 382.52 ;
     RECT  330.62 378.32 384.58 382.52 ;
     RECT  2.78 382.52 384.58 391.12 ;
     RECT  384.38 391.12 384.58 399.1 ;
     RECT  2.78 391.12 369.26 403.3 ;
     RECT  364.7 403.3 369.26 409.82 ;
     RECT  315.26 403.3 346.18 411.7 ;
     RECT  364.7 409.82 370.66 412.54 ;
     RECT  365.26 412.54 370.66 416.5 ;
     RECT  384.86 403.1 385.06 416.5 ;
     RECT  365.26 416.5 385.06 417.58 ;
     RECT  2.78 403.3 302.98 424.94 ;
     RECT  315.26 411.7 345.22 437.32 ;
     RECT  365.26 417.58 375.46 441.1 ;
     RECT  389.66 428.72 389.86 443.84 ;
     RECT  380.54 443.84 389.86 445.3 ;
     RECT  2.78 424.94 303.46 450.56 ;
     RECT  315.26 437.32 327.94 450.56 ;
     RECT  389.66 445.3 389.86 452.02 ;
     RECT  2.78 450.56 327.94 453.92 ;
     RECT  338.78 437.32 345.22 453.92 ;
     RECT  2.78 453.92 345.22 469.66 ;
     RECT  2.78 469.66 339.94 493.18 ;
     RECT  365.26 441.1 369.26 498.58 ;
     RECT  333.98 493.18 339.94 504.1 ;
     RECT  359.9 498.58 369.26 507.26 ;
     RECT  334.46 504.1 339.94 514.4 ;
     RECT  353.18 507.26 369.26 514.4 ;
     RECT  334.46 514.4 369.26 516.7 ;
     RECT  353.18 516.7 369.26 523.42 ;
     RECT  391.1 522.8 391.3 523.64 ;
     RECT  334.46 516.7 339.94 524.9 ;
     RECT  782.78 513.56 782.98 526.78 ;
     RECT  386.3 523.64 391.3 529.72 ;
     RECT  2.78 493.18 319.26 541.7 ;
     RECT  2.78 541.7 323.14 543.58 ;
     RECT  333.02 524.9 339.94 543.58 ;
     RECT  338.78 543.58 339.94 546.74 ;
     RECT  356.54 523.42 369.26 546.74 ;
     RECT  391.1 529.72 391.3 548.62 ;
     RECT  338.78 546.74 369.26 551.14 ;
     RECT  338.78 551.14 348.58 552.82 ;
     RECT  338.78 552.82 339.94 554.3 ;
     RECT  2.78 543.58 319.26 555.14 ;
     RECT  365.26 551.14 369.26 557.66 ;
     RECT  396.86 554.3 397.06 559.34 ;
     RECT  365.26 557.66 369.7 562.28 ;
     RECT  2.78 555.14 327.94 565.22 ;
     RECT  337.82 554.3 339.94 565.22 ;
     RECT  396.38 559.34 397.06 565.22 ;
     RECT  395.9 565.22 397.06 565.42 ;
     RECT  395.9 565.42 396.58 566.06 ;
     RECT  393.5 566.06 396.58 567.94 ;
     RECT  394.94 567.94 396.58 568.78 ;
     RECT  365.26 562.28 375.46 569.62 ;
     RECT  365.26 569.62 369.7 573.82 ;
     RECT  395.9 568.78 396.1 582.64 ;
     RECT  787.58 579.08 787.78 583.06 ;
     RECT  2.78 565.22 339.94 588.1 ;
     RECT  381.98 593.78 382.18 599.86 ;
     RECT  2.78 588.1 319.26 602.6 ;
     RECT  0.38 602.6 319.26 603.64 ;
     RECT  2.78 603.64 319.26 604.7 ;
     RECT  353.66 604.7 353.86 605.12 ;
     RECT  2.78 604.7 322.18 613.1 ;
     RECT  332.54 588.1 339.94 613.1 ;
     RECT  352.22 605.12 353.86 614.14 ;
     RECT  789.98 615.2 790.18 616.88 ;
     RECT  789.98 616.88 792.58 617.92 ;
     RECT  365.26 573.82 369.26 624.02 ;
     RECT  792.38 617.92 792.58 624.64 ;
     RECT  2.78 613.1 339.94 627.16 ;
     RECT  353.66 614.14 353.86 628.64 ;
     RECT  365.26 624.02 372.58 630.94 ;
     RECT  791.42 629.48 791.62 639.76 ;
     RECT  353.18 628.64 353.86 641.02 ;
     RECT  265.26 627.16 339.94 643.12 ;
     RECT  353.66 641.02 353.86 648.16 ;
     RECT  332.54 643.12 339.94 652.16 ;
     RECT  365.26 630.94 369.26 655.52 ;
     RECT  265.26 643.12 319.26 656.78 ;
     RECT  365.26 655.52 376.9 656.78 ;
     RECT  265.26 656.78 319.78 657.62 ;
     RECT  332.54 652.16 344.74 657.62 ;
     RECT  265.26 657.62 344.74 658.24 ;
     RECT  265.26 658.24 327.94 658.38 ;
     RECT  365.26 656.78 381.7 661.18 ;
     RECT  338.3 658.24 344.74 661.6 ;
     RECT  312.86 658.38 327.94 662.44 ;
     RECT  314.3 662.44 327.94 668.54 ;
     RECT  338.3 661.6 342.34 668.54 ;
     RECT  2.78 627.16 254.5 669.7 ;
     RECT  314.3 668.54 342.34 675.04 ;
     RECT  365.26 661.18 369.26 684.08 ;
     RECT  381.5 661.18 381.7 684.08 ;
     RECT  314.3 675.04 341.38 688.28 ;
     RECT  365.26 684.08 381.7 689.74 ;
     RECT  265.26 658.38 302.98 689.96 ;
     RECT  263.42 689.96 302.98 691 ;
     RECT  381.5 689.74 381.7 692.68 ;
     RECT  265.26 691 302.98 695 ;
     RECT  312.86 688.28 341.38 695 ;
     RECT  265.26 695 341.38 701.08 ;
     RECT  310.94 701.08 341.38 705.7 ;
     RECT  310.94 705.7 324.1 710.74 ;
     RECT  315.26 710.74 324.1 716.42 ;
     RECT  353.18 716 353.38 722.72 ;
     RECT  315.26 716.42 328.9 726.92 ;
     RECT  353.18 722.72 354.82 734.26 ;
     RECT  314.78 726.92 328.9 735.1 ;
     RECT  338.78 705.7 341.38 735.94 ;
     RECT  314.78 735.1 324.1 745.6 ;
     RECT  354.62 734.26 354.82 751.06 ;
     RECT  265.26 701.08 301.06 756.1 ;
     RECT  315.26 745.6 324.1 756.32 ;
     RECT  315.26 756.32 324.58 758.62 ;
     RECT  365.26 689.74 369.26 765.14 ;
     RECT  265.26 756.1 291.46 769.76 ;
     RECT  338.78 735.94 339.94 770.1 ;
     RECT  265.26 769.76 296.26 779 ;
     RECT  265.26 779 298.66 782.14 ;
     RECT  2.78 669.7 253.06 784.24 ;
     RECT  298.46 782.14 298.66 792.44 ;
     RECT  298.46 792.44 303.94 792.64 ;
     RECT  365.26 765.14 372.1 795.38 ;
     RECT  303.74 792.64 303.94 799.78 ;
     RECT  365.26 795.38 373.06 803.56 ;
     RECT  2.78 784.24 248.26 807.98 ;
     RECT  265.26 782.14 288.58 807.98 ;
     RECT  339.74 770.1 339.94 809.44 ;
     RECT  301.82 810.5 302.02 813.02 ;
     RECT  301.82 813.02 302.98 819.32 ;
     RECT  2.78 807.98 288.58 835.06 ;
     RECT  301.82 819.32 305.38 838.22 ;
     RECT  315.26 758.62 319.26 838.22 ;
     RECT  301.82 838.22 319.26 838.42 ;
     RECT  334.94 826.04 335.14 840.52 ;
     RECT  2.78 835.06 239.14 843.06 ;
     RECT  256.22 835.06 288.58 845.14 ;
     RECT  302.78 838.42 319.26 845.14 ;
     RECT  485.66 658.46 485.86 847.62 ;
     RECT  265.26 845.14 288.58 852.7 ;
     RECT  281.18 852.7 288.58 854.46 ;
     RECT  302.78 845.14 305.38 856.7 ;
     RECT  300.86 856.7 305.38 856.9 ;
     RECT  284.06 854.46 288.58 867.62 ;
     RECT  300.86 856.9 301.06 867.62 ;
     RECT  284.06 867.62 301.06 874.54 ;
     RECT  265.26 852.7 269.26 875.18 ;
     RECT  265.26 875.18 277.06 877.9 ;
     RECT  251.9 876.86 252.1 878.74 ;
     RECT  265.26 877.9 274.18 891.76 ;
     RECT  288.38 874.54 301.06 897.64 ;
     RECT  2.78 843.06 237.7 906.46 ;
     RECT  265.26 891.76 273.7 907.1 ;
     RECT  262.46 907.1 273.7 907.3 ;
     RECT  300.86 897.64 301.06 907.3 ;
     RECT  262.46 907.3 269.26 909.2 ;
     RECT  258.62 909.2 269.26 911.72 ;
     RECT  253.82 911.72 269.26 912.56 ;
     RECT  252.38 912.56 269.26 913.6 ;
     RECT  2.78 906.46 219.94 918.3 ;
     RECT  288.38 897.64 288.58 920.54 ;
     RECT  4.22 918.3 219.94 936.7 ;
     RECT  232.22 906.46 237.7 939.64 ;
     RECT  4.22 936.7 219.26 946.36 ;
     RECT  288.38 920.54 297.7 947.2 ;
     RECT  4.22 946.36 188.26 947.62 ;
     RECT  33.02 947.62 188.26 948.46 ;
     RECT  201.02 946.36 219.26 953.92 ;
     RECT  4.22 947.62 22.18 955.6 ;
     RECT  253.82 913.6 269.26 957.5 ;
     RECT  288.38 947.2 288.58 957.5 ;
     RECT  82.46 948.46 188.26 957.7 ;
     RECT  201.98 953.92 219.26 957.7 ;
     RECT  252.38 957.5 269.26 957.7 ;
     RECT  33.02 948.46 72.58 957.92 ;
     RECT  237.5 939.64 237.7 958.34 ;
     RECT  252.38 957.7 253.06 958.34 ;
     RECT  82.46 957.7 175.3 958.54 ;
     RECT  4.22 955.6 19.26 959.34 ;
     RECT  288.38 957.5 295.78 962.12 ;
     RECT  31.58 957.92 72.58 962.74 ;
     RECT  141.5 958.54 175.3 964 ;
     RECT  60.38 962.74 72.58 965.06 ;
     RECT  82.46 958.54 130.66 965.06 ;
     RECT  237.5 958.34 253.06 966.52 ;
     RECT  7.1 959.34 19.26 967.16 ;
     RECT  31.58 962.74 49.54 967.16 ;
     RECT  283.58 962.12 295.78 968.46 ;
     RECT  60.38 965.06 130.66 968.84 ;
     RECT  141.5 964 154.18 968.84 ;
     RECT  164.06 964 175.3 969.26 ;
     RECT  188.06 957.7 188.26 969.26 ;
     RECT  207.74 957.7 219.26 970.52 ;
     RECT  231.26 967.58 232.9 971.56 ;
     RECT  232.7 971.56 232.9 972.4 ;
     RECT  60.38 968.84 154.18 974.5 ;
     RECT  87.26 974.5 154.18 974.72 ;
     RECT  164.06 969.26 188.26 974.72 ;
     RECT  87.26 974.72 188.26 975.76 ;
     RECT  7.1 967.16 49.54 976.18 ;
     RECT  60.38 974.5 73.06 976.18 ;
     RECT  87.26 975.76 175.3 976.6 ;
     RECT  283.58 968.46 283.78 976.6 ;
     RECT  9.02 976.18 49.54 977.02 ;
     RECT  87.26 976.6 90.34 977.44 ;
     RECT  188.06 975.76 188.26 978.08 ;
     RECT  60.38 976.18 71.14 980.38 ;
     RECT  207.26 970.52 219.26 981.44 ;
     RECT  188.06 978.08 190.18 982.06 ;
     RECT  206.78 981.44 219.26 982.7 ;
     RECT  206.78 982.7 225.7 983.54 ;
     RECT  206.78 983.54 226.66 983.96 ;
     RECT  243.26 966.52 253.06 983.96 ;
     RECT  9.02 977.02 31.78 984.58 ;
     RECT  42.62 977.02 49.54 985.42 ;
     RECT  65.26 980.38 71.14 986.26 ;
     RECT  15.26 984.58 31.78 988.36 ;
     RECT  100.22 976.6 175.3 988.36 ;
     RECT  87.26 977.44 87.46 988.78 ;
     RECT  206.78 983.96 253.06 990.46 ;
     RECT  212.06 990.46 253.06 992.36 ;
     RECT  188.06 982.06 188.26 992.56 ;
     RECT  135.74 988.36 175.3 992.98 ;
     RECT  212.06 992.36 253.54 993.4 ;
     RECT  100.22 988.36 125.38 995.5 ;
     RECT  29.18 988.36 31.78 996.34 ;
     RECT  295.58 968.46 295.78 997.18 ;
     RECT  148.7 992.98 175.3 997.6 ;
     RECT  103.58 995.5 125.38 999.5 ;
     RECT  135.74 992.98 135.94 999.5 ;
     RECT  212.06 993.4 253.06 1000.12 ;
     RECT  89.66 995.3 89.86 1000.54 ;
     RECT  65.26 986.26 69.7 1002.44 ;
     RECT  148.7 997.6 169.26 1003.06 ;
     RECT  212.06 1000.12 233.86 1003.9 ;
     RECT  65.26 1002.44 75.94 1004.74 ;
     RECT  15.26 988.36 19.26 1006.22 ;
     RECT  29.18 996.34 29.38 1006.22 ;
     RECT  65.26 1004.74 69.7 1007.26 ;
     RECT  103.58 999.5 135.94 1007.68 ;
     RECT  105.5 1007.68 135.94 1008.1 ;
     RECT  212.06 1003.9 226.66 1008.1 ;
     RECT  15.26 1006.22 29.38 1008.52 ;
     RECT  153.5 1003.06 169.26 1011.46 ;
     RECT  15.26 1008.52 28.9 1015.66 ;
     RECT  158.3 1011.46 169.26 1022.18 ;
     RECT  157.82 1022.18 169.26 1024.9 ;
     RECT  42.62 985.42 42.82 1031.2 ;
     RECT  250.94 1013.78 251.14 1034.14 ;
     RECT  105.5 1008.1 129.7 1037.08 ;
     RECT  158.3 1024.9 169.26 1043.8 ;
     RECT  105.5 1037.08 129.22 1045.48 ;
     RECT  105.5 1045.48 120.58 1055.98 ;
     RECT  65.26 1007.26 69.26 1058.3 ;
     RECT  164.54 1043.8 169.26 1058.5 ;
     RECT  115.26 1055.98 120.58 1072.78 ;
     RECT  63.74 1058.3 69.26 1079.5 ;
     RECT  15.26 1015.66 19.26 1085.08 ;
     RECT  65.26 1079.5 69.26 1085.08 ;
     RECT  115.26 1072.78 119.26 1085.08 ;
     RECT  165.26 1058.5 169.26 1085.08 ;
     RECT  215.26 1008.1 219.26 1085.08 ;
     RECT  265.26 957.7 269.26 1085.08 ;
     RECT  315.26 845.14 319.26 1085.08 ;
     RECT  365.26 803.56 369.26 1085.08 ;
     RECT  415.26 14.9 419.26 1085.08 ;
     RECT  465.26 14.9 469.26 1085.08 ;
     RECT  515.26 14.9 519.26 1085.08 ;
     RECT  565.26 14.9 569.26 1085.08 ;
     RECT  615.26 14.9 619.26 1085.08 ;
     RECT  665.26 14.9 669.26 1085.08 ;
     RECT  715.26 14.9 719.26 1085.08 ;
     RECT  765.26 14.9 769.26 1085.08 ;
    LAYER TopMetal1 ;
     RECT  2.06 917.38 3.5 919.02 ;
     RECT  3.5 917.38 5.76 960.06 ;
     RECT  5.76 24.12 793.92 1082.12 ;
  END
END ino_decode_queue
END LIBRARY
